              <access>read-write</access>
              <enumeratedValues>
                <enumeratedValue>
                  <name>0</name>
                  <description>Standard bus operation.</description>
                  <value>#0</value>
                </enumeratedValue>
                <enumeratedValue>
                  <name>1</name>
                  <description>Loss of arbitration.</description>
                  <value>#1</value>
                </enumeratedValue>
              </enumeratedValues>
            </field>
            <field>
              <name>BUSY</name>
              <description>Bus Busy</description>
              <bitOffset>5</bitOffset>
              <bitWidth>1</bitWidth>
              <access>read-only</access>
              <enumeratedValues>
                <enumeratedValue>
                  <name>0</name>
                  <description>Bus is idle</description>
                  <value>#0</value>
                </enumeratedValue>
                <enumeratedValue>
                  <name>1</name>
                  <description>Bus is busy</description>
                  <value>#1</value>
                </enumeratedValue>
              </enumeratedValues>
            </field>
            <field>
              <name>IAAS</name>
              <description>Addressed As A Slave</description>
              <bitOffset>6</bitOffset>
              <bitWidth>1</bitWidth>
              <access>read-write</access>
              <enumeratedValues>
                <enumeratedValue>
                  <name>0</name>
                  <description>Not addressed</description>
                  <value>#0</value>
                </enumeratedValue>
                <enumeratedValue>
                  <name>1</name>
                  <description>Addressed as a slave</description>
                  <value>#1</value>
                </enumeratedValue>
              </enumeratedValues>
            </field>
            <field>
              <name>TCF</name>
              <description>Transfer Complete Flag</description>
              <bitOffset>7</bitOffset>
              <bitWidth>1</bitWidth>
              <access>read-only</access>
              <enumeratedValues>
                <enumeratedValue>
                  <name>0</name>
                  <description>Transfer in progress</description>
                  <value>#0</value>
                </enumeratedValue>
                <enumeratedValue>
                  <name>1</name>
                  <description>Transfer complete</description>
                  <value>#1</value>
                </enumeratedValue>
              </enumeratedValues>
            </field>
          </fields>
        </register>
        <register>
          <name>D</name>
          <description>I2C Data I/O register</description>
          <addressOffset>0x4</addressOffset>
          <size>8</size>
          <access>read-write</access>
          <resetValue>0</resetValue>
          <resetMask>0xFF</resetMask>
          <fields>
            <field>
              <name>DATA</name>
              <description>Data</description>
              <bitOffset>0</bitOffset>
              <bitWidth>8</bitWidth>
              <access>read-write</access>
            </field>
          </fields>
        </register>
        <register>
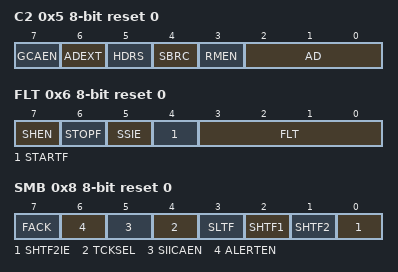
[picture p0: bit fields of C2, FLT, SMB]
          <name>C2</name>
          <description>I2C Control Register 2</description>
          <addressOffset>0x5</addressOffset>
          <size>8</size>
          <access>read-write</access>
          <resetValue>0</resetValue>
          <resetMask>0xFF</resetMask>
          <fields>
            <field>
              <name>AD</name>
              <description>Slave Address</description>
              <bitOffset>0</bitOffset>
              <bitWidth>3</bitWidth>
              <access>read-write</access>
            </field>
            <field>
              <name>RMEN</name>
              <description>Range Address Matching Enable</description>
              <bitOffset>3</bitOffset>
              <bitWidth>1</bitWidth>
              <access>read-write</access>
              <enumeratedValues>
                <enumeratedValue>
                  <name>0</name>
                  <description>Range mode disabled. No address match occurs for an address within the range of values of the A1 and RA registers.</description>
                  <value>#0</value>
                </enumeratedValue>
                <enumeratedValue>
                  <name>1</name>
                  <description>Range mode enabled. Address matching occurs when a slave receives an address within the range of values of the A1 and RA registers.</description>
                  <value>#1</value>
                </enumeratedValue>
              </enumeratedValues>
            </field>
            <field>
              <name>SBRC</name>
              <description>Slave Baud Rate Control</description>
              <bitOffset>4</bitOffset>
              <bitWidth>1</bitWidth>
              <access>read-write</access>
              <enumeratedValues>
                <enumeratedValue>
                  <name>0</name>
                  <description>The slave baud rate follows the master baud rate and clock stretching may occur</description>
                  <value>#0</value>
                </enumeratedValue>
                <enumeratedValue>
                  <name>1</name>
                  <description>Slave baud rate is independent of the master baud rate</description>
                  <value>#1</value>
                </enumeratedValue>
              </enumeratedValues>
            </field>
            <field>
              <name>HDRS</name>
              <description>High Drive Select</description>
              <bitOffset>5</bitOffset>
              <bitWidth>1</bitWidth>
              <access>read-write</access>
              <enumeratedValues>
                <enumeratedValue>
                  <name>0</name>
                  <description>Normal drive mode</description>
                  <value>#0</value>
                </enumeratedValue>
                <enumeratedValue>
                  <name>1</name>
                  <description>High drive mode</description>
                  <value>#1</value>
                </enumeratedValue>
              </enumeratedValues>
            </field>
            <field>
              <name>ADEXT</name>
              <description>Address Extension</description>
              <bitOffset>6</bitOffset>
              <bitWidth>1</bitWidth>
              <access>read-write</access>
              <enumeratedValues>
                <enumeratedValue>
                  <name>0</name>
                  <description>7-bit address scheme</description>
                  <value>#0</value>
                </enumeratedValue>
                <enumeratedValue>
                  <name>1</name>
                  <description>10-bit address scheme</description>
                  <value>#1</value>
                </enumeratedValue>
              </enumeratedValues>
            </field>
            <field>
              <name>GCAEN</name>
              <description>General Call Address Enable</description>
              <bitOffset>7</bitOffset>
              <bitWidth>1</bitWidth>
              <access>read-write</access>
              <enumeratedValues>
                <enumeratedValue>
                  <name>0</name>
                  <description>Disabled</description>
                  <value>#0</value>
                </enumeratedValue>
                <enumeratedValue>
                  <name>1</name>
                  <description>Enabled</description>
                  <value>#1</value>
                </enumeratedValue>
              </enumeratedValues>
            </field>
          </fields>
        </register>
        <register>
          <name>FLT</name>
          <description>I2C Programmable Input Glitch Filter register</description>
          <addressOffset>0x6</addressOffset>
          <size>8</size>
          <access>read-write</access>
          <resetValue>0</resetValue>
          <resetMask>0xFF</resetMask>
          <fields>
            <field>
              <name>FLT</name>
              <description>I2C Programmable Filter Factor</description>
              <bitOffset>0</bitOffset>
              <bitWidth>4</bitWidth>
              <access>read-write</access>
              <enumeratedValues>
                <enumeratedValue>
                  <name>0</name>
                  <description>No filter/bypass</description>
                  <value>#0000</value>
                </enumeratedValue>
              </enumeratedValues>
            </field>
            <field>
              <name>STARTF</name>
              <description>I2C Bus Start Detect Flag</description>
              <bitOffset>4</bitOffset>
              <bitWidth>1</bitWidth>
              <access>read-write</access>
              <enumeratedValues>
                <enumeratedValue>
                  <name>0</name>
                  <description>No start happens on I2C bus</description>
                  <value>#0</value>
                </enumeratedValue>
                <enumeratedValue>
                  <name>1</name>
                  <description>Start detected on I2C bus</description>
                  <value>#1</value>
                </enumeratedValue>
              </enumeratedValues>
            </field>
            <field>
              <name>SSIE</name>
              <description>I2C Bus Stop or Start Interrupt Enable</description>
              <bitOffset>5</bitOffset>
              <bitWidth>1</bitWidth>
              <access>read-write</access>
              <enumeratedValues>
                <enumeratedValue>
                  <name>0</name>
                  <description>Stop or start detection interrupt is disabled</description>
                  <value>#0</value>
                </enumeratedValue>
                <enumeratedValue>
                  <name>1</name>
                  <description>Stop or start detection interrupt is enabled</description>
                  <value>#1</value>
                </enumeratedValue>
              </enumeratedValues>
            </field>
            <field>
              <name>STOPF</name>
              <description>I2C Bus Stop Detect Flag</description>
              <bitOffset>6</bitOffset>
              <bitWidth>1</bitWidth>
              <access>read-write</access>
              <enumeratedValues>
                <enumeratedValue>
                  <name>0</name>
                  <description>No stop happens on I2C bus</description>
                  <value>#0</value>
                </enumeratedValue>
                <enumeratedValue>
                  <name>1</name>
                  <description>Stop detected on I2C bus</description>
                  <value>#1</value>
                </enumeratedValue>
              </enumeratedValues>
            </field>
            <field>
              <name>SHEN</name>
              <description>Stop Hold Enable</description>
              <bitOffset>7</bitOffset>
              <bitWidth>1</bitWidth>
              <access>read-write</access>
              <enumeratedValues>
                <enumeratedValue>
                  <name>0</name>
                  <description>Stop holdoff is disabled. The MCU&apos;s entry to stop mode is not gated.</description>
                  <value>#0</value>
                </enumeratedValue>
                <enumeratedValue>
                  <name>1</name>
                  <description>Stop holdoff is enabled.</description>
                  <value>#1</value>
                </enumeratedValue>
              </enumeratedValues>
            </field>
          </fields>
        </register>
        <register>
          <name>RA</name>
          <description>I2C Range Address register</description>
          <addressOffset>0x7</addressOffset>
          <size>8</size>
          <access>read-write</access>
          <resetValue>0</resetValue>
          <resetMask>0xFF</resetMask>
          <fields>
            <field>
              <name>RAD</name>
              <description>Range Slave Address</description>
              <bitOffset>1</bitOffset>
              <bitWidth>7</bitWidth>
              <access>read-write</access>
            </field>
          </fields>
        </register>
        <register>
          <name>SMB</name>
          <description>I2C SMBus Control and Status register</description>
          <addressOffset>0x8</addressOffset>
          <size>8</size>
          <access>read-write</access>
          <resetValue>0</resetValue>
          <resetMask>0xFF</resetMask>
          <fields>
            <field>
              <name>SHTF2IE</name>
              <description>SHTF2 Interrupt Enable</description>
              <bitOffset>0</bitOffset>
              <bitWidth>1</bitWidth>
              <access>read-write</access>
              <enumeratedValues>
                <enumeratedValue>
                  <name>0</name>
                  <description>SHTF2 interrupt is disabled</description>
                  <value>#0</value>
                </enumeratedValue>
                <enumeratedValue>
                  <name>1</name>
                  <description>SHTF2 interrupt is enabled</description>
                  <value>#1</value>
                </enumeratedValue>
              </enumeratedValues>
            </field>
            <field>
              <name>SHTF2</name>
              <description>SCL High Timeout Flag 2</description>
              <bitOffset>1</bitOffset>
              <bitWidth>1</bitWidth>
              <access>read-write</access>
              <enumeratedValues>
                <enumeratedValue>
                  <name>0</name>
                  <description>No SCL high and SDA low timeout occurs</description>
                  <value>#0</value>
                </enumeratedValue>
                <enumeratedValue>
                  <name>1</name>
                  <description>SCL high and SDA low timeout occurs</description>
                  <value>#1</value>
                </enumeratedValue>
              </enumeratedValues>
            </field>
            <field>
              <name>SHTF1</name>
              <description>SCL High Timeout Flag 1</description>
              <bitOffset>2</bitOffset>
              <bitWidth>1</bitWidth>
              <access>read-only</access>
              <enumeratedValues>
                <enumeratedValue>
                  <name>0</name>
                  <description>No SCL high and SDA high timeout occurs</description>
                  <value>#0</value>
                </enumeratedValue>
                <enumeratedValue>
                  <name>1</name>
                  <description>SCL high and SDA high timeout occurs</description>
                  <value>#1</value>
                </enumeratedValue>
              </enumeratedValues>
            </field>
            <field>
              <name>SLTF</name>
              <description>SCL Low Timeout Flag</description>
              <bitOffset>3</bitOffset>
              <bitWidth>1</bitWidth>
              <access>read-write</access>
              <enumeratedValues>
                <enumeratedValue>
                  <name>0</name>
                  <description>No low timeout occurs</description>
                  <value>#0</value>
                </enumeratedValue>
                <enumeratedValue>
                  <name>1</name>
                  <description>Low timeout occurs</description>
                  <value>#1</value>
                </enumeratedValue>
              </enumeratedValues>
            </field>
            <field>
              <name>TCKSEL</name>
              <description>Timeout Counter Clock Select</description>
              <bitOffset>4</bitOffset>
              <bitWidth>1</bitWidth>
              <access>read-write</access>
              <enumeratedValues>
                <enumeratedValue>
                  <name>0</name>
                  <description>Timeout counter counts at the frequency of the I2C module clock / 64</description>
                  <value>#0</value>
                </enumeratedValue>
                <enumeratedValue>
                  <name>1</name>
                  <description>Timeout counter counts at the frequency of the I2C module clock</description>
                  <value>#1</value>
                </enumeratedValue>
              </enumeratedValues>
            </field>
            <field>
              <name>SIICAEN</name>
              <description>Second I2C Address Enable</description>
              <bitOffset>5</bitOffset>
              <bitWidth>1</bitWidth>
              <access>read-write</access>
              <enumeratedValues>
                <enumeratedValue>
                  <name>0</name>
                  <description>I2C address register 2 matching is disabled</description>
                  <value>#0</value>
                </enumeratedValue>
                <enumeratedValue>
                  <name>1</name>
                  <description>I2C address register 2 matching is enabled</description>
                  <value>#1</value>
                </enumeratedValue>
              </enumeratedValues>
            </field>
            <field>
              <name>ALERTEN</name>
              <description>SMBus Alert Response Address Enable</description>
              <bitOffset>6</bitOffset>
              <bitWidth>1</bitWidth>
              <access>read-write</access>
              <enumeratedValues>
                <enumeratedValue>
                  <name>0</name>
                  <description>SMBus alert response address matching is disabled</description>
                  <value>#0</value>
                </enumeratedValue>
                <enumeratedValue>
                  <name>1</name>
                  <description>SMBus alert response address matching is enabled</description>
                  <value>#1</value>
                </enumeratedValue>
              </enumeratedValues>
            </field>
            <field>
              <name>FACK</name>
              <description>Fast NACK/ACK Enable</description>
              <bitOffset>7</bitOffset>
              <bitWidth>1</bitWidth>
              <access>read-write</access>
              <enumeratedValues>
                <enumeratedValue>
                  <name>0</name>
                  <description>An ACK or NACK is sent on the following receiving data byte</description>
                  <value>#0</value>
                </enumeratedValue>
                <enumeratedValue>
                  <name>1</name>
                  <description>Writing 0 to TXAK after receiving a data byte generates an ACK. Writing 1 to TXAK after receiving a data byte generates a NACK.</description>
                  <value>#1</value>
                </enumeratedValue>
              </enumeratedValues>
            </field>
          </fields>
        </register>
        <register>
          <name>A2</name>
          <description>I2C Address Register 2</description>
          <addressOffset>0x9</addressOffset>
          <size>8</size>
          <access>read-write</access>
          <resetValue>0xC2</resetValue>
          <resetMask>0xFF</resetMask>
          <fields>
            <field>
              <name>SAD</name>
              <description>SMBus Address</description>
              <bitOffset>1</bitOffset>
              <bitWidth>7</bitWidth>
              <access>read-write</access>
            </field>
          </fields>
        </register>
        <register>
          <name>SLTH</name>
          <description>I2C SCL Low Timeout Register High</description>
          <addressOffset>0xA</addressOffset>
          <size>8</size>
          <access>read-write</access>
          <resetValue>0</resetValue>
          <resetMask>0xFF</resetMask>
          <fields>
            <field>
              <name>SSLT</name>
              <description>Most significant byte of SCL low timeout value that determines the timeout period of SCL low.</description>
              <bitOffset>0</bitOffset>
              <bitWidth>8</bitWidth>
              <access>read-write</access>
            </field>
          </fields>
        </register>
        <register>
          <name>SLTL</name>
          <description>I2C SCL Low Timeout Register Low</description>
          <addressOffset>0xB</addressOffset>
          <size>8</size>
          <access>read-write</access>
          <resetValue>0</resetValue>
          <resetMask>0xFF</resetMask>
          <fields>
            <field>
              <name>SSLT</name>
              <description>Least significant byte of SCL low timeout value that determines the timeout period of SCL low.</description>
              <bitOffset>0</bitOffset>
              <bitWidth>8</bitWidth>
              <access>read-write</access>
            </field>
          </fields>
        </register>
      </registers>
    </peripheral>
    <peripheral>
      <name>I2C1</name>
      <description>Inter-Integrated Circuit</description>
      <groupName>I2C</groupName>
      <prependToName>I2C1_</prependToName>
      <baseAddress>0x40067000</baseAddress>
      <addressBlock>
        <offset>0</offset>
        <size>0xC</size>
        <usage>registers</usage>
      </addressBlock>
      <interrupt>
        <name>I2C1</name>
        <value>9</value>
      </interrupt>
      <registers>
        <register>
          <name>A1</name>
          <description>I2C Address Register 1</description>
          <addressOffset>0</addressOffset>
          <size>8</size>
          <access>read-write</access>
          <resetValue>0</resetValue>
          <resetMask>0xFF</resetMask>
          <fields>
            <field>
              <name>AD</name>
              <description>Address</description>
              <bitOffset>1</bitOffset>
              <bitWidth>7</bitWidth>
              <access>read-write</access>
            </field>
          </fields>
        </register>
        <register>
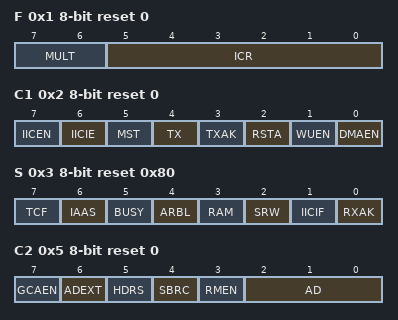
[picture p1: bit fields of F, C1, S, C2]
          <name>F</name>
          <description>I2C Frequency Divider register</description>
          <addressOffset>0x1</addressOffset>
          <size>8</size>
          <access>read-write</access>
          <resetValue>0</resetValue>
          <resetMask>0xFF</resetMask>
          <fields>
            <field>
              <name>ICR</name>
              <description>ClockRate</description>
              <bitOffset>0</bitOffset>
              <bitWidth>6</bitWidth>
              <access>read-write</access>
            </field>
            <field>
              <name>MULT</name>
              <description>Multiplier Factor</description>
              <bitOffset>6</bitOffset>
              <bitWidth>2</bitWidth>
              <access>read-write</access>
              <enumeratedValues>
                <enumeratedValue>
                  <name>00</name>
                  <description>mul = 1</description>
                  <value>#00</value>
                </enumeratedValue>
                <enumeratedValue>
                  <name>01</name>
                  <description>mul = 2</description>
                  <value>#01</value>
                </enumeratedValue>
                <enumeratedValue>
                  <name>10</name>
                  <description>mul = 4</description>
                  <value>#10</value>
                </enumeratedValue>
              </enumeratedValues>
            </field>
          </fields>
        </register>
        <register>
          <name>C1</name>
          <description>I2C Control Register 1</description>
          <addressOffset>0x2</addressOffset>
          <size>8</size>
          <access>read-write</access>
          <resetValue>0</resetValue>
          <resetMask>0xFF</resetMask>
          <fields>
            <field>
              <name>DMAEN</name>
              <description>DMA Enable</description>
              <bitOffset>0</bitOffset>
              <bitWidth>1</bitWidth>
              <access>read-write</access>
              <enumeratedValues>
                <enumeratedValue>
                  <name>0</name>
                  <description>All DMA signalling disabled.</description>
                  <value>#0</value>
                </enumeratedValue>
                <enumeratedValue>
                  <name>1</name>
                  <description>DMA transfer is enabled. While SMB[FACK] = 0, the following conditions trigger the DMA request: a data byte is received, and either address or data is transmitted. (ACK/NACK is automatic) the first byte received matches the A1 register or is a general call address. If any address matching occurs, S[IAAS] and S[TCF] are set. If the direction of transfer is known from master to slave, then it is not required to check S[SRW]. With this assumption, DMA can also be used in this case. In other cases, if the master reads data from the slave, then it is required to rewrite the C1 register operation. With this assumption, DMA cannot be used. When FACK = 1, an address or a data byte is transmitted.</description>
                  <value>#1</value>
                </enumeratedValue>
              </enumeratedValues>
            </field>
            <field>
              <name>WUEN</name>
              <description>Wakeup Enable</description>
              <bitOffset>1</bitOffset>
              <bitWidth>1</bitWidth>
              <access>read-write</access>
              <enumeratedValues>
                <enumeratedValue>
                  <name>0</name>
                  <description>Normal operation. No interrupt generated when address matching in low power mode.</description>
                  <value>#0</value>
                </enumeratedValue>
                <enumeratedValue>
                  <name>1</name>
                  <description>Enables the wakeup function in low power mode.</description>
                  <value>#1</value>
                </enumeratedValue>
              </enumeratedValues>
            </field>
            <field>
              <name>RSTA</name>
              <description>Repeat START</description>
              <bitOffset>2</bitOffset>
              <bitWidth>1</bitWidth>
              <access>write-only</access>
            </field>
            <field>
              <name>TXAK</name>
              <description>Transmit Acknowledge Enable</description>
              <bitOffset>3</bitOffset>
              <bitWidth>1</bitWidth>
              <access>read-write</access>
              <enumeratedValues>
                <enumeratedValue>
                  <name>0</name>
                  <description>An acknowledge signal is sent to the bus on the following receiving byte (if FACK is cleared) or the current receiving byte (if FACK is set).</description>
                  <value>#0</value>
                </enumeratedValue>
                <enumeratedValue>
                  <name>1</name>
                  <description>No acknowledge signal is sent to the bus on the following receiving data byte (if FACK is cleared) or the current receiving data byte (if FACK is set).</description>
                  <value>#1</value>
                </enumeratedValue>
              </enumeratedValues>
            </field>
            <field>
              <name>TX</name>
              <description>Transmit Mode Select</description>
              <bitOffset>4</bitOffset>
              <bitWidth>1</bitWidth>
              <access>read-write</access>
              <enumeratedValues>
                <enumeratedValue>
                  <name>0</name>
                  <description>Receive</description>
                  <value>#0</value>
                </enumeratedValue>
                <enumeratedValue>
                  <name>1</name>
                  <description>Transmit</description>
                  <value>#1</value>
                </enumeratedValue>
              </enumeratedValues>
            </field>
            <field>
              <name>MST</name>
              <description>Master Mode Select</description>
              <bitOffset>5</bitOffset>
              <bitWidth>1</bitWidth>
              <access>read-write</access>
              <enumeratedValues>
                <enumeratedValue>
                  <name>0</name>
                  <description>Slave mode</description>
                  <value>#0</value>
                </enumeratedValue>
                <enumeratedValue>
                  <name>1</name>
                  <description>Master mode</description>
                  <value>#1</value>
                </enumeratedValue>
              </enumeratedValues>
            </field>
            <field>
              <name>IICIE</name>
              <description>I2C Interrupt Enable</description>
              <bitOffset>6</bitOffset>
              <bitWidth>1</bitWidth>
              <access>read-write</access>
              <enumeratedValues>
                <enumeratedValue>
                  <name>0</name>
                  <description>Disabled</description>
                  <value>#0</value>
                </enumeratedValue>
                <enumeratedValue>
                  <name>1</name>
                  <description>Enabled</description>
                  <value>#1</value>
                </enumeratedValue>
              </enumeratedValues>
            </field>
            <field>
              <name>IICEN</name>
              <description>I2C Enable</description>
              <bitOffset>7</bitOffset>
              <bitWidth>1</bitWidth>
              <access>read-write</access>
              <enumeratedValues>
                <enumeratedValue>
                  <name>0</name>
                  <description>Disabled</description>
                  <value>#0</value>
                </enumeratedValue>
                <enumeratedValue>
                  <name>1</name>
                  <description>Enabled</description>
                  <value>#1</value>
                </enumeratedValue>
              </enumeratedValues>
            </field>
          </fields>
        </register>
        <register>
          <name>S</name>
          <description>I2C Status register</description>
          <addressOffset>0x3</addressOffset>
          <size>8</size>
          <access>read-write</access>
          <resetValue>0x80</resetValue>
          <resetMask>0xFF</resetMask>
          <fields>
            <field>
              <name>RXAK</name>
              <description>Receive Acknowledge</description>
              <bitOffset>0</bitOffset>
              <bitWidth>1</bitWidth>
              <access>read-only</access>
              <enumeratedValues>
                <enumeratedValue>
                  <name>0</name>
                  <description>Acknowledge signal was received after the completion of one byte of data transmission on the bus</description>
                  <value>#0</value>
                </enumeratedValue>
                <enumeratedValue>
                  <name>1</name>
                  <description>No acknowledge signal detected</description>
                  <value>#1</value>
                </enumeratedValue>
              </enumeratedValues>
            </field>
            <field>
              <name>IICIF</name>
              <description>Interrupt Flag</description>
              <bitOffset>1</bitOffset>
              <bitWidth>1</bitWidth>
              <access>read-write</access>
              <enumeratedValues>
                <enumeratedValue>
                  <name>0</name>
                  <description>No interrupt pending</description>
                  <value>#0</value>
                </enumeratedValue>
                <enumeratedValue>
                  <name>1</name>
                  <description>Interrupt pending</description>
                  <value>#1</value>
                </enumeratedValue>
              </enumeratedValues>
            </field>
            <field>
              <name>SRW</name>
              <description>Slave Read/Write</description>
              <bitOffset>2</bitOffset>
              <bitWidth>1</bitWidth>
              <access>read-only</access>
              <enumeratedValues>
                <enumeratedValue>
                  <name>0</name>
                  <description>Slave receive, master writing to slave</description>
                  <value>#0</value>
                </enumeratedValue>
                <enumeratedValue>
                  <name>1</name>
                  <description>Slave transmit, master reading from slave</description>
                  <value>#1</value>
                </enumeratedValue>
              </enumeratedValues>
            </field>
            <field>
              <name>RAM</name>
              <description>Range Address Match</description>
              <bitOffset>3</bitOffset>
              <bitWidth>1</bitWidth>
              <access>read-write</access>
              <enumeratedValues>
                <enumeratedValue>
                  <name>0</name>
                  <description>Not addressed</description>
                  <value>#0</value>
                </enumeratedValue>
                <enumeratedValue>
                  <name>1</name>
                  <description>Addressed as a slave</description>
                  <value>#1</value>
                </enumeratedValue>
              </enumeratedValues>
            </field>
            <field>
              <name>ARBL</name>
              <description>Arbitration Lost</description>
              <bitOffset>4</bitOffset>
              <bitWidth>1</bitWidth>
              <access>read-write</access>
              <enumeratedValues>
                <enumeratedValue>
                  <name>0</name>
                  <description>Standard bus operation.</description>
                  <value>#0</value>
                </enumeratedValue>
                <enumeratedValue>
                  <name>1</name>
                  <description>Loss of arbitration.</description>
                  <value>#1</value>
                </enumeratedValue>
              </enumeratedValues>
            </field>
            <field>
              <name>BUSY</name>
              <description>Bus Busy</description>
              <bitOffset>5</bitOffset>
              <bitWidth>1</bitWidth>
              <access>read-only</access>
              <enumeratedValues>
                <enumeratedValue>
                  <name>0</name>
                  <description>Bus is idle</description>
                  <value>#0</value>
                </enumeratedValue>
                <enumeratedValue>
                  <name>1</name>
                  <description>Bus is busy</description>
                  <value>#1</value>
                </enumeratedValue>
              </enumeratedValues>
            </field>
            <field>
              <name>IAAS</name>
              <description>Addressed As A Slave</description>
              <bitOffset>6</bitOffset>
              <bitWidth>1</bitWidth>
              <access>read-write</access>
              <enumeratedValues>
                <enumeratedValue>
                  <name>0</name>
                  <description>Not addressed</description>
                  <value>#0</value>
                </enumeratedValue>
                <enumeratedValue>
                  <name>1</name>
                  <description>Addressed as a slave</description>
                  <value>#1</value>
                </enumeratedValue>
              </enumeratedValues>
            </field>
            <field>
              <name>TCF</name>
              <description>Transfer Complete Flag</description>
              <bitOffset>7</bitOffset>
              <bitWidth>1</bitWidth>
              <access>read-only</access>
              <enumeratedValues>
                <enumeratedValue>
                  <name>0</name>
                  <description>Transfer in progress</description>
                  <value>#0</value>
                </enumeratedValue>
                <enumeratedValue>
                  <name>1</name>
                  <description>Transfer complete</description>
                  <value>#1</value>
                </enumeratedValue>
              </enumeratedValues>
            </field>
          </fields>
        </register>
        <register>
          <name>D</name>
          <description>I2C Data I/O register</description>
          <addressOffset>0x4</addressOffset>
          <size>8</size>
          <access>read-write</access>
          <resetValue>0</resetValue>
          <resetMask>0xFF</resetMask>
          <fields>
            <field>
              <name>DATA</name>
              <description>Data</description>
              <bitOffset>0</bitOffset>
              <bitWidth>8</bitWidth>
              <access>read-write</access>
            </field>
          </fields>
        </register>
        <register>
          <name>C2</name>
          <description>I2C Control Register 2</description>
          <addressOffset>0x5</addressOffset>
          <size>8</size>
          <access>read-write</access>
          <resetValue>0</resetValue>
          <resetMask>0xFF</resetMask>
          <fields>
            <field>
              <name>AD</name>
              <description>Slave Address</description>
              <bitOffset>0</bitOffset>
              <bitWidth>3</bitWidth>
              <access>read-write</access>
            </field>
            <field>
              <name>RMEN</name>
              <description>Range Address Matching Enable</description>
              <bitOffset>3</bitOffset>
              <bitWidth>1</bitWidth>
              <access>read-write</access>
              <enumeratedValues>
                <enumeratedValue>
                  <name>0</name>
                  <description>Range mode disabled. No address match occurs for an address within the range of values of the A1 and RA registers.</description>
                  <value>#0</value>
                </enumeratedValue>
                <enumeratedValue>
                  <name>1</name>
                  <description>Range mode enabled. Address matching occurs when a slave receives an address within the range of values of the A1 and RA registers.</description>
                  <value>#1</value>
                </enumeratedValue>
              </enumeratedValues>
            </field>
            <field>
              <name>SBRC</name>
              <description>Slave Baud Rate Control</description>
              <bitOffset>4</bitOffset>
              <bitWidth>1</bitWidth>
              <access>read-write</access>
              <enumeratedValues>
                <enumeratedValue>
                  <name>0</name>
                  <description>The slave baud rate follows the master baud rate and clock stretching may occur</description>
                  <value>#0</value>
                </enumeratedValue>
                <enumeratedValue>
                  <name>1</name>
                  <description>Slave baud rate is independent of the master baud rate</description>
                  <value>#1</value>
                </enumeratedValue>
              </enumeratedValues>
            </field>
            <field>
              <name>HDRS</name>
              <description>High Drive Select</description>
              <bitOffset>5</bitOffset>
              <bitWidth>1</bitWidth>
              <access>read-write</access>
              <enumeratedValues>
                <enumeratedValue>
                  <name>0</name>
                  <description>Normal drive mode</description>
                  <value>#0</value>
                </enumeratedValue>
                <enumeratedValue>
                  <name>1</name>
                  <description>High drive mode</description>
                  <value>#1</value>
                </enumeratedValue>
              </enumeratedValues>
            </field>
            <field>
              <name>ADEXT</name>
              <description>Address Extension</description>
              <bitOffset>6</bitOffset>
              <bitWidth>1</bitWidth>
              <access>read-write</access>
              <enumeratedValues>
                <enumeratedValue>
                  <name>0</name>
                  <description>7-bit address scheme</description>
                  <value>#0</value>
                </enumeratedValue>
                <enumeratedValue>
                  <name>1</name>
                  <description>10-bit address scheme</description>
                  <value>#1</value>
                </enumeratedValue>
              </enumeratedValues>
            </field>
            <field>
              <name>GCAEN</name>
              <description>General Call Address Enable</description>
              <bitOffset>7</bitOffset>
              <bitWidth>1</bitWidth>
              <access>read-write</access>
              <enumeratedValues>
                <enumeratedValue>
                  <name>0</name>
                  <description>Disabled</description>
                  <value>#0</value>
                </enumeratedValue>
                <enumeratedValue>
                  <name>1</name>
                  <description>Enabled</description>
                  <value>#1</value>
                </enumeratedValue>
              </enumeratedValues>
            </field>
          </fields>
        </register>
        <register>
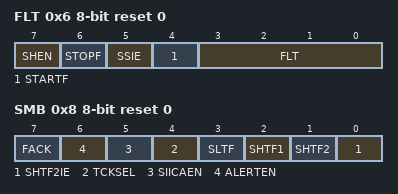
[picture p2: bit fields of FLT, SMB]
          <name>FLT</name>
          <description>I2C Programmable Input Glitch Filter register</description>
          <addressOffset>0x6</addressOffset>
          <size>8</size>
          <access>read-write</access>
          <resetValue>0</resetValue>
          <resetMask>0xFF</resetMask>
          <fields>
            <field>
              <name>FLT</name>
              <description>I2C Programmable Filter Factor</description>
              <bitOffset>0</bitOffset>
              <bitWidth>4</bitWidth>
              <access>read-write</access>
              <enumeratedValues>
                <enumeratedValue>
                  <name>0</name>
                  <description>No filter/bypass</description>
                  <value>#0000</value>
                </enumeratedValue>
              </enumeratedValues>
            </field>
            <field>
              <name>STARTF</name>
              <description>I2C Bus Start Detect Flag</description>
              <bitOffset>4</bitOffset>
              <bitWidth>1</bitWidth>
              <access>read-write</access>
              <enumeratedValues>
                <enumeratedValue>
                  <name>0</name>
                  <description>No start happens on I2C bus</description>
                  <value>#0</value>
                </enumeratedValue>
                <enumeratedValue>
                  <name>1</name>
                  <description>Start detected on I2C bus</description>
                  <value>#1</value>
                </enumeratedValue>
              </enumeratedValues>
            </field>
            <field>
              <name>SSIE</name>
              <description>I2C Bus Stop or Start Interrupt Enable</description>
              <bitOffset>5</bitOffset>
              <bitWidth>1</bitWidth>
              <access>read-write</access>
              <enumeratedValues>
                <enumeratedValue>
                  <name>0</name>
                  <description>Stop or start detection interrupt is disabled</description>
                  <value>#0</value>
                </enumeratedValue>
                <enumeratedValue>
                  <name>1</name>
                  <description>Stop or start detection interrupt is enabled</description>
                  <value>#1</value>
                </enumeratedValue>
              </enumeratedValues>
            </field>
            <field>
              <name>STOPF</name>
              <description>I2C Bus Stop Detect Flag</description>
              <bitOffset>6</bitOffset>
              <bitWidth>1</bitWidth>
              <access>read-write</access>
              <enumeratedValues>
                <enumeratedValue>
                  <name>0</name>
                  <description>No stop happens on I2C bus</description>
                  <value>#0</value>
                </enumeratedValue>
                <enumeratedValue>
                  <name>1</name>
                  <description>Stop detected on I2C bus</description>
                  <value>#1</value>
                </enumeratedValue>
              </enumeratedValues>
            </field>
            <field>
              <name>SHEN</name>
              <description>Stop Hold Enable</description>
              <bitOffset>7</bitOffset>
              <bitWidth>1</bitWidth>
              <access>read-write</access>
              <enumeratedValues>
                <enumeratedValue>
                  <name>0</name>
                  <description>Stop holdoff is disabled. The MCU&apos;s entry to stop mode is not gated.</description>
                  <value>#0</value>
                </enumeratedValue>
                <enumeratedValue>
                  <name>1</name>
                  <description>Stop holdoff is enabled.</description>
                  <value>#1</value>
                </enumeratedValue>
              </enumeratedValues>
            </field>
          </fields>
        </register>
        <register>
          <name>RA</name>
          <description>I2C Range Address register</description>
          <addressOffset>0x7</addressOffset>
          <size>8</size>
          <access>read-write</access>
          <resetValue>0</resetValue>
          <resetMask>0xFF</resetMask>
          <fields>
            <field>
              <name>RAD</name>
              <description>Range Slave Address</description>
              <bitOffset>1</bitOffset>
              <bitWidth>7</bitWidth>
              <access>read-write</access>
            </field>
          </fields>
        </register>
        <register>
          <name>SMB</name>
          <description>I2C SMBus Control and Status register</description>
          <addressOffset>0x8</addressOffset>
          <size>8</size>
          <access>read-write</access>
          <resetValue>0</resetValue>
          <resetMask>0xFF</resetMask>
          <fields>
            <field>
              <name>SHTF2IE</name>
              <description>SHTF2 Interrupt Enable</description>
              <bitOffset>0</bitOffset>
              <bitWidth>1</bitWidth>
              <access>read-write</access>
              <enumeratedValues>
                <enumeratedValue>
                  <name>0</name>
                  <description>SHTF2 interrupt is disabled</description>
                  <value>#0</value>
                </enumeratedValue>
                <enumeratedValue>
                  <name>1</name>
                  <description>SHTF2 interrupt is enabled</description>
                  <value>#1</value>
                </enumeratedValue>
              </enumeratedValues>
            </field>
            <field>
              <name>SHTF2</name>
              <description>SCL High Timeout Flag 2</description>
              <bitOffset>1</bitOffset>
              <bitWidth>1</bitWidth>
              <access>read-write</access>
              <enumeratedValues>
                <enumeratedValue>
                  <name>0</name>
                  <description>No SCL high and SDA low timeout occurs</description>
                  <value>#0</value>
                </enumeratedValue>
                <enumeratedValue>
                  <name>1</name>
                  <description>SCL high and SDA low timeout occurs</description>
                  <value>#1</value>
                </enumeratedValue>
              </enumeratedValues>
            </field>
            <field>
              <name>SHTF1</name>
              <description>SCL High Timeout Flag 1</description>
              <bitOffset>2</bitOffset>
              <bitWidth>1</bitWidth>
              <access>read-only</access>
              <enumeratedValues>
                <enumeratedValue>
                  <name>0</name>
                  <description>No SCL high and SDA high timeout occurs</description>
                  <value>#0</value>
                </enumeratedValue>
                <enumeratedValue>
                  <name>1</name>
                  <description>SCL high and SDA high timeout occurs</description>
                  <value>#1</value>
                </enumeratedValue>
              </enumeratedValues>
            </field>
            <field>
              <name>SLTF</name>
              <description>SCL Low Timeout Flag</description>
              <bitOffset>3</bitOffset>
              <bitWidth>1</bitWidth>
              <access>read-write</access>
              <enumeratedValues>
                <enumeratedValue>
                  <name>0</name>
                  <description>No low timeout occurs</description>
                  <value>#0</value>
                </enumeratedValue>
                <enumeratedValue>
                  <name>1</name>
                  <description>Low timeout occurs</description>
                  <value>#1</value>
                </enumeratedValue>
              </enumeratedValues>
            </field>
            <field>
              <name>TCKSEL</name>
              <description>Timeout Counter Clock Select</description>
              <bitOffset>4</bitOffset>
              <bitWidth>1</bitWidth>
              <access>read-write</access>
              <enumeratedValues>
                <enumeratedValue>
                  <name>0</name>
                  <description>Timeout counter counts at the frequency of the I2C module clock / 64</description>
                  <value>#0</value>
                </enumeratedValue>
                <enumeratedValue>
                  <name>1</name>
                  <description>Timeout counter counts at the frequency of the I2C module clock</description>
                  <value>#1</value>
                </enumeratedValue>
              </enumeratedValues>
            </field>
            <field>
              <name>SIICAEN</name>
              <description>Second I2C Address Enable</description>
              <bitOffset>5</bitOffset>
              <bitWidth>1</bitWidth>
              <access>read-write</access>
              <enumeratedValues>
                <enumeratedValue>
                  <name>0</name>
                  <description>I2C address register 2 matching is disabled</description>
                  <value>#0</value>
                </enumeratedValue>
                <enumeratedValue>
                  <name>1</name>
                  <description>I2C address register 2 matching is enabled</description>
                  <value>#1</value>
                </enumeratedValue>
              </enumeratedValues>
            </field>
            <field>
              <name>ALERTEN</name>
              <description>SMBus Alert Response Address Enable</description>
              <bitOffset>6</bitOffset>
              <bitWidth>1</bitWidth>
              <access>read-write</access>
              <enumeratedValues>
                <enumeratedValue>
                  <name>0</name>
                  <description>SMBus alert response address matching is disabled</description>
                  <value>#0</value>
                </enumeratedValue>
                <enumeratedValue>
                  <name>1</name>
                  <description>SMBus alert response address matching is enabled</description>
                  <value>#1</value>
                </enumeratedValue>
              </enumeratedValues>
            </field>
            <field>
              <name>FACK</name>
              <description>Fast NACK/ACK Enable</description>
              <bitOffset>7</bitOffset>
              <bitWidth>1</bitWidth>
              <access>read-write</access>
              <enumeratedValues>
                <enumeratedValue>
                  <name>0</name>
                  <description>An ACK or NACK is sent on the following receiving data byte</description>
                  <value>#0</value>
                </enumeratedValue>
                <enumeratedValue>
                  <name>1</name>
                  <description>Writing 0 to TXAK after receiving a data byte generates an ACK. Writing 1 to TXAK after receiving a data byte generates a NACK.</description>
                  <value>#1</value>
                </enumeratedValue>
              </enumeratedValues>
            </field>
          </fields>
        </register>
        <register>
          <name>A2</name>
          <description>I2C Address Register 2</description>
          <addressOffset>0x9</addressOffset>
          <size>8</size>
          <access>read-write</access>
          <resetValue>0xC2</resetValue>
          <resetMask>0xFF</resetMask>
          <fields>
            <field>
              <name>SAD</name>
              <description>SMBus Address</description>
              <bitOffset>1</bitOffset>
              <bitWidth>7</bitWidth>
              <access>read-write</access>
            </field>
          </fields>
        </register>
        <register>
          <name>SLTH</name>
          <description>I2C SCL Low Timeout Register High</description>
          <addressOffset>0xA</addressOffset>
          <size>8</size>
          <access>read-write</access>
          <resetValue>0</resetValue>
          <resetMask>0xFF</resetMask>
          <fields>
            <field>
              <name>SSLT</name>
              <description>Most significant byte of SCL low timeout value that determines the timeout period of SCL low.</description>
              <bitOffset>0</bitOffset>
              <bitWidth>8</bitWidth>
              <access>read-write</access>
            </field>
          </fields>
        </register>
        <register>
          <name>SLTL</name>
          <description>I2C SCL Low Timeout Register Low</description>
          <addressOffset>0xB</addressOffset>
          <size>8</size>
          <access>read-write</access>
          <resetValue>0</resetValue>
          <resetMask>0xFF</resetMask>
          <fields>
            <field>
              <name>SSLT</name>
              <description>Least significant byte of SCL low timeout value that determines the timeout period of SCL low.</description>
              <bitOffset>0</bitOffset>
              <bitWidth>8</bitWidth>
              <access>read-write</access>
            </field>
          </fields>
        </register>
      </registers>
    </peripheral>
    <peripheral>
      <name>UART0</name>
      <description>Universal Asynchronous Receiver/Transmitter</description>
      <prependToName>UART0_</prependToName>
      <baseAddress>0x4006A000</baseAddress>
      <addressBlock>
        <offset>0</offset>
        <size>0xC</size>
        <usage>registers</usage>
      </addressBlock>
      <interrupt>
        <name>UART0</name>
        <value>12</value>
      </interrupt>
      <registers>
        <register>
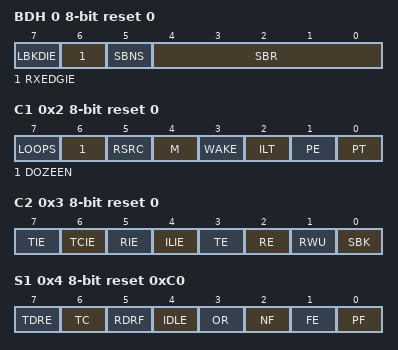
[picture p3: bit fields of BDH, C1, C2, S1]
          <name>BDH</name>
          <description>UART Baud Rate Register High</description>
          <addressOffset>0</addressOffset>
          <size>8</size>
          <access>read-write</access>
          <resetValue>0</resetValue>
          <resetMask>0xFF</resetMask>
          <fields>
            <field>
              <name>SBR</name>
              <description>Baud Rate Modulo Divisor.</description>
              <bitOffset>0</bitOffset>
              <bitWidth>5</bitWidth>
              <access>read-write</access>
            </field>
            <field>
              <name>SBNS</name>
              <description>Stop Bit Number Select</description>
              <bitOffset>5</bitOffset>
              <bitWidth>1</bitWidth>
              <access>read-write</access>
              <enumeratedValues>
                <enumeratedValue>
                  <name>0</name>
                  <description>One stop bit.</description>
                  <value>#0</value>
                </enumeratedValue>
                <enumeratedValue>
                  <name>1</name>
                  <description>Two stop bit.</description>
                  <value>#1</value>
                </enumeratedValue>
              </enumeratedValues>
            </field>
            <field>
              <name>RXEDGIE</name>
              <description>RX Input Active Edge Interrupt Enable (for RXEDGIF)</description>
              <bitOffset>6</bitOffset>
              <bitWidth>1</bitWidth>
              <access>read-write</access>
              <enumeratedValues>
                <enumeratedValue>
                  <name>0</name>
                  <description>Hardware interrupts from UART_S2[RXEDGIF] disabled (use polling).</description>
                  <value>#0</value>
                </enumeratedValue>
                <enumeratedValue>
                  <name>1</name>
                  <description>Hardware interrupt requested when UART_S2[RXEDGIF] flag is 1.</description>
                  <value>#1</value>
                </enumeratedValue>
              </enumeratedValues>
            </field>
            <field>
              <name>LBKDIE</name>
              <description>LIN Break Detect Interrupt Enable (for LBKDIF)</description>
              <bitOffset>7</bitOffset>
              <bitWidth>1</bitWidth>
              <access>read-write</access>
              <enumeratedValues>
                <enumeratedValue>
                  <name>0</name>
                  <description>Hardware interrupts from UART_S2[LBKDIF] disabled (use polling).</description>
                  <value>#0</value>
                </enumeratedValue>
                <enumeratedValue>
                  <name>1</name>
                  <description>Hardware interrupt requested when UART_S2[LBKDIF] flag is 1.</description>
                  <value>#1</value>
                </enumeratedValue>
              </enumeratedValues>
            </field>
          </fields>
        </register>
        <register>
          <name>BDL</name>
          <description>UART Baud Rate Register Low</description>
          <addressOffset>0x1</addressOffset>
          <size>8</size>
          <access>read-write</access>
          <resetValue>0x4</resetValue>
          <resetMask>0xFF</resetMask>
          <fields>
            <field>
              <name>SBR</name>
              <description>Baud Rate Modulo Divisor</description>
              <bitOffset>0</bitOffset>
              <bitWidth>8</bitWidth>
              <access>read-write</access>
            </field>
          </fields>
        </register>
        <register>
          <name>C1</name>
          <description>UART Control Register 1</description>
          <addressOffset>0x2</addressOffset>
          <size>8</size>
          <access>read-write</access>
          <resetValue>0</resetValue>
          <resetMask>0xFF</resetMask>
          <fields>
            <field>
              <name>PT</name>
              <description>Parity Type</description>
              <bitOffset>0</bitOffset>
              <bitWidth>1</bitWidth>
              <access>read-write</access>
              <enumeratedValues>
                <enumeratedValue>
                  <name>0</name>
                  <description>Even parity.</description>
                  <value>#0</value>
                </enumeratedValue>
                <enumeratedValue>
                  <name>1</name>
                  <description>Odd parity.</description>
                  <value>#1</value>
                </enumeratedValue>
              </enumeratedValues>
            </field>
            <field>
              <name>PE</name>
              <description>Parity Enable</description>
              <bitOffset>1</bitOffset>
              <bitWidth>1</bitWidth>
              <access>read-write</access>
              <enumeratedValues>
                <enumeratedValue>
                  <name>0</name>
                  <description>No hardware parity generation or checking.</description>
                  <value>#0</value>
                </enumeratedValue>
                <enumeratedValue>
                  <name>1</name>
                  <description>Parity enabled.</description>
                  <value>#1</value>
                </enumeratedValue>
              </enumeratedValues>
            </field>
            <field>
              <name>ILT</name>
              <description>Idle Line Type Select</description>
              <bitOffset>2</bitOffset>
              <bitWidth>1</bitWidth>
              <access>read-write</access>
              <enumeratedValues>
                <enumeratedValue>
                  <name>0</name>
                  <description>Idle character bit count starts after start bit.</description>
                  <value>#0</value>
                </enumeratedValue>
                <enumeratedValue>
                  <name>1</name>
                  <description>Idle character bit count starts after stop bit.</description>
                  <value>#1</value>
                </enumeratedValue>
              </enumeratedValues>
            </field>
            <field>
              <name>WAKE</name>
              <description>Receiver Wakeup Method Select</description>
              <bitOffset>3</bitOffset>
              <bitWidth>1</bitWidth>
              <access>read-write</access>
              <enumeratedValues>
                <enumeratedValue>
                  <name>0</name>
                  <description>Idle-line wakeup.</description>
                  <value>#0</value>
                </enumeratedValue>
                <enumeratedValue>
                  <name>1</name>
                  <description>Address-mark wakeup.</description>
                  <value>#1</value>
                </enumeratedValue>
              </enumeratedValues>
            </field>
            <field>
              <name>M</name>
              <description>9-Bit or 8-Bit Mode Select</description>
              <bitOffset>4</bitOffset>
              <bitWidth>1</bitWidth>
              <access>read-write</access>
              <enumeratedValues>
                <enumeratedValue>
                  <name>0</name>
                  <description>Receiver and transmitter use 8-bit data characters.</description>
                  <value>#0</value>
                </enumeratedValue>
                <enumeratedValue>
                  <name>1</name>
                  <description>Receiver and transmitter use 9-bit data characters.</description>
                  <value>#1</value>
                </enumeratedValue>
              </enumeratedValues>
            </field>
            <field>
              <name>RSRC</name>
              <description>Receiver Source Select</description>
              <bitOffset>5</bitOffset>
              <bitWidth>1</bitWidth>
              <access>read-write</access>
              <enumeratedValues>
                <enumeratedValue>
                  <name>0</name>
                  <description>Provided LOOPS is set, RSRC is cleared, selects internal loop back mode and the UART does not use the UART_RX pins.</description>
                  <value>#0</value>
                </enumeratedValue>
                <enumeratedValue>
                  <name>1</name>
                  <description>Single-wire UART mode where the UART_TX pin is connected to the transmitter output and receiver input.</description>
                  <value>#1</value>
                </enumeratedValue>
              </enumeratedValues>
            </field>
            <field>
              <name>DOZEEN</name>
              <description>Doze Enable</description>
              <bitOffset>6</bitOffset>
              <bitWidth>1</bitWidth>
              <access>read-write</access>
              <enumeratedValues>
                <enumeratedValue>
                  <name>0</name>
                  <description>UART is enabled in Wait mode.</description>
                  <value>#0</value>
                </enumeratedValue>
                <enumeratedValue>
                  <name>1</name>
                  <description>UART is disabled in Wait mode.</description>
                  <value>#1</value>
                </enumeratedValue>
              </enumeratedValues>
            </field>
            <field>
              <name>LOOPS</name>
              <description>Loop Mode Select</description>
              <bitOffset>7</bitOffset>
              <bitWidth>1</bitWidth>
              <access>read-write</access>
              <enumeratedValues>
                <enumeratedValue>
                  <name>0</name>
                  <description>Normal operation - UART_RX and UART_TX use separate pins.</description>
                  <value>#0</value>
                </enumeratedValue>
                <enumeratedValue>
                  <name>1</name>
                  <description>Loop mode or single-wire mode where transmitter outputs are internally connected to receiver input. (See RSRC bit.) UART_RX pin is not used by UART.</description>
                  <value>#1</value>
                </enumeratedValue>
              </enumeratedValues>
            </field>
          </fields>
        </register>
        <register>
          <name>C2</name>
          <description>UART Control Register 2</description>
          <addressOffset>0x3</addressOffset>
          <size>8</size>
          <access>read-write</access>
          <resetValue>0</resetValue>
          <resetMask>0xFF</resetMask>
          <fields>
            <field>
              <name>SBK</name>
              <description>Send Break</description>
              <bitOffset>0</bitOffset>
              <bitWidth>1</bitWidth>
              <access>read-write</access>
              <enumeratedValues>
                <enumeratedValue>
                  <name>0</name>
                  <description>Normal transmitter operation.</description>
                  <value>#0</value>
                </enumeratedValue>
                <enumeratedValue>
                  <name>1</name>
                  <description>Queue break character(s) to be sent.</description>
                  <value>#1</value>
                </enumeratedValue>
              </enumeratedValues>
            </field>
            <field>
              <name>RWU</name>
              <description>Receiver Wakeup Control</description>
              <bitOffset>1</bitOffset>
              <bitWidth>1</bitWidth>
              <access>read-write</access>
              <enumeratedValues>
                <enumeratedValue>
                  <name>0</name>
                  <description>Normal UART receiver operation.</description>
                  <value>#0</value>
                </enumeratedValue>
                <enumeratedValue>
                  <name>1</name>
                  <description>UART receiver in standby waiting for wakeup condition.</description>
                  <value>#1</value>
                </enumeratedValue>
              </enumeratedValues>
            </field>
            <field>
              <name>RE</name>
              <description>Receiver Enable</description>
              <bitOffset>2</bitOffset>
              <bitWidth>1</bitWidth>
              <access>read-write</access>
              <enumeratedValues>
                <enumeratedValue>
                  <name>0</name>
                  <description>Receiver disabled.</description>
                  <value>#0</value>
                </enumeratedValue>
                <enumeratedValue>
                  <name>1</name>
                  <description>Receiver enabled.</description>
                  <value>#1</value>
                </enumeratedValue>
              </enumeratedValues>
            </field>
            <field>
              <name>TE</name>
              <description>Transmitter Enable</description>
              <bitOffset>3</bitOffset>
              <bitWidth>1</bitWidth>
              <access>read-write</access>
              <enumeratedValues>
                <enumeratedValue>
                  <name>0</name>
                  <description>Transmitter disabled.</description>
                  <value>#0</value>
                </enumeratedValue>
                <enumeratedValue>
                  <name>1</name>
                  <description>Transmitter enabled.</description>
                  <value>#1</value>
                </enumeratedValue>
              </enumeratedValues>
            </field>
            <field>
              <name>ILIE</name>
              <description>Idle Line Interrupt Enable for IDLE</description>
              <bitOffset>4</bitOffset>
              <bitWidth>1</bitWidth>
              <access>read-write</access>
              <enumeratedValues>
                <enumeratedValue>
                  <name>0</name>
                  <description>Hardware interrupts from IDLE disabled; use polling.</description>
                  <value>#0</value>
                </enumeratedValue>
                <enumeratedValue>
                  <name>1</name>
                  <description>Hardware interrupt requested when IDLE flag is 1.</description>
                  <value>#1</value>
                </enumeratedValue>
              </enumeratedValues>
            </field>
            <field>
              <name>RIE</name>
              <description>Receiver Interrupt Enable for RDRF</description>
              <bitOffset>5</bitOffset>
              <bitWidth>1</bitWidth>
              <access>read-write</access>
              <enumeratedValues>
                <enumeratedValue>
                  <name>0</name>
                  <description>Hardware interrupts from RDRF disabled; use polling.</description>
                  <value>#0</value>
                </enumeratedValue>
                <enumeratedValue>
                  <name>1</name>
                  <description>Hardware interrupt requested when RDRF flag is 1.</description>
                  <value>#1</value>
                </enumeratedValue>
              </enumeratedValues>
            </field>
            <field>
              <name>TCIE</name>
              <description>Transmission Complete Interrupt Enable for TC</description>
              <bitOffset>6</bitOffset>
              <bitWidth>1</bitWidth>
              <access>read-write</access>
              <enumeratedValues>
                <enumeratedValue>
                  <name>0</name>
                  <description>Hardware interrupts from TC disabled; use polling.</description>
                  <value>#0</value>
                </enumeratedValue>
                <enumeratedValue>
                  <name>1</name>
                  <description>Hardware interrupt requested when TC flag is 1.</description>
                  <value>#1</value>
                </enumeratedValue>
              </enumeratedValues>
            </field>
            <field>
              <name>TIE</name>
              <description>Transmit Interrupt Enable for TDRE</description>
              <bitOffset>7</bitOffset>
              <bitWidth>1</bitWidth>
              <access>read-write</access>
              <enumeratedValues>
                <enumeratedValue>
                  <name>0</name>
                  <description>Hardware interrupts from TDRE disabled; use polling.</description>
                  <value>#0</value>
                </enumeratedValue>
                <enumeratedValue>
                  <name>1</name>
                  <description>Hardware interrupt requested when TDRE flag is 1.</description>
                  <value>#1</value>
                </enumeratedValue>
              </enumeratedValues>
            </field>
          </fields>
        </register>
        <register>
          <name>S1</name>
          <description>UART Status Register 1</description>
          <addressOffset>0x4</addressOffset>
          <size>8</size>
          <access>read-write</access>
          <resetValue>0xC0</resetValue>
          <resetMask>0xFF</resetMask>
          <fields>
            <field>
              <name>PF</name>
              <description>Parity Error Flag</description>
              <bitOffset>0</bitOffset>
              <bitWidth>1</bitWidth>
              <access>read-write</access>
              <enumeratedValues>
                <enumeratedValue>
                  <name>0</name>
                  <description>No parity error.</description>
                  <value>#0</value>
                </enumeratedValue>
                <enumeratedValue>
                  <name>1</name>
                  <description>Parity error.</description>
                  <value>#1</value>
                </enumeratedValue>
              </enumeratedValues>
            </field>
            <field>
              <name>FE</name>
              <description>Framing Error Flag</description>
              <bitOffset>1</bitOffset>
              <bitWidth>1</bitWidth>
              <access>read-write</access>
              <enumeratedValues>
                <enumeratedValue>
                  <name>0</name>
                  <description>No framing error detected. This does not guarantee the framing is correct.</description>
                  <value>#0</value>
                </enumeratedValue>
                <enumeratedValue>
                  <name>1</name>
                  <description>Framing error.</description>
                  <value>#1</value>
                </enumeratedValue>
              </enumeratedValues>
            </field>
            <field>
              <name>NF</name>
              <description>Noise Flag</description>
              <bitOffset>2</bitOffset>
              <bitWidth>1</bitWidth>
              <access>read-write</access>
              <enumeratedValues>
                <enumeratedValue>
                  <name>0</name>
                  <description>No noise detected.</description>
                  <value>#0</value>
                </enumeratedValue>
                <enumeratedValue>
                  <name>1</name>
                  <description>Noise detected in the received character in UART_D.</description>
                  <value>#1</value>
                </enumeratedValue>
              </enumeratedValues>
            </field>
            <field>
              <name>OR</name>
              <description>Receiver Overrun Flag</description>
              <bitOffset>3</bitOffset>
              <bitWidth>1</bitWidth>
              <access>read-write</access>
              <enumeratedValues>
                <enumeratedValue>
                  <name>0</name>
                  <description>No overrun.</description>
                  <value>#0</value>
                </enumeratedValue>
                <enumeratedValue>
                  <name>1</name>
                  <description>Receive overrun (new UART data lost).</description>
                  <value>#1</value>
                </enumeratedValue>
              </enumeratedValues>
            </field>
            <field>
              <name>IDLE</name>
              <description>Idle Line Flag</description>
              <bitOffset>4</bitOffset>
              <bitWidth>1</bitWidth>
              <access>read-write</access>
              <enumeratedValues>
                <enumeratedValue>
                  <name>0</name>
                  <description>No idle line detected.</description>
                  <value>#0</value>
                </enumeratedValue>
                <enumeratedValue>
                  <name>1</name>
                  <description>Idle line was detected.</description>
                  <value>#1</value>
                </enumeratedValue>
              </enumeratedValues>
            </field>
            <field>
              <name>RDRF</name>
              <description>Receive Data Register Full Flag</description>
              <bitOffset>5</bitOffset>
              <bitWidth>1</bitWidth>
              <access>read-only</access>
              <enumeratedValues>
                <enumeratedValue>
                  <name>0</name>
                  <description>Receive data buffer empty.</description>
                  <value>#0</value>
                </enumeratedValue>
                <enumeratedValue>
                  <name>1</name>
                  <description>Receive data buffer full.</description>
                  <value>#1</value>
                </enumeratedValue>
              </enumeratedValues>
            </field>
            <field>
              <name>TC</name>
              <description>Transmission Complete Flag</description>
              <bitOffset>6</bitOffset>
              <bitWidth>1</bitWidth>
              <access>read-only</access>
              <enumeratedValues>
                <enumeratedValue>
                  <name>0</name>
                  <description>Transmitter active (sending data, a preamble, or a break).</description>
                  <value>#0</value>
                </enumeratedValue>
                <enumeratedValue>
                  <name>1</name>
                  <description>Transmitter idle (transmission activity complete).</description>
                  <value>#1</value>
                </enumeratedValue>
              </enumeratedValues>
            </field>
            <field>
              <name>TDRE</name>
              <description>Transmit Data Register Empty Flag</description>
              <bitOffset>7</bitOffset>
              <bitWidth>1</bitWidth>
              <access>read-only</access>
              <enumeratedValues>
                <enumeratedValue>
                  <name>0</name>
                  <description>Transmit data buffer full.</description>
                  <value>#0</value>
                </enumeratedValue>
                <enumeratedValue>
                  <name>1</name>
                  <description>Transmit data buffer empty.</description>
                  <value>#1</value>
                </enumeratedValue>
              </enumeratedValues>
            </field>
          </fields>
        </register>
        <register>
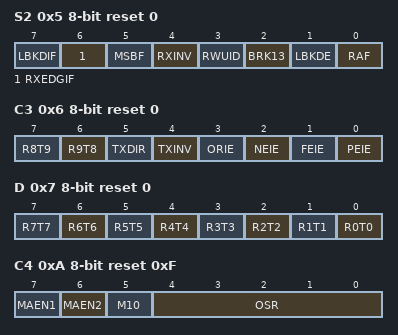
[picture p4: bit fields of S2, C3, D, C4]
          <name>S2</name>
          <description>UART Status Register 2</description>
          <addressOffset>0x5</addressOffset>
          <size>8</size>
          <access>read-write</access>
          <resetValue>0</resetValue>
          <resetMask>0xFF</resetMask>
          <fields>
            <field>
              <name>RAF</name>
              <description>Receiver Active Flag</description>
              <bitOffset>0</bitOffset>
              <bitWidth>1</bitWidth>
              <access>read-only</access>
              <enumeratedValues>
                <enumeratedValue>
                  <name>0</name>
                  <description>UART receiver idle waiting for a start bit.</description>
                  <value>#0</value>
                </enumeratedValue>
                <enumeratedValue>
                  <name>1</name>
                  <description>UART receiver active ( UART_RXD input not idle).</description>
                  <value>#1</value>
                </enumeratedValue>
              </enumeratedValues>
            </field>
            <field>
              <name>LBKDE</name>
              <description>LIN Break Detection Enable</description>
              <bitOffset>1</bitOffset>
              <bitWidth>1</bitWidth>
              <access>read-write</access>
              <enumeratedValues>
                <enumeratedValue>
                  <name>0</name>
                  <description>Break character is detected at length 10 bit times (if M = 0, SBNS = 0) or 11 (if M = 1, SBNS = 0 or M = 0, SBNS = 1) or 12 (if M = 1, SBNS = 1 or M10 = 1, SNBS = 0) or 13 (if M10 = 1, SNBS = 1).</description>
                  <value>#0</value>
                </enumeratedValue>
                <enumeratedValue>
                  <name>1</name>
                  <description>Break character is detected at length of 11 bit times (if M = 0, SBNS = 0) or 12 (if M = 1, SBNS = 0 or M = 0, SBNS = 1) or 14 (if M = 1, SBNS = 1 or M10 = 1, SNBS = 0) or 15 (if M10 = 1, SNBS = 1).</description>
                  <value>#1</value>
                </enumeratedValue>
              </enumeratedValues>
            </field>
            <field>
              <name>BRK13</name>
              <description>Break Character Generation Length</description>
              <bitOffset>2</bitOffset>
              <bitWidth>1</bitWidth>
              <access>read-write</access>
              <enumeratedValues>
                <enumeratedValue>
                  <name>0</name>
                  <description>Break character is transmitted with length of 10 bit times (if M = 0, SBNS = 0) or 11 (if M = 1, SBNS = 0 or M = 0, SBNS = 1) or 12 (if M = 1, SBNS = 1 or M10 = 1, SNBS = 0) or 13 (if M10 = 1, SNBS = 1).</description>
                  <value>#0</value>
                </enumeratedValue>
                <enumeratedValue>
                  <name>1</name>
                  <description>Break character is transmitted with length of 13 bit times (if M = 0, SBNS = 0) or 14 (if M = 1, SBNS = 0 or M = 0, SBNS = 1) or 15 (if M = 1, SBNS = 1 or M10 = 1, SNBS = 0) or 16 (if M10 = 1, SNBS = 1).</description>
                  <value>#1</value>
                </enumeratedValue>
              </enumeratedValues>
            </field>
            <field>
              <name>RWUID</name>
              <description>Receive Wake Up Idle Detect</description>
              <bitOffset>3</bitOffset>
              <bitWidth>1</bitWidth>
              <access>read-write</access>
              <enumeratedValues>
                <enumeratedValue>
                  <name>0</name>
                  <description>During receive standby state (RWU = 1), the IDLE bit does not get set upon detection of an idle character.</description>
                  <value>#0</value>
                </enumeratedValue>
                <enumeratedValue>
                  <name>1</name>
                  <description>During receive standby state (RWU = 1), the IDLE bit gets set upon detection of an idle character.</description>
                  <value>#1</value>
                </enumeratedValue>
              </enumeratedValues>
            </field>
            <field>
              <name>RXINV</name>
              <description>Receive Data Inversion</description>
              <bitOffset>4</bitOffset>
              <bitWidth>1</bitWidth>
              <access>read-write</access>
              <enumeratedValues>
                <enumeratedValue>
                  <name>0</name>
                  <description>Receive data not inverted.</description>
                  <value>#0</value>
                </enumeratedValue>
                <enumeratedValue>
                  <name>1</name>
                  <description>Receive data inverted.</description>
                  <value>#1</value>
                </enumeratedValue>
              </enumeratedValues>
            </field>
            <field>
              <name>MSBF</name>
              <description>MSB First</description>
              <bitOffset>5</bitOffset>
              <bitWidth>1</bitWidth>
              <access>read-write</access>
              <enumeratedValues>
                <enumeratedValue>
                  <name>0</name>
                  <description>LSB (bit0) is the first bit that is transmitted following the start bit. Further, the first bit received after the start bit is identified as bit0.</description>
                  <value>#0</value>
                </enumeratedValue>
                <enumeratedValue>
                  <name>1</name>
                  <description>MSB (bit9, bit8, bit7 or bit6) is the first bit that is transmitted following the start bit depending on the setting of C1[M], C1[PE] and C4[M10]. Further, the first bit received after the start bit is identified as bit9, bit8, bit7 or bit6 depending on the setting of C1[M] and C1[PE].</description>
                  <value>#1</value>
                </enumeratedValue>
              </enumeratedValues>
            </field>
            <field>
              <name>RXEDGIF</name>
              <description>UART_RX Pin Active Edge Interrupt Flag</description>
              <bitOffset>6</bitOffset>
              <bitWidth>1</bitWidth>
              <access>read-write</access>
              <enumeratedValues>
                <enumeratedValue>
                  <name>0</name>
                  <description>No active edge on the receive pin has occurred.</description>
                  <value>#0</value>
                </enumeratedValue>
                <enumeratedValue>
                  <name>1</name>
                  <description>An active edge on the receive pin has occurred.</description>
                  <value>#1</value>
                </enumeratedValue>
              </enumeratedValues>
            </field>
            <field>
              <name>LBKDIF</name>
              <description>LIN Break Detect Interrupt Flag</description>
              <bitOffset>7</bitOffset>
              <bitWidth>1</bitWidth>
              <access>read-write</access>
              <enumeratedValues>
                <enumeratedValue>
                  <name>0</name>
                  <description>No LIN break character has been detected.</description>
                  <value>#0</value>
                </enumeratedValue>
                <enumeratedValue>
                  <name>1</name>
                  <description>LIN break character has been detected.</description>
                  <value>#1</value>
                </enumeratedValue>
              </enumeratedValues>
            </field>
          </fields>
        </register>
        <register>
          <name>C3</name>
          <description>UART Control Register 3</description>
          <addressOffset>0x6</addressOffset>
          <size>8</size>
          <access>read-write</access>
          <resetValue>0</resetValue>
          <resetMask>0xFF</resetMask>
          <fields>
            <field>
              <name>PEIE</name>
              <description>Parity Error Interrupt Enable</description>
              <bitOffset>0</bitOffset>
              <bitWidth>1</bitWidth>
              <access>read-write</access>
              <enumeratedValues>
                <enumeratedValue>
                  <name>0</name>
                  <description>PF interrupts disabled; use polling).</description>
                  <value>#0</value>
                </enumeratedValue>
                <enumeratedValue>
                  <name>1</name>
                  <description>Hardware interrupt requested when PF is set.</description>
                  <value>#1</value>
                </enumeratedValue>
              </enumeratedValues>
            </field>
            <field>
              <name>FEIE</name>
              <description>Framing Error Interrupt Enable</description>
              <bitOffset>1</bitOffset>
              <bitWidth>1</bitWidth>
              <access>read-write</access>
              <enumeratedValues>
                <enumeratedValue>
                  <name>0</name>
                  <description>FE interrupts disabled; use polling.</description>
                  <value>#0</value>
                </enumeratedValue>
                <enumeratedValue>
                  <name>1</name>
                  <description>Hardware interrupt requested when FE is set.</description>
                  <value>#1</value>
                </enumeratedValue>
              </enumeratedValues>
            </field>
            <field>
              <name>NEIE</name>
              <description>Noise Error Interrupt Enable</description>
              <bitOffset>2</bitOffset>
              <bitWidth>1</bitWidth>
              <access>read-write</access>
              <enumeratedValues>
                <enumeratedValue>
                  <name>0</name>
                  <description>NF interrupts disabled; use polling.</description>
                  <value>#0</value>
                </enumeratedValue>
                <enumeratedValue>
                  <name>1</name>
                  <description>Hardware interrupt requested when NF is set.</description>
                  <value>#1</value>
                </enumeratedValue>
              </enumeratedValues>
            </field>
            <field>
              <name>ORIE</name>
              <description>Overrun Interrupt Enable</description>
              <bitOffset>3</bitOffset>
              <bitWidth>1</bitWidth>
              <access>read-write</access>
              <enumeratedValues>
                <enumeratedValue>
                  <name>0</name>
                  <description>OR interrupts disabled; use polling.</description>
                  <value>#0</value>
                </enumeratedValue>
                <enumeratedValue>
                  <name>1</name>
                  <description>Hardware interrupt requested when OR is set.</description>
                  <value>#1</value>
                </enumeratedValue>
              </enumeratedValues>
            </field>
            <field>
              <name>TXINV</name>
              <description>Transmit Data Inversion</description>
              <bitOffset>4</bitOffset>
              <bitWidth>1</bitWidth>
              <access>read-write</access>
              <enumeratedValues>
                <enumeratedValue>
                  <name>0</name>
                  <description>Transmit data not inverted.</description>
                  <value>#0</value>
                </enumeratedValue>
                <enumeratedValue>
                  <name>1</name>
                  <description>Transmit data inverted.</description>
                  <value>#1</value>
                </enumeratedValue>
              </enumeratedValues>
            </field>
            <field>
              <name>TXDIR</name>
              <description>UART_TX Pin Direction in Single-Wire Mode</description>
              <bitOffset>5</bitOffset>
              <bitWidth>1</bitWidth>
              <access>read-write</access>
              <enumeratedValues>
                <enumeratedValue>
                  <name>0</name>
                  <description>UART_TXD pin is an input in single-wire mode.</description>
                  <value>#0</value>
                </enumeratedValue>
                <enumeratedValue>
                  <name>1</name>
                  <description>UART_TXD pin is an output in single-wire mode.</description>
                  <value>#1</value>
                </enumeratedValue>
              </enumeratedValues>
            </field>
            <field>
              <name>R9T8</name>
              <description>Receive Bit 9 / Transmit Bit 8</description>
              <bitOffset>6</bitOffset>
              <bitWidth>1</bitWidth>
              <access>read-write</access>
            </field>
            <field>
              <name>R8T9</name>
              <description>Receive Bit 8 / Transmit Bit 9</description>
              <bitOffset>7</bitOffset>
              <bitWidth>1</bitWidth>
              <access>read-write</access>
            </field>
          </fields>
        </register>
        <register>
          <name>D</name>
          <description>UART Data Register</description>
          <addressOffset>0x7</addressOffset>
          <size>8</size>
          <access>read-write</access>
          <resetValue>0</resetValue>
          <resetMask>0xFF</resetMask>
          <fields>
            <field>
              <name>R0T0</name>
              <description>Read receive data buffer 0 or write transmit data buffer 0.</description>
              <bitOffset>0</bitOffset>
              <bitWidth>1</bitWidth>
              <access>read-write</access>
            </field>
            <field>
              <name>R1T1</name>
              <description>Read receive data buffer 1 or write transmit data buffer 1.</description>
              <bitOffset>1</bitOffset>
              <bitWidth>1</bitWidth>
              <access>read-write</access>
            </field>
            <field>
              <name>R2T2</name>
              <description>Read receive data buffer 2 or write transmit data buffer 2.</description>
              <bitOffset>2</bitOffset>
              <bitWidth>1</bitWidth>
              <access>read-write</access>
            </field>
            <field>
              <name>R3T3</name>
              <description>Read receive data buffer 3 or write transmit data buffer 3.</description>
              <bitOffset>3</bitOffset>
              <bitWidth>1</bitWidth>
              <access>read-write</access>
            </field>
            <field>
              <name>R4T4</name>
              <description>Read receive data buffer 4 or write transmit data buffer 4.</description>
              <bitOffset>4</bitOffset>
              <bitWidth>1</bitWidth>
              <access>read-write</access>
            </field>
            <field>
              <name>R5T5</name>
              <description>Read receive data buffer 5 or write transmit data buffer 5.</description>
              <bitOffset>5</bitOffset>
              <bitWidth>1</bitWidth>
              <access>read-write</access>
            </field>
            <field>
              <name>R6T6</name>
              <description>Read receive data buffer 6 or write transmit data buffer 6.</description>
              <bitOffset>6</bitOffset>
              <bitWidth>1</bitWidth>
              <access>read-write</access>
            </field>
            <field>
              <name>R7T7</name>
              <description>Read receive data buffer 7 or write transmit data buffer 7.</description>
              <bitOffset>7</bitOffset>
              <bitWidth>1</bitWidth>
              <access>read-write</access>
            </field>
          </fields>
        </register>
        <register>
          <name>MA1</name>
          <description>UART Match Address Registers 1</description>
          <addressOffset>0x8</addressOffset>
          <size>8</size>
          <access>read-write</access>
          <resetValue>0</resetValue>
          <resetMask>0xFF</resetMask>
          <fields>
            <field>
              <name>MA</name>
              <description>Match Address</description>
              <bitOffset>0</bitOffset>
              <bitWidth>8</bitWidth>
              <access>read-write</access>
            </field>
          </fields>
        </register>
        <register>
          <name>MA2</name>
          <description>UART Match Address Registers 2</description>
          <addressOffset>0x9</addressOffset>
          <size>8</size>
          <access>read-write</access>
          <resetValue>0</resetValue>
          <resetMask>0xFF</resetMask>
          <fields>
            <field>
              <name>MA</name>
              <description>Match Address</description>
              <bitOffset>0</bitOffset>
              <bitWidth>8</bitWidth>
              <access>read-write</access>
            </field>
          </fields>
        </register>
        <register>
          <name>C4</name>
          <description>UART Control Register 4</description>
          <addressOffset>0xA</addressOffset>
          <size>8</size>
          <access>read-write</access>
          <resetValue>0xF</resetValue>
          <resetMask>0xFF</resetMask>
          <fields>
            <field>
              <name>OSR</name>
              <description>Over Sampling Ratio</description>
              <bitOffset>0</bitOffset>
              <bitWidth>5</bitWidth>
              <access>read-write</access>
            </field>
            <field>
              <name>M10</name>
              <description>10-bit Mode select</description>
              <bitOffset>5</bitOffset>
              <bitWidth>1</bitWidth>
              <access>read-write</access>
              <enumeratedValues>
                <enumeratedValue>
                  <name>0</name>
                  <description>Receiver and transmitter use 8-bit or 9-bit data characters.</description>
                  <value>#0</value>
                </enumeratedValue>
                <enumeratedValue>
                  <name>1</name>
                  <description>Receiver and transmitter use 10-bit data characters.</description>
                  <value>#1</value>
                </enumeratedValue>
              </enumeratedValues>
            </field>
            <field>
              <name>MAEN2</name>
              <description>Match Address Mode Enable 2</description>
              <bitOffset>6</bitOffset>
              <bitWidth>1</bitWidth>
              <access>read-write</access>
              <enumeratedValues>
                <enumeratedValue>
                  <name>0</name>
                  <description>All data received is transferred to the data buffer if MAEN1 is cleared.</description>
                  <value>#0</value>
                </enumeratedValue>
                <enumeratedValue>
                  <name>1</name>
                  <description>All data received with the most significant bit cleared, is discarded. All data received with the most significant bit set, is compared with contents of MA2 register. If no match occurs, the data is discarded. If match occurs, data is transferred to the data buffer.</description>
                  <value>#1</value>
                </enumeratedValue>
              </enumeratedValues>
            </field>
            <field>
              <name>MAEN1</name>
              <description>Match Address Mode Enable 1</description>
              <bitOffset>7</bitOffset>
              <bitWidth>1</bitWidth>
              <access>read-write</access>
              <enumeratedValues>
                <enumeratedValue>
                  <name>0</name>
                  <description>All data received is transferred to the data buffer if MAEN2 is cleared.</description>
                  <value>#0</value>
                </enumeratedValue>
                <enumeratedValue>
                  <name>1</name>
                  <description>All data received with the most significant bit cleared, is discarded. All data received with the most significant bit set, is compared with contents of MA1 register. If no match occurs, the data is discarded. If match occurs, data is transferred to the data buffer.</description>
                  <value>#1</value>
                </enumeratedValue>
              </enumeratedValues>
            </field>
          </fields>
        </register>
        <register>
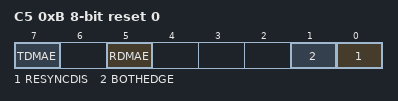
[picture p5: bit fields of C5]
          <name>C5</name>
          <description>UART Control Register 5</description>
          <addressOffset>0xB</addressOffset>
          <size>8</size>
          <access>read-write</access>
          <resetValue>0</resetValue>
          <resetMask>0xFF</resetMask>
          <fields>
            <field>
              <name>RESYNCDIS</name>
              <description>Resynchronization Disable</description>
              <bitOffset>0</bitOffset>
              <bitWidth>1</bitWidth>
              <access>read-write</access>
              <enumeratedValues>
                <enumeratedValue>
                  <name>0</name>
                  <description>Resynchronization during received data word is supported</description>
                  <value>#0</value>
                </enumeratedValue>
                <enumeratedValue>
                  <name>1</name>
                  <description>Resynchronization during received data word is disabled</description>
                  <value>#1</value>
                </enumeratedValue>
              </enumeratedValues>
            </field>
            <field>
              <name>BOTHEDGE</name>
              <description>Both Edge Sampling</description>
              <bitOffset>1</bitOffset>
              <bitWidth>1</bitWidth>
              <access>read-write</access>
              <enumeratedValues>
                <enumeratedValue>
                  <name>0</name>
                  <description>Receiver samples input data using the rising edge of the baud rate clock.</description>
                  <value>#0</value>
                </enumeratedValue>
                <enumeratedValue>
                  <name>1</name>
                  <description>Receiver samples input data using the rising and falling edge of the baud rate clock.</description>
                  <value>#1</value>
                </enumeratedValue>
              </enumeratedValues>
            </field>
            <field>
              <name>RDMAE</name>
              <description>Receiver Full DMA Enable</description>
              <bitOffset>5</bitOffset>
              <bitWidth>1</bitWidth>
              <access>read-write</access>
              <enumeratedValues>
                <enumeratedValue>
                  <name>0</name>
                  <description>DMA request disabled.</description>
                  <value>#0</value>
                </enumeratedValue>
                <enumeratedValue>
                  <name>1</name>
                  <description>DMA request enabled.</description>
                  <value>#1</value>
                </enumeratedValue>
              </enumeratedValues>
            </field>
            <field>
              <name>TDMAE</name>
              <description>Transmitter DMA Enable</description>
              <bitOffset>7</bitOffset>
              <bitWidth>1</bitWidth>
              <access>read-write</access>
              <enumeratedValues>
                <enumeratedValue>
                  <name>0</name>
                  <description>DMA request disabled.</description>
                  <value>#0</value>
                </enumeratedValue>
                <enumeratedValue>
                  <name>1</name>
                  <description>DMA request enabled.</description>
                  <value>#1</value>
                </enumeratedValue>
              </enumeratedValues>
            </field>
          </fields>
        </register>
      </registers>
    </peripheral>
    <peripheral>
      <name>UART1</name>
      <description>Universal Asynchronous Receiver/Transmitter (UART)</description>
      <groupName>UART</groupName>
      <prependToName>UART1_</prependToName>
      <baseAddress>0x4006B000</baseAddress>
      <addressBlock>
        <offset>0</offset>
        <size>0x9</size>
        <usage>registers</usage>
      </addressBlock>
      <interrupt>
        <name>UART1</name>
        <value>13</value>
      </interrupt>
      <registers>
        <register>
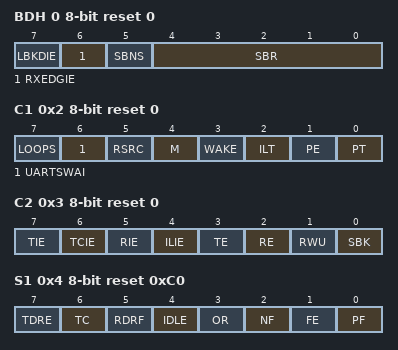
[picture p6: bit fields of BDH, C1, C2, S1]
          <name>BDH</name>
          <description>UART Baud Rate Register: High</description>
          <addressOffset>0</addressOffset>
          <size>8</size>
          <access>read-write</access>
          <resetValue>0</resetValue>
          <resetMask>0xFF</resetMask>
          <fields>
            <field>
              <name>SBR</name>
              <description>Baud Rate Modulo Divisor.</description>
              <bitOffset>0</bitOffset>
              <bitWidth>5</bitWidth>
              <access>read-write</access>
            </field>
            <field>
              <name>SBNS</name>
              <description>Stop Bit Number Select</description>
              <bitOffset>5</bitOffset>
              <bitWidth>1</bitWidth>
              <access>read-write</access>
              <enumeratedValues>
                <enumeratedValue>
                  <name>0</name>
                  <description>One stop bit.</description>
                  <value>#0</value>
                </enumeratedValue>
                <enumeratedValue>
                  <name>1</name>
                  <description>Two stop bit.</description>
                  <value>#1</value>
                </enumeratedValue>
              </enumeratedValues>
            </field>
            <field>
              <name>RXEDGIE</name>
              <description>RxD Input Active Edge Interrupt Enable (for RXEDGIF)</description>
              <bitOffset>6</bitOffset>
              <bitWidth>1</bitWidth>
              <access>read-write</access>
              <enumeratedValues>
                <enumeratedValue>
                  <name>0</name>
                  <description>Hardware interrupts from UART_S2[RXEDGIF] disabled (use polling).</description>
                  <value>#0</value>
                </enumeratedValue>
                <enumeratedValue>
                  <name>1</name>
                  <description>Hardware interrupt requested when UART_S2[RXEDGIF] flag is 1.</description>
                  <value>#1</value>
                </enumeratedValue>
              </enumeratedValues>
            </field>
            <field>
              <name>LBKDIE</name>
              <description>LIN Break Detect Interrupt Enable (for LBKDIF)</description>
              <bitOffset>7</bitOffset>
              <bitWidth>1</bitWidth>
              <access>read-write</access>
              <enumeratedValues>
                <enumeratedValue>
                  <name>0</name>
                  <description>Hardware interrupts from UART_S2[LBKDIF] disabled (use polling).</description>
                  <value>#0</value>
                </enumeratedValue>
                <enumeratedValue>
                  <name>1</name>
                  <description>Hardware interrupt requested when UART_S2[LBKDIF] flag is 1.</description>
                  <value>#1</value>
                </enumeratedValue>
              </enumeratedValues>
            </field>
          </fields>
        </register>
        <register>
          <name>BDL</name>
          <description>UART Baud Rate Register: Low</description>
          <addressOffset>0x1</addressOffset>
          <size>8</size>
          <access>read-write</access>
          <resetValue>0x4</resetValue>
          <resetMask>0xFF</resetMask>
          <fields>
            <field>
              <name>SBR</name>
              <description>Baud Rate Modulo Divisor</description>
              <bitOffset>0</bitOffset>
              <bitWidth>8</bitWidth>
              <access>read-write</access>
            </field>
          </fields>
        </register>
        <register>
          <name>C1</name>
          <description>UART Control Register 1</description>
          <addressOffset>0x2</addressOffset>
          <size>8</size>
          <access>read-write</access>
          <resetValue>0</resetValue>
          <resetMask>0xFF</resetMask>
          <fields>
            <field>
              <name>PT</name>
              <description>Parity Type</description>
              <bitOffset>0</bitOffset>
              <bitWidth>1</bitWidth>
              <access>read-write</access>
              <enumeratedValues>
                <enumeratedValue>
                  <name>0</name>
                  <description>Even parity.</description>
                  <value>#0</value>
                </enumeratedValue>
                <enumeratedValue>
                  <name>1</name>
                  <description>Odd parity.</description>
                  <value>#1</value>
                </enumeratedValue>
              </enumeratedValues>
            </field>
            <field>
              <name>PE</name>
              <description>Parity Enable</description>
              <bitOffset>1</bitOffset>
              <bitWidth>1</bitWidth>
              <access>read-write</access>
              <enumeratedValues>
                <enumeratedValue>
                  <name>0</name>
                  <description>No hardware parity generation or checking.</description>
                  <value>#0</value>
                </enumeratedValue>
                <enumeratedValue>
                  <name>1</name>
                  <description>Parity enabled.</description>
                  <value>#1</value>
                </enumeratedValue>
              </enumeratedValues>
            </field>
            <field>
              <name>ILT</name>
              <description>Idle Line Type Select</description>
              <bitOffset>2</bitOffset>
              <bitWidth>1</bitWidth>
              <access>read-write</access>
              <enumeratedValues>
                <enumeratedValue>
                  <name>0</name>
                  <description>Idle character bit count starts after start bit.</description>
                  <value>#0</value>
                </enumeratedValue>
                <enumeratedValue>
                  <name>1</name>
                  <description>Idle character bit count starts after stop bit.</description>
                  <value>#1</value>
                </enumeratedValue>
              </enumeratedValues>
            </field>
            <field>
              <name>WAKE</name>
              <description>Receiver Wakeup Method Select</description>
              <bitOffset>3</bitOffset>
              <bitWidth>1</bitWidth>
              <access>read-write</access>
              <enumeratedValues>
                <enumeratedValue>
                  <name>0</name>
                  <description>Idle-line wake-up.</description>
                  <value>#0</value>
                </enumeratedValue>
                <enumeratedValue>
                  <name>1</name>
                  <description>Address-mark wake-up.</description>
                  <value>#1</value>
                </enumeratedValue>
              </enumeratedValues>
            </field>
            <field>
              <name>M</name>
              <description>9-Bit or 8-Bit Mode Select</description>
              <bitOffset>4</bitOffset>
              <bitWidth>1</bitWidth>
              <access>read-write</access>
              <enumeratedValues>
                <enumeratedValue>
                  <name>0</name>
                  <description>Normal - start + 8 data bits (lsb first) + stop.</description>
                  <value>#0</value>
                </enumeratedValue>
                <enumeratedValue>
                  <name>1</name>
                  <description>Receiver and transmitter use 9-bit data characters start + 8 data bits (lsb first) + 9th data bit + stop.</description>
                  <value>#1</value>
                </enumeratedValue>
              </enumeratedValues>
            </field>
            <field>
              <name>RSRC</name>
              <description>Receiver Source Select</description>
              <bitOffset>5</bitOffset>
              <bitWidth>1</bitWidth>
              <access>read-write</access>
              <enumeratedValues>
                <enumeratedValue>
                  <name>0</name>
                  <description>Provided LOOPS is set, RSRC is cleared, selects internal loop back mode and the UART does not use the RxD pins.</description>
                  <value>#0</value>
                </enumeratedValue>
                <enumeratedValue>
                  <name>1</name>
                  <description>Single-wire UART mode where the TxD pin is connected to the transmitter output and receiver input.</description>
                  <value>#1</value>
                </enumeratedValue>
              </enumeratedValues>
            </field>
            <field>
              <name>UARTSWAI</name>
              <description>UART Stops in Wait Mode</description>
              <bitOffset>6</bitOffset>
              <bitWidth>1</bitWidth>
              <access>read-write</access>
              <enumeratedValues>
                <enumeratedValue>
                  <name>0</name>
                  <description>UART clocks continue to run in Wait mode so the UART can be the source of an interrupt that wakes up the CPU.</description>
                  <value>#0</value>
                </enumeratedValue>
                <enumeratedValue>
                  <name>1</name>
                  <description>UART clocks freeze while CPU is in Wait mode.</description>
                  <value>#1</value>
                </enumeratedValue>
              </enumeratedValues>
            </field>
            <field>
              <name>LOOPS</name>
              <description>Loop Mode Select</description>
              <bitOffset>7</bitOffset>
              <bitWidth>1</bitWidth>
              <access>read-write</access>
              <enumeratedValues>
                <enumeratedValue>
                  <name>0</name>
                  <description>Normal operation - RxD and TxD use separate pins.</description>
                  <value>#0</value>
                </enumeratedValue>
                <enumeratedValue>
                  <name>1</name>
                  <description>Loop mode or single-wire mode where transmitter outputs are internally connected to receiver input. (See RSRC bit.) RxD pin is not used by UART.</description>
                  <value>#1</value>
                </enumeratedValue>
              </enumeratedValues>
            </field>
          </fields>
        </register>
        <register>
          <name>C2</name>
          <description>UART Control Register 2</description>
          <addressOffset>0x3</addressOffset>
          <size>8</size>
          <access>read-write</access>
          <resetValue>0</resetValue>
          <resetMask>0xFF</resetMask>
          <fields>
            <field>
              <name>SBK</name>
              <description>Send Break</description>
              <bitOffset>0</bitOffset>
              <bitWidth>1</bitWidth>
              <access>read-write</access>
              <enumeratedValues>
                <enumeratedValue>
                  <name>0</name>
                  <description>Normal transmitter operation.</description>
                  <value>#0</value>
                </enumeratedValue>
                <enumeratedValue>
                  <name>1</name>
                  <description>Queue break character(s) to be sent.</description>
                  <value>#1</value>
                </enumeratedValue>
              </enumeratedValues>
            </field>
            <field>
              <name>RWU</name>
              <description>Receiver Wakeup Control</description>
              <bitOffset>1</bitOffset>
              <bitWidth>1</bitWidth>
              <access>read-write</access>
              <enumeratedValues>
                <enumeratedValue>
                  <name>0</name>
                  <description>Normal UART receiver operation.</description>
                  <value>#0</value>
                </enumeratedValue>
                <enumeratedValue>
                  <name>1</name>
                  <description>UART receiver in standby waiting for wake-up condition.</description>
                  <value>#1</value>
                </enumeratedValue>
              </enumeratedValues>
            </field>
            <field>
              <name>RE</name>
              <description>Receiver Enable</description>
              <bitOffset>2</bitOffset>
              <bitWidth>1</bitWidth>
              <access>read-write</access>
              <enumeratedValues>
                <enumeratedValue>
                  <name>0</name>
                  <description>Receiver off.</description>
                  <value>#0</value>
                </enumeratedValue>
                <enumeratedValue>
                  <name>1</name>
                  <description>Receiver on.</description>
                  <value>#1</value>
                </enumeratedValue>
              </enumeratedValues>
            </field>
            <field>
              <name>TE</name>
              <description>Transmitter Enable</description>
              <bitOffset>3</bitOffset>
              <bitWidth>1</bitWidth>
              <access>read-write</access>
              <enumeratedValues>
                <enumeratedValue>
                  <name>0</name>
                  <description>Transmitter off.</description>
                  <value>#0</value>
                </enumeratedValue>
                <enumeratedValue>
                  <name>1</name>
                  <description>Transmitter on.</description>
                  <value>#1</value>
                </enumeratedValue>
              </enumeratedValues>
            </field>
            <field>
              <name>ILIE</name>
              <description>Idle Line Interrupt Enable for IDLE</description>
              <bitOffset>4</bitOffset>
              <bitWidth>1</bitWidth>
              <access>read-write</access>
              <enumeratedValues>
                <enumeratedValue>
                  <name>0</name>
                  <description>Hardware interrupts from S1[IDLE] disabled; use polling.</description>
                  <value>#0</value>
                </enumeratedValue>
                <enumeratedValue>
                  <name>1</name>
                  <description>Hardware interrupt requested when S1[IDLE] flag is 1.</description>
                  <value>#1</value>
                </enumeratedValue>
              </enumeratedValues>
            </field>
            <field>
              <name>RIE</name>
              <description>Receiver Interrupt Enable for RDRF</description>
              <bitOffset>5</bitOffset>
              <bitWidth>1</bitWidth>
              <access>read-write</access>
              <enumeratedValues>
                <enumeratedValue>
                  <name>0</name>
                  <description>Hardware interrupts from S1[RDRF] disabled; use polling.</description>
                  <value>#0</value>
                </enumeratedValue>
                <enumeratedValue>
                  <name>1</name>
                  <description>Hardware interrupt requested when S1[RDRF] flag is 1.</description>
                  <value>#1</value>
                </enumeratedValue>
              </enumeratedValues>
            </field>
            <field>
              <name>TCIE</name>
              <description>Transmission Complete Interrupt Enable for TC</description>
              <bitOffset>6</bitOffset>
              <bitWidth>1</bitWidth>
              <access>read-write</access>
              <enumeratedValues>
                <enumeratedValue>
                  <name>0</name>
                  <description>Hardware interrupts from TC disabled; use polling.</description>
                  <value>#0</value>
                </enumeratedValue>
                <enumeratedValue>
                  <name>1</name>
                  <description>Hardware interrupt requested when TC flag is 1.</description>
                  <value>#1</value>
                </enumeratedValue>
              </enumeratedValues>
            </field>
            <field>
              <name>TIE</name>
              <description>Transmit Interrupt Enable for TDRE</description>
              <bitOffset>7</bitOffset>
              <bitWidth>1</bitWidth>
              <access>read-write</access>
              <enumeratedValues>
                <enumeratedValue>
                  <name>0</name>
                  <description>Hardware interrupts from TDRE disabled; use polling.</description>
                  <value>#0</value>
                </enumeratedValue>
                <enumeratedValue>
                  <name>1</name>
                  <description>Hardware interrupt requested when TDRE flag is 1.</description>
                  <value>#1</value>
                </enumeratedValue>
              </enumeratedValues>
            </field>
          </fields>
        </register>
        <register>
          <name>S1</name>
          <description>UART Status Register 1</description>
          <addressOffset>0x4</addressOffset>
          <size>8</size>
          <access>read-only</access>
          <resetValue>0xC0</resetValue>
          <resetMask>0xFF</resetMask>
          <fields>
            <field>
              <name>PF</name>
              <description>Parity Error Flag</description>
              <bitOffset>0</bitOffset>
              <bitWidth>1</bitWidth>
              <access>read-only</access>
              <enumeratedValues>
                <enumeratedValue>
                  <name>0</name>
                  <description>No parity error.</description>
                  <value>#0</value>
                </enumeratedValue>
                <enumeratedValue>
                  <name>1</name>
                  <description>Parity error.</description>
                  <value>#1</value>
                </enumeratedValue>
              </enumeratedValues>
            </field>
            <field>
              <name>FE</name>
              <description>Framing Error Flag</description>
              <bitOffset>1</bitOffset>
              <bitWidth>1</bitWidth>
              <access>read-only</access>
              <enumeratedValues>
                <enumeratedValue>
                  <name>0</name>
                  <description>No framing error detected. This does not guarantee the framing is correct.</description>
                  <value>#0</value>
                </enumeratedValue>
                <enumeratedValue>
                  <name>1</name>
                  <description>Framing error.</description>
                  <value>#1</value>
                </enumeratedValue>
              </enumeratedValues>
            </field>
            <field>
              <name>NF</name>
              <description>Noise Flag</description>
              <bitOffset>2</bitOffset>
              <bitWidth>1</bitWidth>
              <access>read-only</access>
              <enumeratedValues>
                <enumeratedValue>
                  <name>0</name>
                  <description>No noise detected.</description>
                  <value>#0</value>
                </enumeratedValue>
                <enumeratedValue>
                  <name>1</name>
                  <description>Noise detected in the received character in UART_D.</description>
                  <value>#1</value>
                </enumeratedValue>
              </enumeratedValues>
            </field>
            <field>
              <name>OR</name>
              <description>Receiver Overrun Flag</description>
              <bitOffset>3</bitOffset>
              <bitWidth>1</bitWidth>
              <access>read-only</access>
              <enumeratedValues>
                <enumeratedValue>
                  <name>0</name>
                  <description>No overrun.</description>
                  <value>#0</value>
                </enumeratedValue>
                <enumeratedValue>
                  <name>1</name>
                  <description>Receive overrun (new UART data lost).</description>
                  <value>#1</value>
                </enumeratedValue>
              </enumeratedValues>
            </field>
            <field>
              <name>IDLE</name>
              <description>Idle Line Flag</description>
              <bitOffset>4</bitOffset>
              <bitWidth>1</bitWidth>
              <access>read-only</access>
              <enumeratedValues>
                <enumeratedValue>
                  <name>0</name>
                  <description>No idle line detected.</description>
                  <value>#0</value>
                </enumeratedValue>
                <enumeratedValue>
                  <name>1</name>
                  <description>Idle line was detected.</description>
                  <value>#1</value>
                </enumeratedValue>
              </enumeratedValues>
            </field>
            <field>
              <name>RDRF</name>
              <description>Receive Data Register Full Flag</description>
              <bitOffset>5</bitOffset>
              <bitWidth>1</bitWidth>
              <access>read-only</access>
              <enumeratedValues>
                <enumeratedValue>
                  <name>0</name>
                  <description>Receive data register empty.</description>
                  <value>#0</value>
                </enumeratedValue>
                <enumeratedValue>
                  <name>1</name>
                  <description>Receive data register full.</description>
                  <value>#1</value>
                </enumeratedValue>
              </enumeratedValues>
            </field>
            <field>
              <name>TC</name>
              <description>Transmission Complete Flag</description>
              <bitOffset>6</bitOffset>
              <bitWidth>1</bitWidth>
              <access>read-only</access>
              <enumeratedValues>
                <enumeratedValue>
                  <name>0</name>
                  <description>Transmitter active (sending data, a preamble, or a break).</description>
                  <value>#0</value>
                </enumeratedValue>
                <enumeratedValue>
                  <name>1</name>
                  <description>Transmitter idle (transmission activity complete).</description>
                  <value>#1</value>
                </enumeratedValue>
              </enumeratedValues>
            </field>
            <field>
              <name>TDRE</name>
              <description>Transmit Data Register Empty Flag</description>
              <bitOffset>7</bitOffset>
              <bitWidth>1</bitWidth>
              <access>read-only</access>
              <enumeratedValues>
                <enumeratedValue>
                  <name>0</name>
                  <description>Transmit data register (buffer) full.</description>
                  <value>#0</value>
                </enumeratedValue>
                <enumeratedValue>
                  <name>1</name>
                  <description>Transmit data register (buffer) empty.</description>
                  <value>#1</value>
                </enumeratedValue>
              </enumeratedValues>
            </field>
          </fields>
        </register>
        <register>
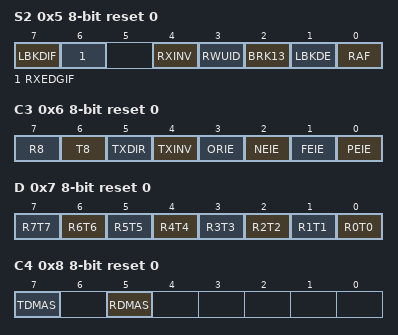
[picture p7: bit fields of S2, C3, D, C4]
          <name>S2</name>
          <description>UART Status Register 2</description>
          <addressOffset>0x5</addressOffset>
          <size>8</size>
          <access>read-write</access>
          <resetValue>0</resetValue>
          <resetMask>0xFF</resetMask>
          <fields>
            <field>
              <name>RAF</name>
              <description>Receiver Active Flag</description>
              <bitOffset>0</bitOffset>
              <bitWidth>1</bitWidth>
              <access>read-only</access>
              <enumeratedValues>
                <enumeratedValue>
                  <name>0</name>
                  <description>UART receiver idle waiting for a start bit.</description>
                  <value>#0</value>
                </enumeratedValue>
                <enumeratedValue>
                  <name>1</name>
                  <description>UART receiver active (RxD input not idle).</description>
                  <value>#1</value>
                </enumeratedValue>
              </enumeratedValues>
            </field>
            <field>
              <name>LBKDE</name>
              <description>LIN Break Detection Enable</description>
              <bitOffset>1</bitOffset>
              <bitWidth>1</bitWidth>
              <access>read-write</access>
              <enumeratedValues>
                <enumeratedValue>
                  <name>0</name>
                  <description>Break detection is disabled.</description>
                  <value>#0</value>
                </enumeratedValue>
                <enumeratedValue>
                  <name>1</name>
                  <description>Break detection is enabled (Break character is detected at length 11 bit times (if C1[M] = 0, BDH[SBNS] = 0) or 12 (if C1[M] = 1, BDH[SBNS] = 0 or C1[M] = 0, BDH[SBNS] = 1) or 13 (if C1[M] = 1, BDH[SBNS] = 1)).</description>
                  <value>#1</value>
                </enumeratedValue>
              </enumeratedValues>
            </field>
            <field>
              <name>BRK13</name>
              <description>Break Character Generation Length</description>
              <bitOffset>2</bitOffset>
              <bitWidth>1</bitWidth>
              <access>read-write</access>
              <enumeratedValues>
                <enumeratedValue>
                  <name>0</name>
                  <description>Break character is transmitted with length of 10 bit times (if M = 0, SBNS = 0) or 11 (if M = 1, SBNS = 0 or M = 0, SBNS = 1) or 12 (if M = 1, SBNS = 1).</description>
                  <value>#0</value>
                </enumeratedValue>
                <enumeratedValue>
                  <name>1</name>
                  <description>Break character is transmitted with length of 13 bit times (if M = 0, SBNS = 0) or 14 (if M = 1, SBNS = 0 or M = 0, SBNS = 1) or 15 (if M = 1, SBNS = 1).</description>
                  <value>#1</value>
                </enumeratedValue>
              </enumeratedValues>
            </field>
            <field>
              <name>RWUID</name>
              <description>Receive Wake Up Idle Detect</description>
              <bitOffset>3</bitOffset>
              <bitWidth>1</bitWidth>
              <access>read-write</access>
              <enumeratedValues>
                <enumeratedValue>
                  <name>0</name>
                  <description>During receive standby state (RWU = 1), S1[IDLE] does not get set upon detection of an idle character.</description>
                  <value>#0</value>
                </enumeratedValue>
                <enumeratedValue>
                  <name>1</name>
                  <description>During receive standby state (RWU = 1), S1[IDLE] gets set upon detection of an idle character.</description>
                  <value>#1</value>
                </enumeratedValue>
              </enumeratedValues>
            </field>
            <field>
              <name>RXINV</name>
              <description>Receive Data Inversion</description>
              <bitOffset>4</bitOffset>
              <bitWidth>1</bitWidth>
              <access>read-write</access>
              <enumeratedValues>
                <enumeratedValue>
                  <name>0</name>
                  <description>Receive data not inverted.</description>
                  <value>#0</value>
                </enumeratedValue>
                <enumeratedValue>
                  <name>1</name>
                  <description>Receive data inverted.</description>
                  <value>#1</value>
                </enumeratedValue>
              </enumeratedValues>
            </field>
            <field>
              <name>RXEDGIF</name>
              <description>RxD Pin Active Edge Interrupt Flag</description>
              <bitOffset>6</bitOffset>
              <bitWidth>1</bitWidth>
              <access>read-write</access>
              <enumeratedValues>
                <enumeratedValue>
                  <name>0</name>
                  <description>No active edge on the receive pin has occurred.</description>
                  <value>#0</value>
                </enumeratedValue>
                <enumeratedValue>
                  <name>1</name>
                  <description>An active edge on the receive pin has occurred.</description>
                  <value>#1</value>
                </enumeratedValue>
              </enumeratedValues>
            </field>
            <field>
              <name>LBKDIF</name>
              <description>LIN Break Detect Interrupt Flag</description>
              <bitOffset>7</bitOffset>
              <bitWidth>1</bitWidth>
              <access>read-write</access>
              <enumeratedValues>
                <enumeratedValue>
                  <name>0</name>
                  <description>No LIN break character has been detected.</description>
                  <value>#0</value>
                </enumeratedValue>
                <enumeratedValue>
                  <name>1</name>
                  <description>LIN break character has been detected.</description>
                  <value>#1</value>
                </enumeratedValue>
              </enumeratedValues>
            </field>
          </fields>
        </register>
        <register>
          <name>C3</name>
          <description>UART Control Register 3</description>
          <addressOffset>0x6</addressOffset>
          <size>8</size>
          <access>read-write</access>
          <resetValue>0</resetValue>
          <resetMask>0xFF</resetMask>
          <fields>
            <field>
              <name>PEIE</name>
              <description>Parity Error Interrupt Enable</description>
              <bitOffset>0</bitOffset>
              <bitWidth>1</bitWidth>
              <access>read-write</access>
              <enumeratedValues>
                <enumeratedValue>
                  <name>0</name>
                  <description>PF interrupts disabled; use polling).</description>
                  <value>#0</value>
                </enumeratedValue>
                <enumeratedValue>
                  <name>1</name>
                  <description>Hardware interrupt requested when PF is set.</description>
                  <value>#1</value>
                </enumeratedValue>
              </enumeratedValues>
            </field>
            <field>
              <name>FEIE</name>
              <description>Framing Error Interrupt Enable</description>
              <bitOffset>1</bitOffset>
              <bitWidth>1</bitWidth>
              <access>read-write</access>
              <enumeratedValues>
                <enumeratedValue>
                  <name>0</name>
                  <description>FE interrupts disabled; use polling).</description>
                  <value>#0</value>
                </enumeratedValue>
                <enumeratedValue>
                  <name>1</name>
                  <description>Hardware interrupt requested when FE is set.</description>
                  <value>#1</value>
                </enumeratedValue>
              </enumeratedValues>
            </field>
            <field>
              <name>NEIE</name>
              <description>Noise Error Interrupt Enable</description>
              <bitOffset>2</bitOffset>
              <bitWidth>1</bitWidth>
              <access>read-write</access>
              <enumeratedValues>
                <enumeratedValue>
                  <name>0</name>
                  <description>NF interrupts disabled; use polling).</description>
                  <value>#0</value>
                </enumeratedValue>
                <enumeratedValue>
                  <name>1</name>
                  <description>Hardware interrupt requested when NF is set.</description>
                  <value>#1</value>
                </enumeratedValue>
              </enumeratedValues>
            </field>
            <field>
              <name>ORIE</name>
              <description>Overrun Interrupt Enable</description>
              <bitOffset>3</bitOffset>
              <bitWidth>1</bitWidth>
              <access>read-write</access>
              <enumeratedValues>
                <enumeratedValue>
                  <name>0</name>
                  <description>OR interrupts disabled; use polling.</description>
                  <value>#0</value>
                </enumeratedValue>
                <enumeratedValue>
                  <name>1</name>
                  <description>Hardware interrupt requested when OR is set.</description>
                  <value>#1</value>
                </enumeratedValue>
              </enumeratedValues>
            </field>
            <field>
              <name>TXINV</name>
              <description>Transmit Data Inversion</description>
              <bitOffset>4</bitOffset>
              <bitWidth>1</bitWidth>
              <access>read-write</access>
              <enumeratedValues>
                <enumeratedValue>
                  <name>0</name>
                  <description>Transmit data not inverted.</description>
                  <value>#0</value>
                </enumeratedValue>
                <enumeratedValue>
                  <name>1</name>
                  <description>Transmit data inverted.</description>
                  <value>#1</value>
                </enumeratedValue>
              </enumeratedValues>
            </field>
            <field>
              <name>TXDIR</name>
              <description>TxD Pin Direction in Single-Wire Mode</description>
              <bitOffset>5</bitOffset>
              <bitWidth>1</bitWidth>
              <access>read-write</access>
              <enumeratedValues>
                <enumeratedValue>
                  <name>0</name>
                  <description>TxD pin is an input in single-wire mode.</description>
                  <value>#0</value>
                </enumeratedValue>
                <enumeratedValue>
                  <name>1</name>
                  <description>TxD pin is an output in single-wire mode.</description>
                  <value>#1</value>
                </enumeratedValue>
              </enumeratedValues>
            </field>
            <field>
              <name>T8</name>
              <description>Ninth Data Bit for Transmitter</description>
              <bitOffset>6</bitOffset>
              <bitWidth>1</bitWidth>
              <access>read-write</access>
            </field>
            <field>
              <name>R8</name>
              <description>Ninth Data Bit for Receiver</description>
              <bitOffset>7</bitOffset>
              <bitWidth>1</bitWidth>
              <access>read-only</access>
            </field>
          </fields>
        </register>
        <register>
          <name>D</name>
          <description>UART Data Register</description>
          <addressOffset>0x7</addressOffset>
          <size>8</size>
          <access>read-write</access>
          <resetValue>0</resetValue>
          <resetMask>0xFF</resetMask>
          <fields>
            <field>
              <name>R0T0</name>
              <description>Read receive data buffer 0 or write transmit data buffer 0.</description>
              <bitOffset>0</bitOffset>
              <bitWidth>1</bitWidth>
              <access>read-write</access>
            </field>
            <field>
              <name>R1T1</name>
              <description>Read receive data buffer 1 or write transmit data buffer 1.</description>
              <bitOffset>1</bitOffset>
              <bitWidth>1</bitWidth>
              <access>read-write</access>
            </field>
            <field>
              <name>R2T2</name>
              <description>Read receive data buffer 2 or write transmit data buffer 2.</description>
              <bitOffset>2</bitOffset>
              <bitWidth>1</bitWidth>
              <access>read-write</access>
            </field>
            <field>
              <name>R3T3</name>
              <description>Read receive data buffer 3 or write transmit data buffer 3.</description>
              <bitOffset>3</bitOffset>
              <bitWidth>1</bitWidth>
              <access>read-write</access>
            </field>
            <field>
              <name>R4T4</name>
              <description>Read receive data buffer 4 or write transmit data buffer 4.</description>
              <bitOffset>4</bitOffset>
              <bitWidth>1</bitWidth>
              <access>read-write</access>
            </field>
            <field>
              <name>R5T5</name>
              <description>Read receive data buffer 5 or write transmit data buffer 5.</description>
              <bitOffset>5</bitOffset>
              <bitWidth>1</bitWidth>
              <access>read-write</access>
            </field>
            <field>
              <name>R6T6</name>
              <description>Read receive data buffer 6 or write transmit data buffer 6.</description>
              <bitOffset>6</bitOffset>
              <bitWidth>1</bitWidth>
              <access>read-write</access>
            </field>
            <field>
              <name>R7T7</name>
              <description>Read receive data buffer 7 or write transmit data buffer 7.</description>
              <bitOffset>7</bitOffset>
              <bitWidth>1</bitWidth>
              <access>read-write</access>
            </field>
          </fields>
        </register>
        <register>
          <name>C4</name>
          <description>UART Control Register 4</description>
          <addressOffset>0x8</addressOffset>
          <size>8</size>
          <access>read-write</access>
          <resetValue>0</resetValue>
          <resetMask>0xFF</resetMask>
          <fields>
            <field>
              <name>RDMAS</name>
              <description>Receiver Full DMA Select</description>
              <bitOffset>5</bitOffset>
              <bitWidth>1</bitWidth>
              <access>read-write</access>
              <enumeratedValues>
                <enumeratedValue>
                  <name>0</name>
                  <description>If RIE is set and the RDRF flag is set, the RDRF interrupt request signal is asserted to request interrupt service.</description>
                  <value>#0</value>
                </enumeratedValue>
                <enumeratedValue>
                  <name>1</name>
                  <description>If RIE is set and the RDRF flag is set, the RDRF DMA request signal is asserted to request a DMA transfer.</description>
                  <value>#1</value>
                </enumeratedValue>
              </enumeratedValues>
            </field>
            <field>
              <name>TDMAS</name>
              <description>Transmitter DMA Select</description>
              <bitOffset>7</bitOffset>
              <bitWidth>1</bitWidth>
              <access>read-write</access>
              <enumeratedValues>
                <enumeratedValue>
                  <name>0</name>
                  <description>If TIE is set and the TDRE flag is set, the TDRE interrupt request signal is asserted to request interrupt service.</description>
                  <value>#0</value>
                </enumeratedValue>
                <enumeratedValue>
                  <name>1</name>
                  <description>If TIE is set and the TDRE flag is set, the TDRE DMA request signal is asserted to request a DMA transfer.</description>
                  <value>#1</value>
                </enumeratedValue>
              </enumeratedValues>
            </field>
          </fields>
        </register>
      </registers>
    </peripheral>
    <peripheral>
      <name>UART2</name>
      <description>Universal Asynchronous Receiver/Transmitter (UART)</description>
      <groupName>UART</groupName>
      <prependToName>UART2_</prependToName>
      <baseAddress>0x4006C000</baseAddress>
      <addressBlock>
        <offset>0</offset>
        <size>0x9</size>
        <usage>registers</usage>
      </addressBlock>
      <interrupt>
        <name>UART2</name>
        <value>14</value>
      </interrupt>
      <registers>
        <register>
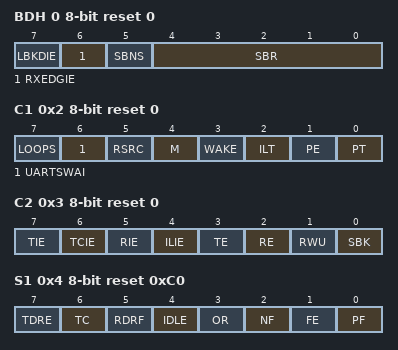
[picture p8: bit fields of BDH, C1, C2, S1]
          <name>BDH</name>
          <description>UART Baud Rate Register: High</description>
          <addressOffset>0</addressOffset>
          <size>8</size>
          <access>read-write</access>
          <resetValue>0</resetValue>
          <resetMask>0xFF</resetMask>
          <fields>
            <field>
              <name>SBR</name>
              <description>Baud Rate Modulo Divisor.</description>
              <bitOffset>0</bitOffset>
              <bitWidth>5</bitWidth>
              <access>read-write</access>
            </field>
            <field>
              <name>SBNS</name>
              <description>Stop Bit Number Select</description>
              <bitOffset>5</bitOffset>
              <bitWidth>1</bitWidth>
              <access>read-write</access>
              <enumeratedValues>
                <enumeratedValue>
                  <name>0</name>
                  <description>One stop bit.</description>
                  <value>#0</value>
                </enumeratedValue>
                <enumeratedValue>
                  <name>1</name>
                  <description>Two stop bit.</description>
                  <value>#1</value>
                </enumeratedValue>
              </enumeratedValues>
            </field>
            <field>
              <name>RXEDGIE</name>
              <description>RxD Input Active Edge Interrupt Enable (for RXEDGIF)</description>
              <bitOffset>6</bitOffset>
              <bitWidth>1</bitWidth>
              <access>read-write</access>
              <enumeratedValues>
                <enumeratedValue>
                  <name>0</name>
                  <description>Hardware interrupts from UART_S2[RXEDGIF] disabled (use polling).</description>
                  <value>#0</value>
                </enumeratedValue>
                <enumeratedValue>
                  <name>1</name>
                  <description>Hardware interrupt requested when UART_S2[RXEDGIF] flag is 1.</description>
                  <value>#1</value>
                </enumeratedValue>
              </enumeratedValues>
            </field>
            <field>
              <name>LBKDIE</name>
              <description>LIN Break Detect Interrupt Enable (for LBKDIF)</description>
              <bitOffset>7</bitOffset>
              <bitWidth>1</bitWidth>
              <access>read-write</access>
              <enumeratedValues>
                <enumeratedValue>
                  <name>0</name>
                  <description>Hardware interrupts from UART_S2[LBKDIF] disabled (use polling).</description>
                  <value>#0</value>
                </enumeratedValue>
                <enumeratedValue>
                  <name>1</name>
                  <description>Hardware interrupt requested when UART_S2[LBKDIF] flag is 1.</description>
                  <value>#1</value>
                </enumeratedValue>
              </enumeratedValues>
            </field>
          </fields>
        </register>
        <register>
          <name>BDL</name>
          <description>UART Baud Rate Register: Low</description>
          <addressOffset>0x1</addressOffset>
          <size>8</size>
          <access>read-write</access>
          <resetValue>0x4</resetValue>
          <resetMask>0xFF</resetMask>
          <fields>
            <field>
              <name>SBR</name>
              <description>Baud Rate Modulo Divisor</description>
              <bitOffset>0</bitOffset>
              <bitWidth>8</bitWidth>
              <access>read-write</access>
            </field>
          </fields>
        </register>
        <register>
          <name>C1</name>
          <description>UART Control Register 1</description>
          <addressOffset>0x2</addressOffset>
          <size>8</size>
          <access>read-write</access>
          <resetValue>0</resetValue>
          <resetMask>0xFF</resetMask>
          <fields>
            <field>
              <name>PT</name>
              <description>Parity Type</description>
              <bitOffset>0</bitOffset>
              <bitWidth>1</bitWidth>
              <access>read-write</access>
              <enumeratedValues>
                <enumeratedValue>
                  <name>0</name>
                  <description>Even parity.</description>
                  <value>#0</value>
                </enumeratedValue>
                <enumeratedValue>
                  <name>1</name>
                  <description>Odd parity.</description>
                  <value>#1</value>
                </enumeratedValue>
              </enumeratedValues>
            </field>
            <field>
              <name>PE</name>
              <description>Parity Enable</description>
              <bitOffset>1</bitOffset>
              <bitWidth>1</bitWidth>
              <access>read-write</access>
              <enumeratedValues>
                <enumeratedValue>
                  <name>0</name>
                  <description>No hardware parity generation or checking.</description>
                  <value>#0</value>
                </enumeratedValue>
                <enumeratedValue>
                  <name>1</name>
                  <description>Parity enabled.</description>
                  <value>#1</value>
                </enumeratedValue>
              </enumeratedValues>
            </field>
            <field>
              <name>ILT</name>
              <description>Idle Line Type Select</description>
              <bitOffset>2</bitOffset>
              <bitWidth>1</bitWidth>
              <access>read-write</access>
              <enumeratedValues>
                <enumeratedValue>
                  <name>0</name>
                  <description>Idle character bit count starts after start bit.</description>
                  <value>#0</value>
                </enumeratedValue>
                <enumeratedValue>
                  <name>1</name>
                  <description>Idle character bit count starts after stop bit.</description>
                  <value>#1</value>
                </enumeratedValue>
              </enumeratedValues>
            </field>
            <field>
              <name>WAKE</name>
              <description>Receiver Wakeup Method Select</description>
              <bitOffset>3</bitOffset>
              <bitWidth>1</bitWidth>
              <access>read-write</access>
              <enumeratedValues>
                <enumeratedValue>
                  <name>0</name>
                  <description>Idle-line wake-up.</description>
                  <value>#0</value>
                </enumeratedValue>
                <enumeratedValue>
                  <name>1</name>
                  <description>Address-mark wake-up.</description>
                  <value>#1</value>
                </enumeratedValue>
              </enumeratedValues>
            </field>
            <field>
              <name>M</name>
              <description>9-Bit or 8-Bit Mode Select</description>
              <bitOffset>4</bitOffset>
              <bitWidth>1</bitWidth>
              <access>read-write</access>
              <enumeratedValues>
                <enumeratedValue>
                  <name>0</name>
                  <description>Normal - start + 8 data bits (lsb first) + stop.</description>
                  <value>#0</value>
                </enumeratedValue>
                <enumeratedValue>
                  <name>1</name>
                  <description>Receiver and transmitter use 9-bit data characters start + 8 data bits (lsb first) + 9th data bit + stop.</description>
                  <value>#1</value>
                </enumeratedValue>
              </enumeratedValues>
            </field>
            <field>
              <name>RSRC</name>
              <description>Receiver Source Select</description>
              <bitOffset>5</bitOffset>
              <bitWidth>1</bitWidth>
              <access>read-write</access>
              <enumeratedValues>
                <enumeratedValue>
                  <name>0</name>
                  <description>Provided LOOPS is set, RSRC is cleared, selects internal loop back mode and the UART does not use the RxD pins.</description>
                  <value>#0</value>
                </enumeratedValue>
                <enumeratedValue>
                  <name>1</name>
                  <description>Single-wire UART mode where the TxD pin is connected to the transmitter output and receiver input.</description>
                  <value>#1</value>
                </enumeratedValue>
              </enumeratedValues>
            </field>
            <field>
              <name>UARTSWAI</name>
              <description>UART Stops in Wait Mode</description>
              <bitOffset>6</bitOffset>
              <bitWidth>1</bitWidth>
              <access>read-write</access>
              <enumeratedValues>
                <enumeratedValue>
                  <name>0</name>
                  <description>UART clocks continue to run in Wait mode so the UART can be the source of an interrupt that wakes up the CPU.</description>
                  <value>#0</value>
                </enumeratedValue>
                <enumeratedValue>
                  <name>1</name>
                  <description>UART clocks freeze while CPU is in Wait mode.</description>
                  <value>#1</value>
                </enumeratedValue>
              </enumeratedValues>
            </field>
            <field>
              <name>LOOPS</name>
              <description>Loop Mode Select</description>
              <bitOffset>7</bitOffset>
              <bitWidth>1</bitWidth>
              <access>read-write</access>
              <enumeratedValues>
                <enumeratedValue>
                  <name>0</name>
                  <description>Normal operation - RxD and TxD use separate pins.</description>
                  <value>#0</value>
                </enumeratedValue>
                <enumeratedValue>
                  <name>1</name>
                  <description>Loop mode or single-wire mode where transmitter outputs are internally connected to receiver input. (See RSRC bit.) RxD pin is not used by UART.</description>
                  <value>#1</value>
                </enumeratedValue>
              </enumeratedValues>
            </field>
          </fields>
        </register>
        <register>
          <name>C2</name>
          <description>UART Control Register 2</description>
          <addressOffset>0x3</addressOffset>
          <size>8</size>
          <access>read-write</access>
          <resetValue>0</resetValue>
          <resetMask>0xFF</resetMask>
          <fields>
            <field>
              <name>SBK</name>
              <description>Send Break</description>
              <bitOffset>0</bitOffset>
              <bitWidth>1</bitWidth>
              <access>read-write</access>
              <enumeratedValues>
                <enumeratedValue>
                  <name>0</name>
                  <description>Normal transmitter operation.</description>
                  <value>#0</value>
                </enumeratedValue>
                <enumeratedValue>
                  <name>1</name>
                  <description>Queue break character(s) to be sent.</description>
                  <value>#1</value>
                </enumeratedValue>
              </enumeratedValues>
            </field>
            <field>
              <name>RWU</name>
              <description>Receiver Wakeup Control</description>
              <bitOffset>1</bitOffset>
              <bitWidth>1</bitWidth>
              <access>read-write</access>
              <enumeratedValues>
                <enumeratedValue>
                  <name>0</name>
                  <description>Normal UART receiver operation.</description>
                  <value>#0</value>
                </enumeratedValue>
                <enumeratedValue>
                  <name>1</name>
                  <description>UART receiver in standby waiting for wake-up condition.</description>
                  <value>#1</value>
                </enumeratedValue>
              </enumeratedValues>
            </field>
            <field>
              <name>RE</name>
              <description>Receiver Enable</description>
              <bitOffset>2</bitOffset>
              <bitWidth>1</bitWidth>
              <access>read-write</access>
              <enumeratedValues>
                <enumeratedValue>
                  <name>0</name>
                  <description>Receiver off.</description>
                  <value>#0</value>
                </enumeratedValue>
                <enumeratedValue>
                  <name>1</name>
                  <description>Receiver on.</description>
                  <value>#1</value>
                </enumeratedValue>
              </enumeratedValues>
            </field>
            <field>
              <name>TE</name>
              <description>Transmitter Enable</description>
              <bitOffset>3</bitOffset>
              <bitWidth>1</bitWidth>
              <access>read-write</access>
              <enumeratedValues>
                <enumeratedValue>
                  <name>0</name>
                  <description>Transmitter off.</description>
                  <value>#0</value>
                </enumeratedValue>
                <enumeratedValue>
                  <name>1</name>
                  <description>Transmitter on.</description>
                  <value>#1</value>
                </enumeratedValue>
              </enumeratedValues>
            </field>
            <field>
              <name>ILIE</name>
              <description>Idle Line Interrupt Enable for IDLE</description>
              <bitOffset>4</bitOffset>
              <bitWidth>1</bitWidth>
              <access>read-write</access>
              <enumeratedValues>
                <enumeratedValue>
                  <name>0</name>
                  <description>Hardware interrupts from S1[IDLE] disabled; use polling.</description>
                  <value>#0</value>
                </enumeratedValue>
                <enumeratedValue>
                  <name>1</name>
                  <description>Hardware interrupt requested when S1[IDLE] flag is 1.</description>
                  <value>#1</value>
                </enumeratedValue>
              </enumeratedValues>
            </field>
            <field>
              <name>RIE</name>
              <description>Receiver Interrupt Enable for RDRF</description>
              <bitOffset>5</bitOffset>
              <bitWidth>1</bitWidth>
              <access>read-write</access>
              <enumeratedValues>
                <enumeratedValue>
                  <name>0</name>
                  <description>Hardware interrupts from S1[RDRF] disabled; use polling.</description>
                  <value>#0</value>
                </enumeratedValue>
                <enumeratedValue>
                  <name>1</name>
                  <description>Hardware interrupt requested when S1[RDRF] flag is 1.</description>
                  <value>#1</value>
                </enumeratedValue>
              </enumeratedValues>
            </field>
            <field>
              <name>TCIE</name>
              <description>Transmission Complete Interrupt Enable for TC</description>
              <bitOffset>6</bitOffset>
              <bitWidth>1</bitWidth>
              <access>read-write</access>
              <enumeratedValues>
                <enumeratedValue>
                  <name>0</name>
                  <description>Hardware interrupts from TC disabled; use polling.</description>
                  <value>#0</value>
                </enumeratedValue>
                <enumeratedValue>
                  <name>1</name>
                  <description>Hardware interrupt requested when TC flag is 1.</description>
                  <value>#1</value>
                </enumeratedValue>
              </enumeratedValues>
            </field>
            <field>
              <name>TIE</name>
              <description>Transmit Interrupt Enable for TDRE</description>
              <bitOffset>7</bitOffset>
              <bitWidth>1</bitWidth>
              <access>read-write</access>
              <enumeratedValues>
                <enumeratedValue>
                  <name>0</name>
                  <description>Hardware interrupts from TDRE disabled; use polling.</description>
                  <value>#0</value>
                </enumeratedValue>
                <enumeratedValue>
                  <name>1</name>
                  <description>Hardware interrupt requested when TDRE flag is 1.</description>
                  <value>#1</value>
                </enumeratedValue>
              </enumeratedValues>
            </field>
          </fields>
        </register>
        <register>
          <name>S1</name>
          <description>UART Status Register 1</description>
          <addressOffset>0x4</addressOffset>
          <size>8</size>
          <access>read-only</access>
          <resetValue>0xC0</resetValue>
          <resetMask>0xFF</resetMask>
          <fields>
            <field>
              <name>PF</name>
              <description>Parity Error Flag</description>
              <bitOffset>0</bitOffset>
              <bitWidth>1</bitWidth>
              <access>read-only</access>
              <enumeratedValues>
                <enumeratedValue>
                  <name>0</name>
                  <description>No parity error.</description>
                  <value>#0</value>
                </enumeratedValue>
                <enumeratedValue>
                  <name>1</name>
                  <description>Parity error.</description>
                  <value>#1</value>
                </enumeratedValue>
              </enumeratedValues>
            </field>
            <field>
              <name>FE</name>
              <description>Framing Error Flag</description>
              <bitOffset>1</bitOffset>
              <bitWidth>1</bitWidth>
              <access>read-only</access>
              <enumeratedValues>
                <enumeratedValue>
                  <name>0</name>
                  <description>No framing error detected. This does not guarantee the framing is correct.</description>
                  <value>#0</value>
                </enumeratedValue>
                <enumeratedValue>
                  <name>1</name>
                  <description>Framing error.</description>
                  <value>#1</value>
                </enumeratedValue>
              </enumeratedValues>
            </field>
            <field>
              <name>NF</name>
              <description>Noise Flag</description>
              <bitOffset>2</bitOffset>
              <bitWidth>1</bitWidth>
              <access>read-only</access>
              <enumeratedValues>
                <enumeratedValue>
                  <name>0</name>
                  <description>No noise detected.</description>
                  <value>#0</value>
                </enumeratedValue>
                <enumeratedValue>
                  <name>1</name>
                  <description>Noise detected in the received character in UART_D.</description>
                  <value>#1</value>
                </enumeratedValue>
              </enumeratedValues>
            </field>
            <field>
              <name>OR</name>
              <description>Receiver Overrun Flag</description>
              <bitOffset>3</bitOffset>
              <bitWidth>1</bitWidth>
              <access>read-only</access>
              <enumeratedValues>
                <enumeratedValue>
                  <name>0</name>
                  <description>No overrun.</description>
                  <value>#0</value>
                </enumeratedValue>
                <enumeratedValue>
                  <name>1</name>
                  <description>Receive overrun (new UART data lost).</description>
                  <value>#1</value>
                </enumeratedValue>
              </enumeratedValues>
            </field>
            <field>
              <name>IDLE</name>
              <description>Idle Line Flag</description>
              <bitOffset>4</bitOffset>
              <bitWidth>1</bitWidth>
              <access>read-only</access>
              <enumeratedValues>
                <enumeratedValue>
                  <name>0</name>
                  <description>No idle line detected.</description>
                  <value>#0</value>
                </enumeratedValue>
                <enumeratedValue>
                  <name>1</name>
                  <description>Idle line was detected.</description>
                  <value>#1</value>
                </enumeratedValue>
              </enumeratedValues>
            </field>
            <field>
              <name>RDRF</name>
              <description>Receive Data Register Full Flag</description>
              <bitOffset>5</bitOffset>
              <bitWidth>1</bitWidth>
              <access>read-only</access>
              <enumeratedValues>
                <enumeratedValue>
                  <name>0</name>
                  <description>Receive data register empty.</description>
                  <value>#0</value>
                </enumeratedValue>
                <enumeratedValue>
                  <name>1</name>
                  <description>Receive data register full.</description>
                  <value>#1</value>
                </enumeratedValue>
              </enumeratedValues>
            </field>
            <field>
              <name>TC</name>
              <description>Transmission Complete Flag</description>
              <bitOffset>6</bitOffset>
              <bitWidth>1</bitWidth>
              <access>read-only</access>
              <enumeratedValues>
                <enumeratedValue>
                  <name>0</name>
                  <description>Transmitter active (sending data, a preamble, or a break).</description>
                  <value>#0</value>
                </enumeratedValue>
                <enumeratedValue>
                  <name>1</name>
                  <description>Transmitter idle (transmission activity complete).</description>
                  <value>#1</value>
                </enumeratedValue>
              </enumeratedValues>
            </field>
            <field>
              <name>TDRE</name>
              <description>Transmit Data Register Empty Flag</description>
              <bitOffset>7</bitOffset>
              <bitWidth>1</bitWidth>
              <access>read-only</access>
              <enumeratedValues>
                <enumeratedValue>
                  <name>0</name>
                  <description>Transmit data register (buffer) full.</description>
                  <value>#0</value>
                </enumeratedValue>
                <enumeratedValue>
                  <name>1</name>
                  <description>Transmit data register (buffer) empty.</description>
                  <value>#1</value>
                </enumeratedValue>
              </enumeratedValues>
            </field>
          </fields>
        </register>
        <register>
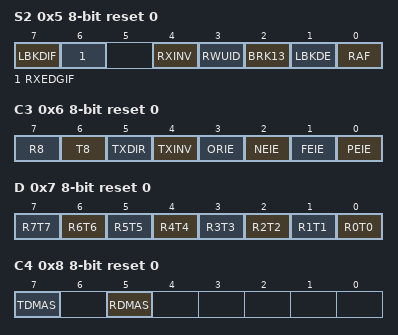
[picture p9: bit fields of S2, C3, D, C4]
          <name>S2</name>
          <description>UART Status Register 2</description>
          <addressOffset>0x5</addressOffset>
          <size>8</size>
          <access>read-write</access>
          <resetValue>0</resetValue>
          <resetMask>0xFF</resetMask>
          <fields>
            <field>
              <name>RAF</name>
              <description>Receiver Active Flag</description>
              <bitOffset>0</bitOffset>
              <bitWidth>1</bitWidth>
              <access>read-only</access>
              <enumeratedValues>
                <enumeratedValue>
                  <name>0</name>
                  <description>UART receiver idle waiting for a start bit.</description>
                  <value>#0</value>
                </enumeratedValue>
                <enumeratedValue>
                  <name>1</name>
                  <description>UART receiver active (RxD input not idle).</description>
                  <value>#1</value>
                </enumeratedValue>
              </enumeratedValues>
            </field>
            <field>
              <name>LBKDE</name>
              <description>LIN Break Detection Enable</description>
              <bitOffset>1</bitOffset>
              <bitWidth>1</bitWidth>
              <access>read-write</access>
              <enumeratedValues>
                <enumeratedValue>
                  <name>0</name>
                  <description>Break detection is disabled.</description>
                  <value>#0</value>
                </enumeratedValue>
                <enumeratedValue>
                  <name>1</name>
                  <description>Break detection is enabled (Break character is detected at length 11 bit times (if C1[M] = 0, BDH[SBNS] = 0) or 12 (if C1[M] = 1, BDH[SBNS] = 0 or C1[M] = 0, BDH[SBNS] = 1) or 13 (if C1[M] = 1, BDH[SBNS] = 1)).</description>
                  <value>#1</value>
                </enumeratedValue>
              </enumeratedValues>
            </field>
            <field>
              <name>BRK13</name>
              <description>Break Character Generation Length</description>
              <bitOffset>2</bitOffset>
              <bitWidth>1</bitWidth>
              <access>read-write</access>
              <enumeratedValues>
                <enumeratedValue>
                  <name>0</name>
                  <description>Break character is transmitted with length of 10 bit times (if M = 0, SBNS = 0) or 11 (if M = 1, SBNS = 0 or M = 0, SBNS = 1) or 12 (if M = 1, SBNS = 1).</description>
                  <value>#0</value>
                </enumeratedValue>
                <enumeratedValue>
                  <name>1</name>
                  <description>Break character is transmitted with length of 13 bit times (if M = 0, SBNS = 0) or 14 (if M = 1, SBNS = 0 or M = 0, SBNS = 1) or 15 (if M = 1, SBNS = 1).</description>
                  <value>#1</value>
                </enumeratedValue>
              </enumeratedValues>
            </field>
            <field>
              <name>RWUID</name>
              <description>Receive Wake Up Idle Detect</description>
              <bitOffset>3</bitOffset>
              <bitWidth>1</bitWidth>
              <access>read-write</access>
              <enumeratedValues>
                <enumeratedValue>
                  <name>0</name>
                  <description>During receive standby state (RWU = 1), S1[IDLE] does not get set upon detection of an idle character.</description>
                  <value>#0</value>
                </enumeratedValue>
                <enumeratedValue>
                  <name>1</name>
                  <description>During receive standby state (RWU = 1), S1[IDLE] gets set upon detection of an idle character.</description>
                  <value>#1</value>
                </enumeratedValue>
              </enumeratedValues>
            </field>
            <field>
              <name>RXINV</name>
              <description>Receive Data Inversion</description>
              <bitOffset>4</bitOffset>
              <bitWidth>1</bitWidth>
              <access>read-write</access>
              <enumeratedValues>
                <enumeratedValue>
                  <name>0</name>
                  <description>Receive data not inverted.</description>
                  <value>#0</value>
                </enumeratedValue>
                <enumeratedValue>
                  <name>1</name>
                  <description>Receive data inverted.</description>
                  <value>#1</value>
                </enumeratedValue>
              </enumeratedValues>
            </field>
            <field>
              <name>RXEDGIF</name>
              <description>RxD Pin Active Edge Interrupt Flag</description>
              <bitOffset>6</bitOffset>
              <bitWidth>1</bitWidth>
              <access>read-write</access>
              <enumeratedValues>
                <enumeratedValue>
                  <name>0</name>
                  <description>No active edge on the receive pin has occurred.</description>
                  <value>#0</value>
                </enumeratedValue>
                <enumeratedValue>
                  <name>1</name>
                  <description>An active edge on the receive pin has occurred.</description>
                  <value>#1</value>
                </enumeratedValue>
              </enumeratedValues>
            </field>
            <field>
              <name>LBKDIF</name>
              <description>LIN Break Detect Interrupt Flag</description>
              <bitOffset>7</bitOffset>
              <bitWidth>1</bitWidth>
              <access>read-write</access>
              <enumeratedValues>
                <enumeratedValue>
                  <name>0</name>
                  <description>No LIN break character has been detected.</description>
                  <value>#0</value>
                </enumeratedValue>
                <enumeratedValue>
                  <name>1</name>
                  <description>LIN break character has been detected.</description>
                  <value>#1</value>
                </enumeratedValue>
              </enumeratedValues>
            </field>
          </fields>
        </register>
        <register>
          <name>C3</name>
          <description>UART Control Register 3</description>
          <addressOffset>0x6</addressOffset>
          <size>8</size>
          <access>read-write</access>
          <resetValue>0</resetValue>
          <resetMask>0xFF</resetMask>
          <fields>
            <field>
              <name>PEIE</name>
              <description>Parity Error Interrupt Enable</description>
              <bitOffset>0</bitOffset>
              <bitWidth>1</bitWidth>
              <access>read-write</access>
              <enumeratedValues>
                <enumeratedValue>
                  <name>0</name>
                  <description>PF interrupts disabled; use polling).</description>
                  <value>#0</value>
                </enumeratedValue>
                <enumeratedValue>
                  <name>1</name>
                  <description>Hardware interrupt requested when PF is set.</description>
                  <value>#1</value>
                </enumeratedValue>
              </enumeratedValues>
            </field>
            <field>
              <name>FEIE</name>
              <description>Framing Error Interrupt Enable</description>
              <bitOffset>1</bitOffset>
              <bitWidth>1</bitWidth>
              <access>read-write</access>
              <enumeratedValues>
                <enumeratedValue>
                  <name>0</name>
                  <description>FE interrupts disabled; use polling).</description>
                  <value>#0</value>
                </enumeratedValue>
                <enumeratedValue>
                  <name>1</name>
                  <description>Hardware interrupt requested when FE is set.</description>
                  <value>#1</value>
                </enumeratedValue>
              </enumeratedValues>
            </field>
            <field>
              <name>NEIE</name>
              <description>Noise Error Interrupt Enable</description>
              <bitOffset>2</bitOffset>
              <bitWidth>1</bitWidth>
              <access>read-write</access>
              <enumeratedValues>
                <enumeratedValue>
                  <name>0</name>
                  <description>NF interrupts disabled; use polling).</description>
                  <value>#0</value>
                </enumeratedValue>
                <enumeratedValue>
                  <name>1</name>
                  <description>Hardware interrupt requested when NF is set.</description>
                  <value>#1</value>
                </enumeratedValue>
              </enumeratedValues>
            </field>
            <field>
              <name>ORIE</name>
              <description>Overrun Interrupt Enable</description>
              <bitOffset>3</bitOffset>
              <bitWidth>1</bitWidth>
              <access>read-write</access>
              <enumeratedValues>
                <enumeratedValue>
                  <name>0</name>
                  <description>OR interrupts disabled; use polling.</description>
                  <value>#0</value>
                </enumeratedValue>
                <enumeratedValue>
                  <name>1</name>
                  <description>Hardware interrupt requested when OR is set.</description>
                  <value>#1</value>
                </enumeratedValue>
              </enumeratedValues>
            </field>
            <field>
              <name>TXINV</name>
              <description>Transmit Data Inversion</description>
              <bitOffset>4</bitOffset>
              <bitWidth>1</bitWidth>
              <access>read-write</access>
              <enumeratedValues>
                <enumeratedValue>
                  <name>0</name>
                  <description>Transmit data not inverted.</description>
                  <value>#0</value>
                </enumeratedValue>
                <enumeratedValue>
                  <name>1</name>
                  <description>Transmit data inverted.</description>
                  <value>#1</value>
                </enumeratedValue>
              </enumeratedValues>
            </field>
            <field>
              <name>TXDIR</name>
              <description>TxD Pin Direction in Single-Wire Mode</description>
              <bitOffset>5</bitOffset>
              <bitWidth>1</bitWidth>
              <access>read-write</access>
              <enumeratedValues>
                <enumeratedValue>
                  <name>0</name>
                  <description>TxD pin is an input in single-wire mode.</description>
                  <value>#0</value>
                </enumeratedValue>
                <enumeratedValue>
                  <name>1</name>
                  <description>TxD pin is an output in single-wire mode.</description>
                  <value>#1</value>
                </enumeratedValue>
              </enumeratedValues>
            </field>
            <field>
              <name>T8</name>
              <description>Ninth Data Bit for Transmitter</description>
              <bitOffset>6</bitOffset>
              <bitWidth>1</bitWidth>
              <access>read-write</access>
            </field>
            <field>
              <name>R8</name>
              <description>Ninth Data Bit for Receiver</description>
              <bitOffset>7</bitOffset>
              <bitWidth>1</bitWidth>
              <access>read-only</access>
            </field>
          </fields>
        </register>
        <register>
          <name>D</name>
          <description>UART Data Register</description>
          <addressOffset>0x7</addressOffset>
          <size>8</size>
          <access>read-write</access>
          <resetValue>0</resetValue>
          <resetMask>0xFF</resetMask>
          <fields>
            <field>
              <name>R0T0</name>
              <description>Read receive data buffer 0 or write transmit data buffer 0.</description>
              <bitOffset>0</bitOffset>
              <bitWidth>1</bitWidth>
              <access>read-write</access>
            </field>
            <field>
              <name>R1T1</name>
              <description>Read receive data buffer 1 or write transmit data buffer 1.</description>
              <bitOffset>1</bitOffset>
              <bitWidth>1</bitWidth>
              <access>read-write</access>
            </field>
            <field>
              <name>R2T2</name>
              <description>Read receive data buffer 2 or write transmit data buffer 2.</description>
              <bitOffset>2</bitOffset>
              <bitWidth>1</bitWidth>
              <access>read-write</access>
            </field>
            <field>
              <name>R3T3</name>
              <description>Read receive data buffer 3 or write transmit data buffer 3.</description>
              <bitOffset>3</bitOffset>
              <bitWidth>1</bitWidth>
              <access>read-write</access>
            </field>
            <field>
              <name>R4T4</name>
              <description>Read receive data buffer 4 or write transmit data buffer 4.</description>
              <bitOffset>4</bitOffset>
              <bitWidth>1</bitWidth>
              <access>read-write</access>
            </field>
            <field>
              <name>R5T5</name>
              <description>Read receive data buffer 5 or write transmit data buffer 5.</description>
              <bitOffset>5</bitOffset>
              <bitWidth>1</bitWidth>
              <access>read-write</access>
            </field>
            <field>
              <name>R6T6</name>
              <description>Read receive data buffer 6 or write transmit data buffer 6.</description>
              <bitOffset>6</bitOffset>
              <bitWidth>1</bitWidth>
              <access>read-write</access>
            </field>
            <field>
              <name>R7T7</name>
              <description>Read receive data buffer 7 or write transmit data buffer 7.</description>
              <bitOffset>7</bitOffset>
              <bitWidth>1</bitWidth>
              <access>read-write</access>
            </field>
          </fields>
        </register>
        <register>
          <name>C4</name>
          <description>UART Control Register 4</description>
          <addressOffset>0x8</addressOffset>
          <size>8</size>
          <access>read-write</access>
          <resetValue>0</resetValue>
          <resetMask>0xFF</resetMask>
          <fields>
            <field>
              <name>RDMAS</name>
              <description>Receiver Full DMA Select</description>
              <bitOffset>5</bitOffset>
              <bitWidth>1</bitWidth>
              <access>read-write</access>
              <enumeratedValues>
                <enumeratedValue>
                  <name>0</name>
                  <description>If RIE is set and the RDRF flag is set, the RDRF interrupt request signal is asserted to request interrupt service.</description>
                  <value>#0</value>
                </enumeratedValue>
                <enumeratedValue>
                  <name>1</name>
                  <description>If RIE is set and the RDRF flag is set, the RDRF DMA request signal is asserted to request a DMA transfer.</description>
                  <value>#1</value>
                </enumeratedValue>
              </enumeratedValues>
            </field>
            <field>
              <name>TDMAS</name>
              <description>Transmitter DMA Select</description>
              <bitOffset>7</bitOffset>
              <bitWidth>1</bitWidth>
              <access>read-write</access>
              <enumeratedValues>
                <enumeratedValue>
                  <name>0</name>
                  <description>If TIE is set and the TDRE flag is set, the TDRE interrupt request signal is asserted to request interrupt service.</description>
                  <value>#0</value>
                </enumeratedValue>
                <enumeratedValue>
                  <name>1</name>
                  <description>If TIE is set and the TDRE flag is set, the TDRE DMA request signal is asserted to request a DMA transfer.</description>
                  <value>#1</value>
                </enumeratedValue>
              </enumeratedValues>
            </field>
          </fields>
        </register>
      </registers>
    </peripheral>
    <peripheral>
      <name>CMP0</name>
      <description>High-Speed Comparator (CMP), Voltage Reference (VREF) Digital-to-Analog Converter (DAC), and Analog Mux (ANMUX)</description>
      <prependToName>CMP0_</prependToName>
      <baseAddress>0x40073000</baseAddress>
      <addressBlock>
        <offset>0</offset>
        <size>0x6</size>
        <usage>registers</usage>
      </addressBlock>
      <interrupt>
        <name>CMP0</name>
        <value>16</value>
      </interrupt>
      <registers>
        <register>
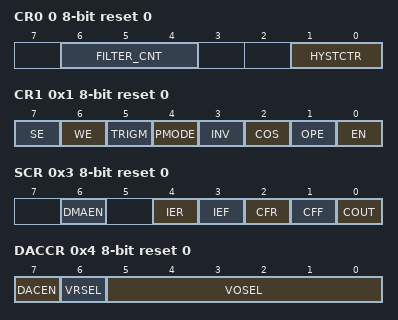
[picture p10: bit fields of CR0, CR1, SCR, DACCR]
          <name>CR0</name>
          <description>CMP Control Register 0</description>
          <addressOffset>0</addressOffset>
          <size>8</size>
          <access>read-write</access>
          <resetValue>0</resetValue>
          <resetMask>0xFF</resetMask>
          <fields>
            <field>
              <name>HYSTCTR</name>
              <description>Comparator hard block hysteresis control</description>
              <bitOffset>0</bitOffset>
              <bitWidth>2</bitWidth>
              <access>read-write</access>
              <enumeratedValues>
                <enumeratedValue>
                  <name>00</name>
                  <description>Level 0</description>
                  <value>#00</value>
                </enumeratedValue>
                <enumeratedValue>
                  <name>01</name>
                  <description>Level 1</description>
                  <value>#01</value>
                </enumeratedValue>
                <enumeratedValue>
                  <name>10</name>
                  <description>Level 2</description>
                  <value>#10</value>
                </enumeratedValue>
                <enumeratedValue>
                  <name>11</name>
                  <description>Level 3</description>
                  <value>#11</value>
                </enumeratedValue>
              </enumeratedValues>
            </field>
            <field>
              <name>FILTER_CNT</name>
              <description>Filter Sample Count</description>
              <bitOffset>4</bitOffset>
              <bitWidth>3</bitWidth>
              <access>read-write</access>
              <enumeratedValues>
                <enumeratedValue>
                  <name>000</name>
                  <description>Filter is disabled. If SE = 1, then COUT is a logic 0. This is not a legal state, and is not recommended. If SE = 0, COUT = COUTA.</description>
                  <value>#000</value>
                </enumeratedValue>
                <enumeratedValue>
                  <name>001</name>
                  <description>One sample must agree. The comparator output is simply sampled.</description>
                  <value>#001</value>
                </enumeratedValue>
                <enumeratedValue>
                  <name>010</name>
                  <description>2 consecutive samples must agree.</description>
                  <value>#010</value>
                </enumeratedValue>
                <enumeratedValue>
                  <name>011</name>
                  <description>3 consecutive samples must agree.</description>
                  <value>#011</value>
                </enumeratedValue>
                <enumeratedValue>
                  <name>100</name>
                  <description>4 consecutive samples must agree.</description>
                  <value>#100</value>
                </enumeratedValue>
                <enumeratedValue>
                  <name>101</name>
                  <description>5 consecutive samples must agree.</description>
                  <value>#101</value>
                </enumeratedValue>
                <enumeratedValue>
                  <name>110</name>
                  <description>6 consecutive samples must agree.</description>
                  <value>#110</value>
                </enumeratedValue>
                <enumeratedValue>
                  <name>111</name>
                  <description>7 consecutive samples must agree.</description>
                  <value>#111</value>
                </enumeratedValue>
              </enumeratedValues>
            </field>
          </fields>
        </register>
        <register>
          <name>CR1</name>
          <description>CMP Control Register 1</description>
          <addressOffset>0x1</addressOffset>
          <size>8</size>
          <access>read-write</access>
          <resetValue>0</resetValue>
          <resetMask>0xFF</resetMask>
          <fields>
            <field>
              <name>EN</name>
              <description>Comparator Module Enable</description>
              <bitOffset>0</bitOffset>
              <bitWidth>1</bitWidth>
              <access>read-write</access>
              <enumeratedValues>
                <enumeratedValue>
                  <name>0</name>
                  <description>Analog Comparator is disabled.</description>
                  <value>#0</value>
                </enumeratedValue>
                <enumeratedValue>
                  <name>1</name>
                  <description>Analog Comparator is enabled.</description>
                  <value>#1</value>
                </enumeratedValue>
              </enumeratedValues>
            </field>
            <field>
              <name>OPE</name>
              <description>Comparator Output Pin Enable</description>
              <bitOffset>1</bitOffset>
              <bitWidth>1</bitWidth>
              <access>read-write</access>
              <enumeratedValues>
                <enumeratedValue>
                  <name>0</name>
                  <description>CMPO is not available on the associated CMPO output pin. If the comparator does not own the pin, this field has no effect.</description>
                  <value>#0</value>
                </enumeratedValue>
                <enumeratedValue>
                  <name>1</name>
                  <description>CMPO is available on the associated CMPO output pin. The comparator output (CMPO) is driven out on the associated CMPO output pin if the comparator owns the pin. If the comparator does not own the field, this bit has no effect.</description>
                  <value>#1</value>
                </enumeratedValue>
              </enumeratedValues>
            </field>
            <field>
              <name>COS</name>
              <description>Comparator Output Select</description>
              <bitOffset>2</bitOffset>
              <bitWidth>1</bitWidth>
              <access>read-write</access>
              <enumeratedValues>
                <enumeratedValue>
                  <name>0</name>
                  <description>Set the filtered comparator output (CMPO) to equal COUT.</description>
                  <value>#0</value>
                </enumeratedValue>
                <enumeratedValue>
                  <name>1</name>
                  <description>Set the unfiltered comparator output (CMPO) to equal COUTA.</description>
                  <value>#1</value>
                </enumeratedValue>
              </enumeratedValues>
            </field>
            <field>
              <name>INV</name>
              <description>Comparator INVERT</description>
              <bitOffset>3</bitOffset>
              <bitWidth>1</bitWidth>
              <access>read-write</access>
              <enumeratedValues>
                <enumeratedValue>
                  <name>0</name>
                  <description>Does not invert the comparator output.</description>
                  <value>#0</value>
                </enumeratedValue>
                <enumeratedValue>
                  <name>1</name>
                  <description>Inverts the comparator output.</description>
                  <value>#1</value>
                </enumeratedValue>
              </enumeratedValues>
            </field>
            <field>
              <name>PMODE</name>
              <description>Power Mode Select</description>
              <bitOffset>4</bitOffset>
              <bitWidth>1</bitWidth>
              <access>read-write</access>
              <enumeratedValues>
                <enumeratedValue>
                  <name>0</name>
                  <description>Low-Speed (LS) Comparison mode selected. In this mode, CMP has slower output propagation delay and lower current consumption.</description>
                  <value>#0</value>
                </enumeratedValue>
                <enumeratedValue>
                  <name>1</name>
                  <description>High-Speed (HS) Comparison mode selected. In this mode, CMP has faster output propagation delay and higher current consumption.</description>
                  <value>#1</value>
                </enumeratedValue>
              </enumeratedValues>
            </field>
            <field>
              <name>TRIGM</name>
              <description>Trigger Mode Enable</description>
              <bitOffset>5</bitOffset>
              <bitWidth>1</bitWidth>
              <access>read-write</access>
              <enumeratedValues>
                <enumeratedValue>
                  <name>0</name>
                  <description>Trigger mode is disabled.</description>
                  <value>#0</value>
                </enumeratedValue>
                <enumeratedValue>
                  <name>1</name>
                  <description>Trigger mode is enabled.</description>
                  <value>#1</value>
                </enumeratedValue>
              </enumeratedValues>
            </field>
            <field>
              <name>WE</name>
              <description>Windowing Enable</description>
              <bitOffset>6</bitOffset>
              <bitWidth>1</bitWidth>
              <access>read-write</access>
              <enumeratedValues>
                <enumeratedValue>
                  <name>0</name>
                  <description>Windowing mode is not selected.</description>
                  <value>#0</value>
                </enumeratedValue>
                <enumeratedValue>
                  <name>1</name>
                  <description>Windowing mode is selected.</description>
                  <value>#1</value>
                </enumeratedValue>
              </enumeratedValues>
            </field>
            <field>
              <name>SE</name>
              <description>Sample Enable</description>
              <bitOffset>7</bitOffset>
              <bitWidth>1</bitWidth>
              <access>read-write</access>
              <enumeratedValues>
                <enumeratedValue>
                  <name>0</name>
                  <description>Sampling mode is not selected.</description>
                  <value>#0</value>
                </enumeratedValue>
                <enumeratedValue>
                  <name>1</name>
                  <description>Sampling mode is selected.</description>
                  <value>#1</value>
                </enumeratedValue>
              </enumeratedValues>
            </field>
          </fields>
        </register>
        <register>
          <name>FPR</name>
          <description>CMP Filter Period Register</description>
          <addressOffset>0x2</addressOffset>
          <size>8</size>
          <access>read-write</access>
          <resetValue>0</resetValue>
          <resetMask>0xFF</resetMask>
          <fields>
            <field>
              <name>FILT_PER</name>
              <description>Filter Sample Period</description>
              <bitOffset>0</bitOffset>
              <bitWidth>8</bitWidth>
              <access>read-write</access>
            </field>
          </fields>
        </register>
        <register>
          <name>SCR</name>
          <description>CMP Status and Control Register</description>
          <addressOffset>0x3</addressOffset>
          <size>8</size>
          <access>read-write</access>
          <resetValue>0</resetValue>
          <resetMask>0xFF</resetMask>
          <fields>
            <field>
              <name>COUT</name>
              <description>Analog Comparator Output</description>
              <bitOffset>0</bitOffset>
              <bitWidth>1</bitWidth>
              <access>read-only</access>
            </field>
            <field>
              <name>CFF</name>
              <description>Analog Comparator Flag Falling</description>
              <bitOffset>1</bitOffset>
              <bitWidth>1</bitWidth>
              <access>read-write</access>
              <enumeratedValues>
                <enumeratedValue>
                  <name>0</name>
                  <description>Falling-edge on COUT has not been detected.</description>
                  <value>#0</value>
                </enumeratedValue>
                <enumeratedValue>
                  <name>1</name>
                  <description>Falling-edge on COUT has occurred.</description>
                  <value>#1</value>
                </enumeratedValue>
              </enumeratedValues>
            </field>
            <field>
              <name>CFR</name>
              <description>Analog Comparator Flag Rising</description>
              <bitOffset>2</bitOffset>
              <bitWidth>1</bitWidth>
              <access>read-write</access>
              <enumeratedValues>
                <enumeratedValue>
                  <name>0</name>
                  <description>Rising-edge on COUT has not been detected.</description>
                  <value>#0</value>
                </enumeratedValue>
                <enumeratedValue>
                  <name>1</name>
                  <description>Rising-edge on COUT has occurred.</description>
                  <value>#1</value>
                </enumeratedValue>
              </enumeratedValues>
            </field>
            <field>
              <name>IEF</name>
              <description>Comparator Interrupt Enable Falling</description>
              <bitOffset>3</bitOffset>
              <bitWidth>1</bitWidth>
              <access>read-write</access>
              <enumeratedValues>
                <enumeratedValue>
                  <name>0</name>
                  <description>Interrupt is disabled.</description>
                  <value>#0</value>
                </enumeratedValue>
                <enumeratedValue>
                  <name>1</name>
                  <description>Interrupt is enabled.</description>
                  <value>#1</value>
                </enumeratedValue>
              </enumeratedValues>
            </field>
            <field>
              <name>IER</name>
              <description>Comparator Interrupt Enable Rising</description>
              <bitOffset>4</bitOffset>
              <bitWidth>1</bitWidth>
              <access>read-write</access>
              <enumeratedValues>
                <enumeratedValue>
                  <name>0</name>
                  <description>Interrupt is disabled.</description>
                  <value>#0</value>
                </enumeratedValue>
                <enumeratedValue>
                  <name>1</name>
                  <description>Interrupt is enabled.</description>
                  <value>#1</value>
                </enumeratedValue>
              </enumeratedValues>
            </field>
            <field>
              <name>DMAEN</name>
              <description>DMA Enable Control</description>
              <bitOffset>6</bitOffset>
              <bitWidth>1</bitWidth>
              <access>read-write</access>
              <enumeratedValues>
                <enumeratedValue>
                  <name>0</name>
                  <description>DMA is disabled.</description>
                  <value>#0</value>
                </enumeratedValue>
                <enumeratedValue>
                  <name>1</name>
                  <description>DMA is enabled.</description>
                  <value>#1</value>
                </enumeratedValue>
              </enumeratedValues>
            </field>
          </fields>
        </register>
        <register>
          <name>DACCR</name>
          <description>DAC Control Register</description>
          <addressOffset>0x4</addressOffset>
          <size>8</size>
          <access>read-write</access>
          <resetValue>0</resetValue>
          <resetMask>0xFF</resetMask>
          <fields>
            <field>
              <name>VOSEL</name>
              <description>DAC Output Voltage Select</description>
              <bitOffset>0</bitOffset>
              <bitWidth>6</bitWidth>
              <access>read-write</access>
            </field>
            <field>
              <name>VRSEL</name>
              <description>Supply Voltage Reference Source Select</description>
              <bitOffset>6</bitOffset>
              <bitWidth>1</bitWidth>
              <access>read-write</access>
              <enumeratedValues>
                <enumeratedValue>
                  <name>0</name>
                  <description>V is selected as resistor ladder network supply reference V. in1 in</description>
                  <value>#0</value>
                </enumeratedValue>
                <enumeratedValue>
                  <name>1</name>
                  <description>V is selected as resistor ladder network supply reference V. in2 in</description>
                  <value>#1</value>
                </enumeratedValue>
              </enumeratedValues>
            </field>
            <field>
              <name>DACEN</name>
              <description>DAC Enable</description>
              <bitOffset>7</bitOffset>
              <bitWidth>1</bitWidth>
              <access>read-write</access>
              <enumeratedValues>
                <enumeratedValue>
                  <name>0</name>
                  <description>DAC is disabled.</description>
                  <value>#0</value>
                </enumeratedValue>
                <enumeratedValue>
                  <name>1</name>
                  <description>DAC is enabled.</description>
                  <value>#1</value>
                </enumeratedValue>
              </enumeratedValues>
            </field>
          </fields>
        </register>
        <register>
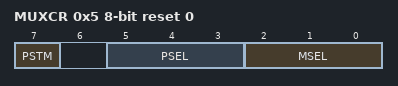
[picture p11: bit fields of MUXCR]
          <name>MUXCR</name>
          <description>MUX Control Register</description>
          <addressOffset>0x5</addressOffset>
          <size>8</size>
          <access>read-write</access>
          <resetValue>0</resetValue>
          <resetMask>0xFF</resetMask>
          <fields>
            <field>
              <name>MSEL</name>
              <description>Minus Input Mux Control</description>
              <bitOffset>0</bitOffset>
              <bitWidth>3</bitWidth>
              <access>read-write</access>
              <enumeratedValues>
                <enumeratedValue>
                  <name>000</name>
                  <description>IN0</description>
                  <value>#000</value>
                </enumeratedValue>
                <enumeratedValue>
                  <name>001</name>
                  <description>IN1</description>
                  <value>#001</value>
                </enumeratedValue>
                <enumeratedValue>
                  <name>010</name>
                  <description>IN2</description>
                  <value>#010</value>
                </enumeratedValue>
                <enumeratedValue>
                  <name>011</name>
                  <description>IN3</description>
                  <value>#011</value>
                </enumeratedValue>
                <enumeratedValue>
                  <name>100</name>
                  <description>IN4</description>
                  <value>#100</value>
                </enumeratedValue>
                <enumeratedValue>
                  <name>101</name>
                  <description>IN5</description>
                  <value>#101</value>
                </enumeratedValue>
                <enumeratedValue>
                  <name>110</name>
                  <description>IN6</description>
                  <value>#110</value>
                </enumeratedValue>
                <enumeratedValue>
                  <name>111</name>
                  <description>IN7</description>
                  <value>#111</value>
                </enumeratedValue>
              </enumeratedValues>
            </field>
            <field>
              <name>PSEL</name>
              <description>Plus Input Mux Control</description>
              <bitOffset>3</bitOffset>
              <bitWidth>3</bitWidth>
              <access>read-write</access>
              <enumeratedValues>
                <enumeratedValue>
                  <name>000</name>
                  <description>IN0</description>
                  <value>#000</value>
                </enumeratedValue>
                <enumeratedValue>
                  <name>001</name>
                  <description>IN1</description>
                  <value>#001</value>
                </enumeratedValue>
                <enumeratedValue>
                  <name>010</name>
                  <description>IN2</description>
                  <value>#010</value>
                </enumeratedValue>
                <enumeratedValue>
                  <name>011</name>
                  <description>IN3</description>
                  <value>#011</value>
                </enumeratedValue>
                <enumeratedValue>
                  <name>100</name>
                  <description>IN4</description>
                  <value>#100</value>
                </enumeratedValue>
                <enumeratedValue>
                  <name>101</name>
                  <description>IN5</description>
                  <value>#101</value>
                </enumeratedValue>
                <enumeratedValue>
                  <name>110</name>
                  <description>IN6</description>
                  <value>#110</value>
                </enumeratedValue>
                <enumeratedValue>
                  <name>111</name>
                  <description>IN7</description>
                  <value>#111</value>
                </enumeratedValue>
              </enumeratedValues>
            </field>
            <field>
              <name>PSTM</name>
              <description>Pass Through Mode Enable</description>
              <bitOffset>7</bitOffset>
              <bitWidth>1</bitWidth>
              <access>read-write</access>
              <enumeratedValues>
                <enumeratedValue>
                  <name>0</name>
                  <description>Pass Through Mode is disabled.</description>
                  <value>#0</value>
                </enumeratedValue>
                <enumeratedValue>
                  <name>1</name>
                  <description>Pass Through Mode is enabled.</description>
                  <value>#1</value>
                </enumeratedValue>
              </enumeratedValues>
            </field>
          </fields>
        </register>
      </registers>
    </peripheral>
    <peripheral>
      <name>SPI0</name>
      <description>Serial Peripheral Interface</description>
      <groupName>SPI</groupName>
      <prependToName>SPI0_</prependToName>
      <baseAddress>0x40076000</baseAddress>
      <addressBlock>
        <offset>0</offset>
        <size>0x8</size>
        <usage>registers</usage>
      </addressBlock>
      <interrupt>
        <name>SPI0</name>
        <value>10</value>
      </interrupt>
      <registers>
        <register>
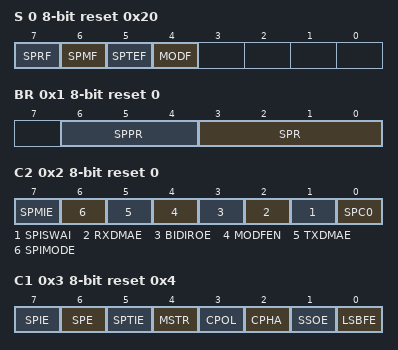
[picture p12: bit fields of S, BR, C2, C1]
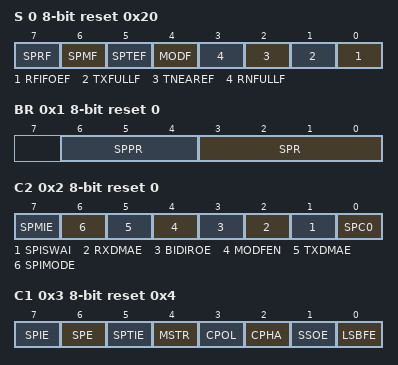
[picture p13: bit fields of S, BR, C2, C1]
          <name>S</name>
          <description>SPI Status Register</description>
          <addressOffset>0</addressOffset>
          <size>8</size>
          <access>read-write</access>
          <resetValue>0x20</resetValue>
          <resetMask>0xFF</resetMask>
          <fields>
            <field>
              <name>MODF</name>
              <description>Master Mode Fault Flag</description>
              <bitOffset>4</bitOffset>
              <bitWidth>1</bitWidth>
              <access>read-only</access>
              <enumeratedValues>
                <enumeratedValue>
                  <name>0</name>
                  <description>No mode fault error</description>
                  <value>#0</value>
                </enumeratedValue>
                <enumeratedValue>
                  <name>1</name>
                  <description>Mode fault error detected</description>
                  <value>#1</value>
                </enumeratedValue>
              </enumeratedValues>
            </field>
            <field>
              <name>SPTEF</name>
              <description>SPI Transmit Buffer Empty Flag (when FIFO is not supported or not enabled) or SPI transmit FIFO empty flag (when FIFO is supported and enabled)</description>
              <bitOffset>5</bitOffset>
              <bitWidth>1</bitWidth>
              <access>read-only</access>
              <enumeratedValues>
                <enumeratedValue>
                  <name>0</name>
                  <description>SPI transmit buffer not empty (when FIFOMODE is not present or is 0) or SPI FIFO not empty (when FIFOMODE is 1)</description>
                  <value>#0</value>
                </enumeratedValue>
                <enumeratedValue>
                  <name>1</name>
                  <description>SPI transmit buffer empty (when FIFOMODE is not present or is 0) or SPI FIFO empty (when FIFOMODE is 1)</description>
                  <value>#1</value>
                </enumeratedValue>
              </enumeratedValues>
            </field>
            <field>
              <name>SPMF</name>
              <description>SPI Match Flag</description>
              <bitOffset>6</bitOffset>
              <bitWidth>1</bitWidth>
              <access>read-write</access>
              <enumeratedValues>
                <enumeratedValue>
                  <name>0</name>
                  <description>Value in the receive data buffer does not match the value in the MH:ML registers</description>
                  <value>#0</value>
                </enumeratedValue>
                <enumeratedValue>
                  <name>1</name>
                  <description>Value in the receive data buffer matches the value in the MH:ML registers</description>
                  <value>#1</value>
                </enumeratedValue>
              </enumeratedValues>
            </field>
            <field>
              <name>SPRF</name>
              <description>SPI Read Buffer Full Flag (when FIFO is not supported or not enabled) or SPI read FIFO FULL flag (when FIFO is supported and enabled)</description>
              <bitOffset>7</bitOffset>
              <bitWidth>1</bitWidth>
              <access>read-only</access>
              <enumeratedValues>
                <enumeratedValue>
                  <name>0</name>
                  <description>No data available in the receive data buffer (when FIFOMODE is not present or is 0) or Read FIFO is not full (when FIFOMODE is 1)</description>
                  <value>#0</value>
                </enumeratedValue>
                <enumeratedValue>
                  <name>1</name>
                  <description>Data available in the receive data buffer (when FIFOMODE is not present or is 0) or Read FIFO is full (when FIFOMODE is 1)</description>
                  <value>#1</value>
                </enumeratedValue>
              </enumeratedValues>
            </field>
          </fields>
        </register>
        <register>
          <name>BR</name>
          <description>SPI Baud Rate Register</description>
          <addressOffset>0x1</addressOffset>
          <size>8</size>
          <access>read-write</access>
          <resetValue>0</resetValue>
          <resetMask>0xFF</resetMask>
          <fields>
            <field>
              <name>SPR</name>
              <description>SPI Baud Rate Divisor</description>
              <bitOffset>0</bitOffset>
              <bitWidth>4</bitWidth>
              <access>read-write</access>
              <enumeratedValues>
                <enumeratedValue>
                  <name>0000</name>
                  <description>Baud rate divisor is 2.</description>
                  <value>#0000</value>
                </enumeratedValue>
                <enumeratedValue>
                  <name>0001</name>
                  <description>Baud rate divisor is 4.</description>
                  <value>#0001</value>
                </enumeratedValue>
                <enumeratedValue>
                  <name>0010</name>
                  <description>Baud rate divisor is 8.</description>
                  <value>#0010</value>
                </enumeratedValue>
                <enumeratedValue>
                  <name>0011</name>
                  <description>Baud rate divisor is 16.</description>
                  <value>#0011</value>
                </enumeratedValue>
                <enumeratedValue>
                  <name>0100</name>
                  <description>Baud rate divisor is 32.</description>
                  <value>#0100</value>
                </enumeratedValue>
                <enumeratedValue>
                  <name>0101</name>
                  <description>Baud rate divisor is 64.</description>
                  <value>#0101</value>
                </enumeratedValue>
                <enumeratedValue>
                  <name>0110</name>
                  <description>Baud rate divisor is 128.</description>
                  <value>#0110</value>
                </enumeratedValue>
                <enumeratedValue>
                  <name>0111</name>
                  <description>Baud rate divisor is 256.</description>
                  <value>#0111</value>
                </enumeratedValue>
                <enumeratedValue>
                  <name>1000</name>
                  <description>Baud rate divisor is 512.</description>
                  <value>#1000</value>
                </enumeratedValue>
              </enumeratedValues>
            </field>
            <field>
              <name>SPPR</name>
              <description>SPI Baud Rate Prescale Divisor</description>
              <bitOffset>4</bitOffset>
              <bitWidth>3</bitWidth>
              <access>read-write</access>
              <enumeratedValues>
                <enumeratedValue>
                  <name>000</name>
                  <description>Baud rate prescaler divisor is 1.</description>
                  <value>#000</value>
                </enumeratedValue>
                <enumeratedValue>
                  <name>001</name>
                  <description>Baud rate prescaler divisor is 2.</description>
                  <value>#001</value>
                </enumeratedValue>
                <enumeratedValue>
                  <name>010</name>
                  <description>Baud rate prescaler divisor is 3.</description>
                  <value>#010</value>
                </enumeratedValue>
                <enumeratedValue>
                  <name>011</name>
                  <description>Baud rate prescaler divisor is 4.</description>
                  <value>#011</value>
                </enumeratedValue>
                <enumeratedValue>
                  <name>100</name>
                  <description>Baud rate prescaler divisor is 5.</description>
                  <value>#100</value>
                </enumeratedValue>
                <enumeratedValue>
                  <name>101</name>
                  <description>Baud rate prescaler divisor is 6.</description>
                  <value>#101</value>
                </enumeratedValue>
                <enumeratedValue>
                  <name>110</name>
                  <description>Baud rate prescaler divisor is 7.</description>
                  <value>#110</value>
                </enumeratedValue>
                <enumeratedValue>
                  <name>111</name>
                  <description>Baud rate prescaler divisor is 8.</description>
                  <value>#111</value>
                </enumeratedValue>
              </enumeratedValues>
            </field>
          </fields>
        </register>
        <register>
          <name>C2</name>
          <description>SPI Control Register 2</description>
          <addressOffset>0x2</addressOffset>
          <size>8</size>
          <access>read-write</access>
          <resetValue>0</resetValue>
          <resetMask>0xFF</resetMask>
          <fields>
            <field>
              <name>SPC0</name>
              <description>SPI Pin Control 0</description>
              <bitOffset>0</bitOffset>
              <bitWidth>1</bitWidth>
              <access>read-write</access>
              <enumeratedValues>
                <enumeratedValue>
                  <name>0</name>
                  <description>SPI uses separate pins for data input and data output (pin mode is normal). In master mode of operation: MISO is master in and MOSI is master out. In slave mode of operation: MISO is slave out and MOSI is slave in.</description>
                  <value>#0</value>
                </enumeratedValue>
                <enumeratedValue>
                  <name>1</name>
                  <description>SPI configured for single-wire bidirectional operation (pin mode is bidirectional). In master mode of operation: MISO is not used by SPI; MOSI is master in when BIDIROE is 0 or master I/O when BIDIROE is 1. In slave mode of operation: MISO is slave in when BIDIROE is 0 or slave I/O when BIDIROE is 1; MOSI is not used by SPI.</description>
                  <value>#1</value>
                </enumeratedValue>
              </enumeratedValues>
            </field>
            <field>
              <name>SPISWAI</name>
              <description>SPI Stop in Wait Mode</description>
              <bitOffset>1</bitOffset>
              <bitWidth>1</bitWidth>
              <access>read-write</access>
              <enumeratedValues>
                <enumeratedValue>
                  <name>0</name>
                  <description>SPI clocks continue to operate in Wait mode.</description>
                  <value>#0</value>
                </enumeratedValue>
                <enumeratedValue>
                  <name>1</name>
                  <description>SPI clocks stop when the MCU enters Wait mode.</description>
                  <value>#1</value>
                </enumeratedValue>
              </enumeratedValues>
            </field>
            <field>
              <name>RXDMAE</name>
              <description>Receive DMA enable</description>
              <bitOffset>2</bitOffset>
              <bitWidth>1</bitWidth>
              <access>read-write</access>
              <enumeratedValues>
                <enumeratedValue>
                  <name>0</name>
                  <description>DMA request for receive is disabled and interrupt from SPRF is allowed</description>
                  <value>#0</value>
                </enumeratedValue>
                <enumeratedValue>
                  <name>1</name>
                  <description>DMA request for receive is enabled and interrupt from SPRF is disabled</description>
                  <value>#1</value>
                </enumeratedValue>
              </enumeratedValues>
            </field>
            <field>
              <name>BIDIROE</name>
              <description>Bidirectional Mode Output Enable</description>
              <bitOffset>3</bitOffset>
              <bitWidth>1</bitWidth>
              <access>read-write</access>
              <enumeratedValues>
                <enumeratedValue>
                  <name>0</name>
                  <description>Output driver disabled so SPI data I/O pin acts as an input</description>
                  <value>#0</value>
                </enumeratedValue>
                <enumeratedValue>
                  <name>1</name>
                  <description>SPI I/O pin enabled as an output</description>
                  <value>#1</value>
                </enumeratedValue>
              </enumeratedValues>
            </field>
            <field>
              <name>MODFEN</name>
              <description>Master Mode-Fault Function Enable</description>
              <bitOffset>4</bitOffset>
              <bitWidth>1</bitWidth>
              <access>read-write</access>
              <enumeratedValues>
                <enumeratedValue>
                  <name>0</name>
                  <description>Mode fault function disabled, master SS pin reverts to general-purpose I/O not controlled by SPI</description>
                  <value>#0</value>
                </enumeratedValue>
                <enumeratedValue>
                  <name>1</name>
                  <description>Mode fault function enabled, master SS pin acts as the mode fault input or the slave select output</description>
                  <value>#1</value>
                </enumeratedValue>
              </enumeratedValues>
            </field>
            <field>
              <name>TXDMAE</name>
              <description>Transmit DMA enable</description>
              <bitOffset>5</bitOffset>
              <bitWidth>1</bitWidth>
              <access>read-write</access>
              <enumeratedValues>
                <enumeratedValue>
                  <name>0</name>
                  <description>DMA request for transmit is disabled and interrupt from SPTEF is allowed</description>
                  <value>#0</value>
                </enumeratedValue>
                <enumeratedValue>
                  <name>1</name>
                  <description>DMA request for transmit is enabled and interrupt from SPTEF is disabled</description>
                  <value>#1</value>
                </enumeratedValue>
              </enumeratedValues>
            </field>
            <field>
              <name>SPIMODE</name>
              <description>SPI 8-bit or 16-bit mode</description>
              <bitOffset>6</bitOffset>
              <bitWidth>1</bitWidth>
              <access>read-write</access>
              <enumeratedValues>
                <enumeratedValue>
                  <name>0</name>
                  <description>8-bit SPI shift register, match register, and buffers</description>
                  <value>#0</value>
                </enumeratedValue>
                <enumeratedValue>
                  <name>1</name>
                  <description>16-bit SPI shift register, match register, and buffers</description>
                  <value>#1</value>
                </enumeratedValue>
              </enumeratedValues>
            </field>
            <field>
              <name>SPMIE</name>
              <description>SPI Match Interrupt Enable</description>
              <bitOffset>7</bitOffset>
              <bitWidth>1</bitWidth>
              <access>read-write</access>
              <enumeratedValues>
                <enumeratedValue>
                  <name>0</name>
                  <description>Interrupts from SPMF inhibited (use polling)</description>
                  <value>#0</value>
                </enumeratedValue>
                <enumeratedValue>
                  <name>1</name>
                  <description>When SPMF is 1, requests a hardware interrupt</description>
                  <value>#1</value>
                </enumeratedValue>
              </enumeratedValues>
            </field>
          </fields>
        </register>
        <register>
          <name>C1</name>
          <description>SPI Control Register 1</description>
          <addressOffset>0x3</addressOffset>
          <size>8</size>
          <access>read-write</access>
          <resetValue>0x4</resetValue>
          <resetMask>0xFF</resetMask>
          <fields>
            <field>
              <name>LSBFE</name>
              <description>LSB First (shifter direction)</description>
              <bitOffset>0</bitOffset>
              <bitWidth>1</bitWidth>
              <access>read-write</access>
              <enumeratedValues>
                <enumeratedValue>
                  <name>0</name>
                  <description>SPI serial data transfers start with the most significant bit.</description>
                  <value>#0</value>
                </enumeratedValue>
                <enumeratedValue>
                  <name>1</name>
                  <description>SPI serial data transfers start with the least significant bit.</description>
                  <value>#1</value>
                </enumeratedValue>
              </enumeratedValues>
            </field>
            <field>
              <name>SSOE</name>
              <description>Slave Select Output Enable</description>
              <bitOffset>1</bitOffset>
              <bitWidth>1</bitWidth>
              <access>read-write</access>
              <enumeratedValues>
                <enumeratedValue>
                  <name>0</name>
                  <description>When C2[MODFEN] is 0: In master mode, SS pin function is general-purpose I/O (not SPI). In slave mode, SS pin function is slave select input. When C2[MODFEN] is 1: In master mode, SS pin function is SS input for mode fault. In slave mode, SS pin function is slave select input.</description>
                  <value>#0</value>
                </enumeratedValue>
                <enumeratedValue>
                  <name>1</name>
                  <description>When C2[MODFEN] is 0: In master mode, SS pin function is general-purpose I/O (not SPI). In slave mode, SS pin function is slave select input. When C2[MODFEN] is 1: In master mode, SS pin function is automatic SS output. In slave mode: SS pin function is slave select input.</description>
                  <value>#1</value>
                </enumeratedValue>
              </enumeratedValues>
            </field>
            <field>
              <name>CPHA</name>
              <description>Clock Phase</description>
              <bitOffset>2</bitOffset>
              <bitWidth>1</bitWidth>
              <access>read-write</access>
              <enumeratedValues>
                <enumeratedValue>
                  <name>0</name>
                  <description>First edge on SPSCK occurs at the middle of the first cycle of a data transfer.</description>
                  <value>#0</value>
                </enumeratedValue>
                <enumeratedValue>
                  <name>1</name>
                  <description>First edge on SPSCK occurs at the start of the first cycle of a data transfer.</description>
                  <value>#1</value>
                </enumeratedValue>
              </enumeratedValues>
            </field>
            <field>
              <name>CPOL</name>
              <description>Clock Polarity</description>
              <bitOffset>3</bitOffset>
              <bitWidth>1</bitWidth>
              <access>read-write</access>
              <enumeratedValues>
                <enumeratedValue>
                  <name>0</name>
                  <description>Active-high SPI clock (idles low)</description>
                  <value>#0</value>
                </enumeratedValue>
                <enumeratedValue>
                  <name>1</name>
                  <description>Active-low SPI clock (idles high)</description>
                  <value>#1</value>
                </enumeratedValue>
              </enumeratedValues>
            </field>
            <field>
              <name>MSTR</name>
              <description>Master/Slave Mode Select</description>
              <bitOffset>4</bitOffset>
              <bitWidth>1</bitWidth>
              <access>read-write</access>
              <enumeratedValues>
                <enumeratedValue>
                  <name>0</name>
                  <description>SPI module configured as a slave SPI device</description>
                  <value>#0</value>
                </enumeratedValue>
                <enumeratedValue>
                  <name>1</name>
                  <description>SPI module configured as a master SPI device</description>
                  <value>#1</value>
                </enumeratedValue>
              </enumeratedValues>
            </field>
            <field>
              <name>SPTIE</name>
              <description>SPI Transmit Interrupt Enable</description>
              <bitOffset>5</bitOffset>
              <bitWidth>1</bitWidth>
              <access>read-write</access>
              <enumeratedValues>
                <enumeratedValue>
                  <name>0</name>
                  <description>Interrupts from SPTEF inhibited (use polling)</description>
                  <value>#0</value>
                </enumeratedValue>
                <enumeratedValue>
                  <name>1</name>
                  <description>When SPTEF is 1, hardware interrupt requested</description>
                  <value>#1</value>
                </enumeratedValue>
              </enumeratedValues>
            </field>
            <field>
              <name>SPE</name>
              <description>SPI System Enable</description>
              <bitOffset>6</bitOffset>
              <bitWidth>1</bitWidth>
              <access>read-write</access>
              <enumeratedValues>
                <enumeratedValue>
                  <name>0</name>
                  <description>SPI system inactive</description>
                  <value>#0</value>
                </enumeratedValue>
                <enumeratedValue>
                  <name>1</name>
                  <description>SPI system enabled</description>
                  <value>#1</value>
                </enumeratedValue>
              </enumeratedValues>
            </field>
            <field>
              <name>SPIE</name>
              <description>SPI Interrupt Enable: for SPRF and MODF (when FIFO is not supported or not enabled) or for read FIFO (when FIFO is supported and enabled)</description>
              <bitOffset>7</bitOffset>
              <bitWidth>1</bitWidth>
              <access>read-write</access>
              <enumeratedValues>
                <enumeratedValue>
                  <name>0</name>
                  <description>Interrupts from SPRF and MODF are inhibited-use polling (when FIFOMODE is not present or is 0) or Read FIFO Full Interrupts are disabled (when FIFOMODE is 1)</description>
                  <value>#0</value>
                </enumeratedValue>
                <enumeratedValue>
                  <name>1</name>
                  <description>Request a hardware interrupt when SPRF or MODF is 1 (when FIFOMODE is not present or is 0) or Read FIFO Full Interrupts are enabled (when FIFOMODE is 1)</description>
                  <value>#1</value>
                </enumeratedValue>
              </enumeratedValues>
            </field>
          </fields>
        </register>
        <register>
          <name>ML</name>
          <description>SPI Match Register low</description>
          <addressOffset>0x4</addressOffset>
          <size>8</size>
          <access>read-write</access>
          <resetValue>0</resetValue>
          <resetMask>0xFF</resetMask>
          <fields>
            <field>
              <name>Bits</name>
              <description>Hardware compare value (low byte)</description>
              <bitOffset>0</bitOffset>
              <bitWidth>8</bitWidth>
              <access>read-write</access>
            </field>
          </fields>
        </register>
        <register>
          <name>MH</name>
          <description>SPI match register high</description>
          <addressOffset>0x5</addressOffset>
          <size>8</size>
          <access>read-write</access>
          <resetValue>0</resetValue>
          <resetMask>0xFF</resetMask>
          <fields>
            <field>
              <name>Bits</name>
              <description>Hardware compare value (high byte)</description>
              <bitOffset>0</bitOffset>
              <bitWidth>8</bitWidth>
              <access>read-write</access>
            </field>
          </fields>
        </register>
        <register>
          <name>DL</name>
          <description>SPI Data Register low</description>
          <addressOffset>0x6</addressOffset>
          <size>8</size>
          <access>read-write</access>
          <resetValue>0</resetValue>
          <resetMask>0xFF</resetMask>
          <fields>
            <field>
              <name>Bits</name>
              <description>Data (low byte)</description>
              <bitOffset>0</bitOffset>
              <bitWidth>8</bitWidth>
              <access>read-write</access>
            </field>
          </fields>
        </register>
        <register>
          <name>DH</name>
          <description>SPI data register high</description>
          <addressOffset>0x7</addressOffset>
          <size>8</size>
          <access>read-write</access>
          <resetValue>0</resetValue>
          <resetMask>0xFF</resetMask>
          <fields>
            <field>
              <name>Bits</name>
              <description>Data (high byte)</description>
              <bitOffset>0</bitOffset>
              <bitWidth>8</bitWidth>
              <access>read-write</access>
            </field>
          </fields>
        </register>
      </registers>
    </peripheral>
    <peripheral>
      <name>SPI1</name>
      <description>Serial Peripheral Interface</description>
      <groupName>SPI</groupName>
      <prependToName>SPI1_</prependToName>
      <baseAddress>0x40077000</baseAddress>
      <addressBlock>
        <offset>0</offset>
        <size>0xC</size>
        <usage>registers</usage>
      </addressBlock>
      <interrupt>
        <name>SPI1</name>
        <value>11</value>
      </interrupt>
      <registers>
        <register>
          <name>S</name>
          <description>SPI Status Register</description>
          <addressOffset>0</addressOffset>
          <size>8</size>
          <access>read-write</access>
          <resetValue>0x20</resetValue>
          <resetMask>0xFF</resetMask>
          <fields>
            <field>
              <name>RFIFOEF</name>
              <description>SPI read FIFO empty flag</description>
              <bitOffset>0</bitOffset>
              <bitWidth>1</bitWidth>
              <access>read-only</access>
              <enumeratedValues>
                <enumeratedValue>
                  <name>0</name>
                  <description>Read FIFO has data. Reads of the DH:DL registers in 16-bit mode or the DL register in 8-bit mode will empty the read FIFO.</description>
                  <value>#0</value>
                </enumeratedValue>
                <enumeratedValue>
                  <name>1</name>
                  <description>Read FIFO is empty.</description>
                  <value>#1</value>
                </enumeratedValue>
              </enumeratedValues>
            </field>
            <field>
              <name>TXFULLF</name>
              <description>Transmit FIFO full flag</description>
              <bitOffset>1</bitOffset>
              <bitWidth>1</bitWidth>
              <access>read-only</access>
              <enumeratedValues>
                <enumeratedValue>
                  <name>0</name>
                  <description>Transmit FIFO has less than 8 bytes</description>
                  <value>#0</value>
                </enumeratedValue>
                <enumeratedValue>
                  <name>1</name>
                  <description>Transmit FIFO has 8 bytes of data</description>
                  <value>#1</value>
                </enumeratedValue>
              </enumeratedValues>
            </field>
            <field>
              <name>TNEAREF</name>
              <description>Transmit FIFO nearly empty flag</description>
              <bitOffset>2</bitOffset>
              <bitWidth>1</bitWidth>
              <access>read-only</access>
              <enumeratedValues>
                <enumeratedValue>
                  <name>0</name>
                  <description>Transmit FIFO has more than 16 bits (when C3[TNEAREF_MARK] is 0) or more than 32 bits (when C3[TNEAREF_MARK] is 1) remaining to transmit</description>
                  <value>#0</value>
                </enumeratedValue>
                <enumeratedValue>
                  <name>1</name>
                  <description>Transmit FIFO has an amount of data equal to or less than 16 bits (when C3[TNEAREF_MARK] is 0) or 32 bits (when C3[TNEAREF_MARK] is 1) remaining to transmit</description>
                  <value>#1</value>
                </enumeratedValue>
              </enumeratedValues>
            </field>
            <field>
              <name>RNFULLF</name>
              <description>Receive FIFO nearly full flag</description>
              <bitOffset>3</bitOffset>
              <bitWidth>1</bitWidth>
              <access>read-only</access>
              <enumeratedValues>
                <enumeratedValue>
                  <name>0</name>
                  <description>Receive FIFO has received less than 48 bits (when C3[RNFULLF_MARK] is 0) or less than 32 bits (when C3[RNFULLF_MARK] is 1)</description>
                  <value>#0</value>
                </enumeratedValue>
                <enumeratedValue>
                  <name>1</name>
                  <description>Receive FIFO has received data of an amount equal to or greater than 48 bits (when C3[RNFULLF_MARK] is 0) or 32 bits (when C3[RNFULLF_MARK] is 1)</description>
                  <value>#1</value>
                </enumeratedValue>
              </enumeratedValues>
            </field>
            <field>
              <name>MODF</name>
              <description>Master Mode Fault Flag</description>
              <bitOffset>4</bitOffset>
              <bitWidth>1</bitWidth>
              <access>read-only</access>
              <enumeratedValues>
                <enumeratedValue>
                  <name>0</name>
                  <description>No mode fault error</description>
                  <value>#0</value>
                </enumeratedValue>
                <enumeratedValue>
                  <name>1</name>
                  <description>Mode fault error detected</description>
                  <value>#1</value>
                </enumeratedValue>
              </enumeratedValues>
            </field>
            <field>
              <name>SPTEF</name>
              <description>SPI Transmit Buffer Empty Flag (when FIFO is not supported or not enabled) or SPI transmit FIFO empty flag (when FIFO is supported and enabled)</description>
              <bitOffset>5</bitOffset>
              <bitWidth>1</bitWidth>
              <access>read-only</access>
              <enumeratedValues>
                <enumeratedValue>
                  <name>0</name>
                  <description>SPI transmit buffer not empty (when FIFOMODE is not present or is 0) or SPI FIFO not empty (when FIFOMODE is 1)</description>
                  <value>#0</value>
                </enumeratedValue>
                <enumeratedValue>
                  <name>1</name>
                  <description>SPI transmit buffer empty (when FIFOMODE is not present or is 0) or SPI FIFO empty (when FIFOMODE is 1)</description>
                  <value>#1</value>
                </enumeratedValue>
              </enumeratedValues>
            </field>
            <field>
              <name>SPMF</name>
              <description>SPI Match Flag</description>
              <bitOffset>6</bitOffset>
              <bitWidth>1</bitWidth>
              <access>read-write</access>
              <enumeratedValues>
                <enumeratedValue>
                  <name>0</name>
                  <description>Value in the receive data buffer does not match the value in the MH:ML registers</description>
                  <value>#0</value>
                </enumeratedValue>
                <enumeratedValue>
                  <name>1</name>
                  <description>Value in the receive data buffer matches the value in the MH:ML registers</description>
                  <value>#1</value>
                </enumeratedValue>
              </enumeratedValues>
            </field>
            <field>
              <name>SPRF</name>
              <description>SPI Read Buffer Full Flag (when FIFO is not supported or not enabled) or SPI read FIFO FULL flag (when FIFO is supported and enabled)</description>
              <bitOffset>7</bitOffset>
              <bitWidth>1</bitWidth>
              <access>read-only</access>
              <enumeratedValues>
                <enumeratedValue>
                  <name>0</name>
                  <description>No data available in the receive data buffer (when FIFOMODE is not present or is 0) or Read FIFO is not full (when FIFOMODE is 1)</description>
                  <value>#0</value>
                </enumeratedValue>
                <enumeratedValue>
                  <name>1</name>
                  <description>Data available in the receive data buffer (when FIFOMODE is not present or is 0) or Read FIFO is full (when FIFOMODE is 1)</description>
                  <value>#1</value>
                </enumeratedValue>
              </enumeratedValues>
            </field>
          </fields>
        </register>
        <register>
          <name>BR</name>
          <description>SPI Baud Rate Register</description>
          <addressOffset>0x1</addressOffset>
          <size>8</size>
          <access>read-write</access>
          <resetValue>0</resetValue>
          <resetMask>0xFF</resetMask>
          <fields>
            <field>
              <name>SPR</name>
              <description>SPI Baud Rate Divisor</description>
              <bitOffset>0</bitOffset>
              <bitWidth>4</bitWidth>
              <access>read-write</access>
              <enumeratedValues>
                <enumeratedValue>
                  <name>0000</name>
                  <description>Baud rate divisor is 2.</description>
                  <value>#0000</value>
                </enumeratedValue>
                <enumeratedValue>
                  <name>0001</name>
                  <description>Baud rate divisor is 4.</description>
                  <value>#0001</value>
                </enumeratedValue>
                <enumeratedValue>
                  <name>0010</name>
                  <description>Baud rate divisor is 8.</description>
                  <value>#0010</value>
                </enumeratedValue>
                <enumeratedValue>
                  <name>0011</name>
                  <description>Baud rate divisor is 16.</description>
                  <value>#0011</value>
                </enumeratedValue>
                <enumeratedValue>
                  <name>0100</name>
                  <description>Baud rate divisor is 32.</description>
                  <value>#0100</value>
                </enumeratedValue>
                <enumeratedValue>
                  <name>0101</name>
                  <description>Baud rate divisor is 64.</description>
                  <value>#0101</value>
                </enumeratedValue>
                <enumeratedValue>
                  <name>0110</name>
                  <description>Baud rate divisor is 128.</description>
                  <value>#0110</value>
                </enumeratedValue>
                <enumeratedValue>
                  <name>0111</name>
                  <description>Baud rate divisor is 256.</description>
                  <value>#0111</value>
                </enumeratedValue>
                <enumeratedValue>
                  <name>1000</name>
                  <description>Baud rate divisor is 512.</description>
                  <value>#1000</value>
                </enumeratedValue>
              </enumeratedValues>
            </field>
            <field>
              <name>SPPR</name>
              <description>SPI Baud Rate Prescale Divisor</description>
              <bitOffset>4</bitOffset>
              <bitWidth>3</bitWidth>
              <access>read-write</access>
              <enumeratedValues>
                <enumeratedValue>
                  <name>000</name>
                  <description>Baud rate prescaler divisor is 1.</description>
                  <value>#000</value>
                </enumeratedValue>
                <enumeratedValue>
                  <name>001</name>
                  <description>Baud rate prescaler divisor is 2.</description>
                  <value>#001</value>
                </enumeratedValue>
                <enumeratedValue>
                  <name>010</name>
                  <description>Baud rate prescaler divisor is 3.</description>
                  <value>#010</value>
                </enumeratedValue>
                <enumeratedValue>
                  <name>011</name>
                  <description>Baud rate prescaler divisor is 4.</description>
                  <value>#011</value>
                </enumeratedValue>
                <enumeratedValue>
                  <name>100</name>
                  <description>Baud rate prescaler divisor is 5.</description>
                  <value>#100</value>
                </enumeratedValue>
                <enumeratedValue>
                  <name>101</name>
                  <description>Baud rate prescaler divisor is 6.</description>
                  <value>#101</value>
                </enumeratedValue>
                <enumeratedValue>
                  <name>110</name>
                  <description>Baud rate prescaler divisor is 7.</description>
                  <value>#110</value>
                </enumeratedValue>
                <enumeratedValue>
                  <name>111</name>
                  <description>Baud rate prescaler divisor is 8.</description>
                  <value>#111</value>
                </enumeratedValue>
              </enumeratedValues>
            </field>
          </fields>
        </register>
        <register>
          <name>C2</name>
          <description>SPI Control Register 2</description>
          <addressOffset>0x2</addressOffset>
          <size>8</size>
          <access>read-write</access>
          <resetValue>0</resetValue>
          <resetMask>0xFF</resetMask>
          <fields>
            <field>
              <name>SPC0</name>
              <description>SPI Pin Control 0</description>
              <bitOffset>0</bitOffset>
              <bitWidth>1</bitWidth>
              <access>read-write</access>
              <enumeratedValues>
                <enumeratedValue>
                  <name>0</name>
                  <description>SPI uses separate pins for data input and data output (pin mode is normal). In master mode of operation: MISO is master in and MOSI is master out. In slave mode of operation: MISO is slave out and MOSI is slave in.</description>
                  <value>#0</value>
                </enumeratedValue>
                <enumeratedValue>
                  <name>1</name>
                  <description>SPI configured for single-wire bidirectional operation (pin mode is bidirectional). In master mode of operation: MISO is not used by SPI; MOSI is master in when BIDIROE is 0 or master I/O when BIDIROE is 1. In slave mode of operation: MISO is slave in when BIDIROE is 0 or slave I/O when BIDIROE is 1; MOSI is not used by SPI.</description>
                  <value>#1</value>
                </enumeratedValue>
              </enumeratedValues>
            </field>
            <field>
              <name>SPISWAI</name>
              <description>SPI Stop in Wait Mode</description>
              <bitOffset>1</bitOffset>
              <bitWidth>1</bitWidth>
              <access>read-write</access>
              <enumeratedValues>
                <enumeratedValue>
                  <name>0</name>
                  <description>SPI clocks continue to operate in Wait mode.</description>
                  <value>#0</value>
                </enumeratedValue>
                <enumeratedValue>
                  <name>1</name>
                  <description>SPI clocks stop when the MCU enters Wait mode.</description>
                  <value>#1</value>
                </enumeratedValue>
              </enumeratedValues>
            </field>
            <field>
              <name>RXDMAE</name>
              <description>Receive DMA enable</description>
              <bitOffset>2</bitOffset>
              <bitWidth>1</bitWidth>
              <access>read-write</access>
              <enumeratedValues>
                <enumeratedValue>
                  <name>0</name>
                  <description>DMA request for receive is disabled and interrupt from SPRF is allowed</description>
                  <value>#0</value>
                </enumeratedValue>
                <enumeratedValue>
                  <name>1</name>
                  <description>DMA request for receive is enabled and interrupt from SPRF is disabled</description>
                  <value>#1</value>
                </enumeratedValue>
              </enumeratedValues>
            </field>
            <field>
              <name>BIDIROE</name>
              <description>Bidirectional Mode Output Enable</description>
              <bitOffset>3</bitOffset>
              <bitWidth>1</bitWidth>
              <access>read-write</access>
              <enumeratedValues>
                <enumeratedValue>
                  <name>0</name>
                  <description>Output driver disabled so SPI data I/O pin acts as an input</description>
                  <value>#0</value>
                </enumeratedValue>
                <enumeratedValue>
                  <name>1</name>
                  <description>SPI I/O pin enabled as an output</description>
                  <value>#1</value>
                </enumeratedValue>
              </enumeratedValues>
            </field>
            <field>
              <name>MODFEN</name>
              <description>Master Mode-Fault Function Enable</description>
              <bitOffset>4</bitOffset>
              <bitWidth>1</bitWidth>
              <access>read-write</access>
              <enumeratedValues>
                <enumeratedValue>
                  <name>0</name>
                  <description>Mode fault function disabled, master SS pin reverts to general-purpose I/O not controlled by SPI</description>
                  <value>#0</value>
                </enumeratedValue>
                <enumeratedValue>
                  <name>1</name>
                  <description>Mode fault function enabled, master SS pin acts as the mode fault input or the slave select output</description>
                  <value>#1</value>
                </enumeratedValue>
              </enumeratedValues>
            </field>
            <field>
              <name>TXDMAE</name>
              <description>Transmit DMA enable</description>
              <bitOffset>5</bitOffset>
              <bitWidth>1</bitWidth>
              <access>read-write</access>
              <enumeratedValues>
                <enumeratedValue>
                  <name>0</name>
                  <description>DMA request for transmit is disabled and interrupt from SPTEF is allowed</description>
                  <value>#0</value>
                </enumeratedValue>
                <enumeratedValue>
                  <name>1</name>
                  <description>DMA request for transmit is enabled and interrupt from SPTEF is disabled</description>
                  <value>#1</value>
                </enumeratedValue>
              </enumeratedValues>
            </field>
            <field>
              <name>SPIMODE</name>
              <description>SPI 8-bit or 16-bit mode</description>
              <bitOffset>6</bitOffset>
              <bitWidth>1</bitWidth>
              <access>read-write</access>
              <enumeratedValues>
                <enumeratedValue>
                  <name>0</name>
                  <description>8-bit SPI shift register, match register, and buffers</description>
                  <value>#0</value>
                </enumeratedValue>
                <enumeratedValue>
                  <name>1</name>
                  <description>16-bit SPI shift register, match register, and buffers</description>
                  <value>#1</value>
                </enumeratedValue>
              </enumeratedValues>
            </field>
            <field>
              <name>SPMIE</name>
              <description>SPI Match Interrupt Enable</description>
              <bitOffset>7</bitOffset>
              <bitWidth>1</bitWidth>
              <access>read-write</access>
              <enumeratedValues>
                <enumeratedValue>
                  <name>0</name>
                  <description>Interrupts from SPMF inhibited (use polling)</description>
                  <value>#0</value>
                </enumeratedValue>
                <enumeratedValue>
                  <name>1</name>
                  <description>When SPMF is 1, requests a hardware interrupt</description>
                  <value>#1</value>
                </enumeratedValue>
              </enumeratedValues>
            </field>
          </fields>
        </register>
        <register>
          <name>C1</name>
          <description>SPI Control Register 1</description>
          <addressOffset>0x3</addressOffset>
          <size>8</size>
          <access>read-write</access>
          <resetValue>0x4</resetValue>
          <resetMask>0xFF</resetMask>
          <fields>
            <field>
              <name>LSBFE</name>
              <description>LSB First (shifter direction)</description>
              <bitOffset>0</bitOffset>
              <bitWidth>1</bitWidth>
              <access>read-write</access>
              <enumeratedValues>
                <enumeratedValue>
                  <name>0</name>
                  <description>SPI serial data transfers start with the most significant bit.</description>
                  <value>#0</value>
                </enumeratedValue>
                <enumeratedValue>
                  <name>1</name>
                  <description>SPI serial data transfers start with the least significant bit.</description>
                  <value>#1</value>
                </enumeratedValue>
              </enumeratedValues>
            </field>
            <field>
              <name>SSOE</name>
              <description>Slave Select Output Enable</description>
              <bitOffset>1</bitOffset>
              <bitWidth>1</bitWidth>
              <access>read-write</access>
              <enumeratedValues>
                <enumeratedValue>
                  <name>0</name>
                  <description>When C2[MODFEN] is 0: In master mode, SS pin function is general-purpose I/O (not SPI). In slave mode, SS pin function is slave select input. When C2[MODFEN] is 1: In master mode, SS pin function is SS input for mode fault. In slave mode, SS pin function is slave select input.</description>
                  <value>#0</value>
                </enumeratedValue>
                <enumeratedValue>
                  <name>1</name>
                  <description>When C2[MODFEN] is 0: In master mode, SS pin function is general-purpose I/O (not SPI). In slave mode, SS pin function is slave select input. When C2[MODFEN] is 1: In master mode, SS pin function is automatic SS output. In slave mode: SS pin function is slave select input.</description>
                  <value>#1</value>
                </enumeratedValue>
              </enumeratedValues>
            </field>
            <field>
              <name>CPHA</name>
              <description>Clock Phase</description>
              <bitOffset>2</bitOffset>
              <bitWidth>1</bitWidth>
              <access>read-write</access>
              <enumeratedValues>
                <enumeratedValue>
                  <name>0</name>
                  <description>First edge on SPSCK occurs at the middle of the first cycle of a data transfer.</description>
                  <value>#0</value>
                </enumeratedValue>
                <enumeratedValue>
                  <name>1</name>
                  <description>First edge on SPSCK occurs at the start of the first cycle of a data transfer.</description>
                  <value>#1</value>
                </enumeratedValue>
              </enumeratedValues>
            </field>
            <field>
              <name>CPOL</name>
              <description>Clock Polarity</description>
              <bitOffset>3</bitOffset>
              <bitWidth>1</bitWidth>
              <access>read-write</access>
              <enumeratedValues>
                <enumeratedValue>
                  <name>0</name>
                  <description>Active-high SPI clock (idles low)</description>
                  <value>#0</value>
                </enumeratedValue>
                <enumeratedValue>
                  <name>1</name>
                  <description>Active-low SPI clock (idles high)</description>
                  <value>#1</value>
                </enumeratedValue>
              </enumeratedValues>
            </field>
            <field>
              <name>MSTR</name>
              <description>Master/Slave Mode Select</description>
              <bitOffset>4</bitOffset>
              <bitWidth>1</bitWidth>
              <access>read-write</access>
              <enumeratedValues>
                <enumeratedValue>
                  <name>0</name>
                  <description>SPI module configured as a slave SPI device</description>
                  <value>#0</value>
                </enumeratedValue>
                <enumeratedValue>
                  <name>1</name>
                  <description>SPI module configured as a master SPI device</description>
                  <value>#1</value>
                </enumeratedValue>
              </enumeratedValues>
            </field>
            <field>
              <name>SPTIE</name>
              <description>SPI Transmit Interrupt Enable</description>
              <bitOffset>5</bitOffset>
              <bitWidth>1</bitWidth>
              <access>read-write</access>
              <enumeratedValues>
                <enumeratedValue>
                  <name>0</name>
                  <description>Interrupts from SPTEF inhibited (use polling)</description>
                  <value>#0</value>
                </enumeratedValue>
                <enumeratedValue>
                  <name>1</name>
                  <description>When SPTEF is 1, hardware interrupt requested</description>
                  <value>#1</value>
                </enumeratedValue>
              </enumeratedValues>
            </field>
            <field>
              <name>SPE</name>
              <description>SPI System Enable</description>
              <bitOffset>6</bitOffset>
              <bitWidth>1</bitWidth>
              <access>read-write</access>
              <enumeratedValues>
                <enumeratedValue>
                  <name>0</name>
                  <description>SPI system inactive</description>
                  <value>#0</value>
                </enumeratedValue>
                <enumeratedValue>
                  <name>1</name>
                  <description>SPI system enabled</description>
                  <value>#1</value>
                </enumeratedValue>
              </enumeratedValues>
            </field>
            <field>
              <name>SPIE</name>
              <description>SPI Interrupt Enable: for SPRF and MODF (when FIFO is not supported or not enabled) or for read FIFO (when FIFO is supported and enabled)</description>
              <bitOffset>7</bitOffset>
              <bitWidth>1</bitWidth>
              <access>read-write</access>
              <enumeratedValues>
                <enumeratedValue>
                  <name>0</name>
                  <description>Interrupts from SPRF and MODF are inhibited-use polling (when FIFOMODE is not present or is 0) or Read FIFO Full Interrupts are disabled (when FIFOMODE is 1)</description>
                  <value>#0</value>
                </enumeratedValue>
                <enumeratedValue>
                  <name>1</name>
                  <description>Request a hardware interrupt when SPRF or MODF is 1 (when FIFOMODE is not present or is 0) or Read FIFO Full Interrupts are enabled (when FIFOMODE is 1)</description>
                  <value>#1</value>
                </enumeratedValue>
              </enumeratedValues>
            </field>
          </fields>
        </register>
        <register>
          <name>ML</name>
          <description>SPI Match Register low</description>
          <addressOffset>0x4</addressOffset>
          <size>8</size>
          <access>read-write</access>
          <resetValue>0</resetValue>
          <resetMask>0xFF</resetMask>
          <fields>
            <field>
              <name>Bits</name>
              <description>Hardware compare value (low byte)</description>
              <bitOffset>0</bitOffset>
              <bitWidth>8</bitWidth>
              <access>read-write</access>
            </field>
          </fields>
        </register>
        <register>
          <name>MH</name>
          <description>SPI match register high</description>
          <addressOffset>0x5</addressOffset>
          <size>8</size>
          <access>read-write</access>
          <resetValue>0</resetValue>
          <resetMask>0xFF</resetMask>
          <fields>
            <field>
              <name>Bits</name>
              <description>Hardware compare value (high byte)</description>
              <bitOffset>0</bitOffset>
              <bitWidth>8</bitWidth>
              <access>read-write</access>
            </field>
          </fields>
        </register>
        <register>
          <name>DL</name>
          <description>SPI Data Register low</description>
          <addressOffset>0x6</addressOffset>
          <size>8</size>
          <access>read-write</access>
          <resetValue>0</resetValue>
          <resetMask>0xFF</resetMask>
          <fields>
            <field>
              <name>Bits</name>
              <description>Data (low byte)</description>
              <bitOffset>0</bitOffset>
              <bitWidth>8</bitWidth>
              <access>read-write</access>
            </field>
          </fields>
        </register>
        <register>
          <name>DH</name>
          <description>SPI data register high</description>
          <addressOffset>0x7</addressOffset>
          <size>8</size>
          <access>read-write</access>
          <resetValue>0</resetValue>
          <resetMask>0xFF</resetMask>
          <fields>
            <field>
              <name>Bits</name>
              <description>Data (high byte)</description>
              <bitOffset>0</bitOffset>
              <bitWidth>8</bitWidth>
              <access>read-write</access>
            </field>
          </fields>
        </register>
        <register>
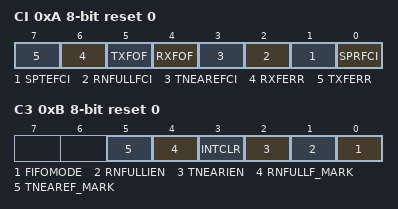
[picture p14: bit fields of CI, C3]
          <name>CI</name>
          <description>SPI clear interrupt register</description>
          <addressOffset>0xA</addressOffset>
          <size>8</size>
          <access>read-write</access>
          <resetValue>0</resetValue>
          <resetMask>0xFF</resetMask>
          <fields>
            <field>
              <name>SPRFCI</name>
              <description>Receive FIFO full flag clear interrupt</description>
              <bitOffset>0</bitOffset>
              <bitWidth>1</bitWidth>
              <access>write-only</access>
            </field>
            <field>
              <name>SPTEFCI</name>
              <description>Transmit FIFO empty flag clear interrupt</description>
              <bitOffset>1</bitOffset>
              <bitWidth>1</bitWidth>
              <access>write-only</access>
            </field>
            <field>
              <name>RNFULLFCI</name>
              <description>Receive FIFO nearly full flag clear interrupt</description>
              <bitOffset>2</bitOffset>
              <bitWidth>1</bitWidth>
              <access>write-only</access>
            </field>
            <field>
              <name>TNEAREFCI</name>
              <description>Transmit FIFO nearly empty flag clear interrupt</description>
              <bitOffset>3</bitOffset>
              <bitWidth>1</bitWidth>
              <access>write-only</access>
            </field>
            <field>
              <name>RXFOF</name>
              <description>Receive FIFO overflow flag</description>
              <bitOffset>4</bitOffset>
              <bitWidth>1</bitWidth>
              <access>read-only</access>
              <enumeratedValues>
                <enumeratedValue>
                  <name>0</name>
                  <description>Receive FIFO overflow condition has not occurred</description>
                  <value>#0</value>
                </enumeratedValue>
                <enumeratedValue>
                  <name>1</name>
                  <description>Receive FIFO overflow condition occurred</description>
                  <value>#1</value>
                </enumeratedValue>
              </enumeratedValues>
            </field>
            <field>
              <name>TXFOF</name>
              <description>Transmit FIFO overflow flag</description>
              <bitOffset>5</bitOffset>
              <bitWidth>1</bitWidth>
              <access>read-only</access>
              <enumeratedValues>
                <enumeratedValue>
                  <name>0</name>
                  <description>Transmit FIFO overflow condition has not occurred</description>
                  <value>#0</value>
                </enumeratedValue>
                <enumeratedValue>
                  <name>1</name>
                  <description>Transmit FIFO overflow condition occurred</description>
                  <value>#1</value>
                </enumeratedValue>
              </enumeratedValues>
            </field>
            <field>
              <name>RXFERR</name>
              <description>Receive FIFO error flag</description>
              <bitOffset>6</bitOffset>
              <bitWidth>1</bitWidth>
              <access>read-only</access>
              <enumeratedValues>
                <enumeratedValue>
                  <name>0</name>
                  <description>No receive FIFO error occurred</description>
                  <value>#0</value>
                </enumeratedValue>
                <enumeratedValue>
                  <name>1</name>
                  <description>A receive FIFO error occurred</description>
                  <value>#1</value>
                </enumeratedValue>
              </enumeratedValues>
            </field>
            <field>
              <name>TXFERR</name>
              <description>Transmit FIFO error flag</description>
              <bitOffset>7</bitOffset>
              <bitWidth>1</bitWidth>
              <access>read-only</access>
              <enumeratedValues>
                <enumeratedValue>
                  <name>0</name>
                  <description>No transmit FIFO error occurred</description>
                  <value>#0</value>
                </enumeratedValue>
                <enumeratedValue>
                  <name>1</name>
                  <description>A transmit FIFO error occurred</description>
                  <value>#1</value>
                </enumeratedValue>
              </enumeratedValues>
            </field>
          </fields>
        </register>
        <register>
          <name>C3</name>
          <description>SPI control register 3</description>
          <addressOffset>0xB</addressOffset>
          <size>8</size>
          <access>read-write</access>
          <resetValue>0</resetValue>
          <resetMask>0xFF</resetMask>
          <fields>
            <field>
              <name>FIFOMODE</name>
              <description>FIFO mode enable</description>
              <bitOffset>0</bitOffset>
              <bitWidth>1</bitWidth>
              <access>read-write</access>
              <enumeratedValues>
                <enumeratedValue>
                  <name>0</name>
                  <description>Buffer mode disabled</description>
                  <value>#0</value>
                </enumeratedValue>
                <enumeratedValue>
                  <name>1</name>
                  <description>Data available in the receive data buffer</description>
                  <value>#1</value>
                </enumeratedValue>
              </enumeratedValues>
            </field>
            <field>
              <name>RNFULLIEN</name>
              <description>Receive FIFO nearly full interrupt enable</description>
              <bitOffset>1</bitOffset>
              <bitWidth>1</bitWidth>
              <access>read-write</access>
              <enumeratedValues>
                <enumeratedValue>
                  <name>0</name>
                  <description>No interrupt upon RNFULLF being set</description>
                  <value>#0</value>
                </enumeratedValue>
                <enumeratedValue>
                  <name>1</name>
                  <description>Enable interrupts upon RNFULLF being set</description>
                  <value>#1</value>
                </enumeratedValue>
              </enumeratedValues>
            </field>
            <field>
              <name>TNEARIEN</name>
              <description>Transmit FIFO nearly empty interrupt enable</description>
              <bitOffset>2</bitOffset>
              <bitWidth>1</bitWidth>
              <access>read-write</access>
              <enumeratedValues>
                <enumeratedValue>
                  <name>0</name>
                  <description>No interrupt upon TNEAREF being set</description>
                  <value>#0</value>
                </enumeratedValue>
                <enumeratedValue>
                  <name>1</name>
                  <description>Enable interrupts upon TNEAREF being set</description>
                  <value>#1</value>
                </enumeratedValue>
              </enumeratedValues>
            </field>
            <field>
              <name>INTCLR</name>
              <description>Interrupt clearing mechanism select</description>
              <bitOffset>3</bitOffset>
              <bitWidth>1</bitWidth>
              <access>read-write</access>
              <enumeratedValues>
                <enumeratedValue>
                  <name>0</name>
                  <description>These interrupts are cleared when the corresponding flags are cleared depending on the state of the FIFOs</description>
                  <value>#0</value>
                </enumeratedValue>
                <enumeratedValue>
                  <name>1</name>
                  <description>These interrupts are cleared by writing the corresponding bits in the CI register</description>
                  <value>#1</value>
                </enumeratedValue>
              </enumeratedValues>
            </field>
            <field>
              <name>RNFULLF_MARK</name>
              <description>Receive FIFO nearly full watermark</description>
              <bitOffset>4</bitOffset>
              <bitWidth>1</bitWidth>
              <access>read-write</access>
              <enumeratedValues>
                <enumeratedValue>
                  <name>0</name>
                  <description>RNFULLF is set when the receive FIFO has 48 bits or more</description>
                  <value>#0</value>
                </enumeratedValue>
                <enumeratedValue>
                  <name>1</name>
                  <description>RNFULLF is set when the receive FIFO has 32 bits or more</description>
                  <value>#1</value>
                </enumeratedValue>
              </enumeratedValues>
            </field>
            <field>
              <name>TNEAREF_MARK</name>
              <description>Transmit FIFO nearly empty watermark</description>
              <bitOffset>5</bitOffset>
              <bitWidth>1</bitWidth>
              <access>read-write</access>
              <enumeratedValues>
                <enumeratedValue>
                  <name>0</name>
                  <description>TNEAREF is set when the transmit FIFO has 16 bits or less</description>
                  <value>#0</value>
                </enumeratedValue>
                <enumeratedValue>
                  <name>1</name>
                  <description>TNEAREF is set when the transmit FIFO has 32 bits or less</description>
                  <value>#1</value>
                </enumeratedValue>
              </enumeratedValues>
            </field>
          </fields>
        </register>
      </registers>
    </peripheral>
    <peripheral>
      <name>LLWU</name>
      <description>Low leakage wakeup unit</description>
      <prependToName>LLWU_</prependToName>
      <baseAddress>0x4007C000</baseAddress>
      <addressBlock>
        <offset>0</offset>
        <size>0xA</size>
        <usage>registers</usage>
      </addressBlock>
      <interrupt>
        <name>LLWU</name>
        <value>7</value>
      </interrupt>
      <registers>
        <register>
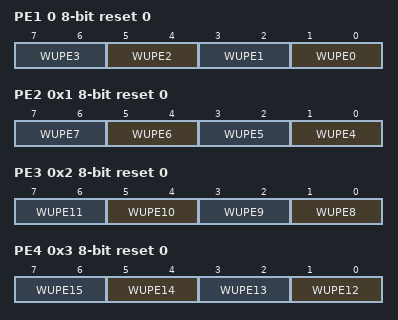
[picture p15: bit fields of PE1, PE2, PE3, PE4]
          <name>PE1</name>
          <description>LLWU Pin Enable 1 register</description>
          <addressOffset>0</addressOffset>
          <size>8</size>
          <access>read-write</access>
          <resetValue>0</resetValue>
          <resetMask>0xFF</resetMask>
          <fields>
            <field>
              <name>WUPE0</name>
              <description>Wakeup Pin Enable For LLWU_P0</description>
              <bitOffset>0</bitOffset>
              <bitWidth>2</bitWidth>
              <access>read-write</access>
              <enumeratedValues>
                <enumeratedValue>
                  <name>00</name>
                  <description>External input pin disabled as wakeup input</description>
                  <value>#00</value>
                </enumeratedValue>
                <enumeratedValue>
                  <name>01</name>
                  <description>External input pin enabled with rising edge detection</description>
                  <value>#01</value>
                </enumeratedValue>
                <enumeratedValue>
                  <name>10</name>
                  <description>External input pin enabled with falling edge detection</description>
                  <value>#10</value>
                </enumeratedValue>
                <enumeratedValue>
                  <name>11</name>
                  <description>External input pin enabled with any change detection</description>
                  <value>#11</value>
                </enumeratedValue>
              </enumeratedValues>
            </field>
            <field>
              <name>WUPE1</name>
              <description>Wakeup Pin Enable For LLWU_P1</description>
              <bitOffset>2</bitOffset>
              <bitWidth>2</bitWidth>
              <access>read-write</access>
              <enumeratedValues>
                <enumeratedValue>
                  <name>00</name>
                  <description>External input pin disabled as wakeup input</description>
                  <value>#00</value>
                </enumeratedValue>
                <enumeratedValue>
                  <name>01</name>
                  <description>External input pin enabled with rising edge detection</description>
                  <value>#01</value>
                </enumeratedValue>
                <enumeratedValue>
                  <name>10</name>
                  <description>External input pin enabled with falling edge detection</description>
                  <value>#10</value>
                </enumeratedValue>
                <enumeratedValue>
                  <name>11</name>
                  <description>External input pin enabled with any change detection</description>
                  <value>#11</value>
                </enumeratedValue>
              </enumeratedValues>
            </field>
            <field>
              <name>WUPE2</name>
              <description>Wakeup Pin Enable For LLWU_P2</description>
              <bitOffset>4</bitOffset>
              <bitWidth>2</bitWidth>
              <access>read-write</access>
              <enumeratedValues>
                <enumeratedValue>
                  <name>00</name>
                  <description>External input pin disabled as wakeup input</description>
                  <value>#00</value>
                </enumeratedValue>
                <enumeratedValue>
                  <name>01</name>
                  <description>External input pin enabled with rising edge detection</description>
                  <value>#01</value>
                </enumeratedValue>
                <enumeratedValue>
                  <name>10</name>
                  <description>External input pin enabled with falling edge detection</description>
                  <value>#10</value>
                </enumeratedValue>
                <enumeratedValue>
                  <name>11</name>
                  <description>External input pin enabled with any change detection</description>
                  <value>#11</value>
                </enumeratedValue>
              </enumeratedValues>
            </field>
            <field>
              <name>WUPE3</name>
              <description>Wakeup Pin Enable For LLWU_P3</description>
              <bitOffset>6</bitOffset>
              <bitWidth>2</bitWidth>
              <access>read-write</access>
              <enumeratedValues>
                <enumeratedValue>
                  <name>00</name>
                  <description>External input pin disabled as wakeup input</description>
                  <value>#00</value>
                </enumeratedValue>
                <enumeratedValue>
                  <name>01</name>
                  <description>External input pin enabled with rising edge detection</description>
                  <value>#01</value>
                </enumeratedValue>
                <enumeratedValue>
                  <name>10</name>
                  <description>External input pin enabled with falling edge detection</description>
                  <value>#10</value>
                </enumeratedValue>
                <enumeratedValue>
                  <name>11</name>
                  <description>External input pin enabled with any change detection</description>
                  <value>#11</value>
                </enumeratedValue>
              </enumeratedValues>
            </field>
          </fields>
        </register>
        <register>
          <name>PE2</name>
          <description>LLWU Pin Enable 2 register</description>
          <addressOffset>0x1</addressOffset>
          <size>8</size>
          <access>read-write</access>
          <resetValue>0</resetValue>
          <resetMask>0xFF</resetMask>
          <fields>
            <field>
              <name>WUPE4</name>
              <description>Wakeup Pin Enable For LLWU_P4</description>
              <bitOffset>0</bitOffset>
              <bitWidth>2</bitWidth>
              <access>read-write</access>
              <enumeratedValues>
                <enumeratedValue>
                  <name>00</name>
                  <description>External input pin disabled as wakeup input</description>
                  <value>#00</value>
                </enumeratedValue>
                <enumeratedValue>
                  <name>01</name>
                  <description>External input pin enabled with rising edge detection</description>
                  <value>#01</value>
                </enumeratedValue>
                <enumeratedValue>
                  <name>10</name>
                  <description>External input pin enabled with falling edge detection</description>
                  <value>#10</value>
                </enumeratedValue>
                <enumeratedValue>
                  <name>11</name>
                  <description>External input pin enabled with any change detection</description>
                  <value>#11</value>
                </enumeratedValue>
              </enumeratedValues>
            </field>
            <field>
              <name>WUPE5</name>
              <description>Wakeup Pin Enable For LLWU_P5</description>
              <bitOffset>2</bitOffset>
              <bitWidth>2</bitWidth>
              <access>read-write</access>
              <enumeratedValues>
                <enumeratedValue>
                  <name>00</name>
                  <description>External input pin disabled as wakeup input</description>
                  <value>#00</value>
                </enumeratedValue>
                <enumeratedValue>
                  <name>01</name>
                  <description>External input pin enabled with rising edge detection</description>
                  <value>#01</value>
                </enumeratedValue>
                <enumeratedValue>
                  <name>10</name>
                  <description>External input pin enabled with falling edge detection</description>
                  <value>#10</value>
                </enumeratedValue>
                <enumeratedValue>
                  <name>11</name>
                  <description>External input pin enabled with any change detection</description>
                  <value>#11</value>
                </enumeratedValue>
              </enumeratedValues>
            </field>
            <field>
              <name>WUPE6</name>
              <description>Wakeup Pin Enable For LLWU_P6</description>
              <bitOffset>4</bitOffset>
              <bitWidth>2</bitWidth>
              <access>read-write</access>
              <enumeratedValues>
                <enumeratedValue>
                  <name>00</name>
                  <description>External input pin disabled as wakeup input</description>
                  <value>#00</value>
                </enumeratedValue>
                <enumeratedValue>
                  <name>01</name>
                  <description>External input pin enabled with rising edge detection</description>
                  <value>#01</value>
                </enumeratedValue>
                <enumeratedValue>
                  <name>10</name>
                  <description>External input pin enabled with falling edge detection</description>
                  <value>#10</value>
                </enumeratedValue>
                <enumeratedValue>
                  <name>11</name>
                  <description>External input pin enabled with any change detection</description>
                  <value>#11</value>
                </enumeratedValue>
              </enumeratedValues>
            </field>
            <field>
              <name>WUPE7</name>
              <description>Wakeup Pin Enable For LLWU_P7</description>
              <bitOffset>6</bitOffset>
              <bitWidth>2</bitWidth>
              <access>read-write</access>
              <enumeratedValues>
                <enumeratedValue>
                  <name>00</name>
                  <description>External input pin disabled as wakeup input</description>
                  <value>#00</value>
                </enumeratedValue>
                <enumeratedValue>
                  <name>01</name>
                  <description>External input pin enabled with rising edge detection</description>
                  <value>#01</value>
                </enumeratedValue>
                <enumeratedValue>
                  <name>10</name>
                  <description>External input pin enabled with falling edge detection</description>
                  <value>#10</value>
                </enumeratedValue>
                <enumeratedValue>
                  <name>11</name>
                  <description>External input pin enabled with any change detection</description>
                  <value>#11</value>
                </enumeratedValue>
              </enumeratedValues>
            </field>
          </fields>
        </register>
        <register>
          <name>PE3</name>
          <description>LLWU Pin Enable 3 register</description>
          <addressOffset>0x2</addressOffset>
          <size>8</size>
          <access>read-write</access>
          <resetValue>0</resetValue>
          <resetMask>0xFF</resetMask>
          <fields>
            <field>
              <name>WUPE8</name>
              <description>Wakeup Pin Enable For LLWU_P8</description>
              <bitOffset>0</bitOffset>
              <bitWidth>2</bitWidth>
              <access>read-write</access>
              <enumeratedValues>
                <enumeratedValue>
                  <name>00</name>
                  <description>External input pin disabled as wakeup input</description>
                  <value>#00</value>
                </enumeratedValue>
                <enumeratedValue>
                  <name>01</name>
                  <description>External input pin enabled with rising edge detection</description>
                  <value>#01</value>
                </enumeratedValue>
                <enumeratedValue>
                  <name>10</name>
                  <description>External input pin enabled with falling edge detection</description>
                  <value>#10</value>
                </enumeratedValue>
                <enumeratedValue>
                  <name>11</name>
                  <description>External input pin enabled with any change detection</description>
                  <value>#11</value>
                </enumeratedValue>
              </enumeratedValues>
            </field>
            <field>
              <name>WUPE9</name>
              <description>Wakeup Pin Enable For LLWU_P9</description>
              <bitOffset>2</bitOffset>
              <bitWidth>2</bitWidth>
              <access>read-write</access>
              <enumeratedValues>
                <enumeratedValue>
                  <name>00</name>
                  <description>External input pin disabled as wakeup input</description>
                  <value>#00</value>
                </enumeratedValue>
                <enumeratedValue>
                  <name>01</name>
                  <description>External input pin enabled with rising edge detection</description>
                  <value>#01</value>
                </enumeratedValue>
                <enumeratedValue>
                  <name>10</name>
                  <description>External input pin enabled with falling edge detection</description>
                  <value>#10</value>
                </enumeratedValue>
                <enumeratedValue>
                  <name>11</name>
                  <description>External input pin enabled with any change detection</description>
                  <value>#11</value>
                </enumeratedValue>
              </enumeratedValues>
            </field>
            <field>
              <name>WUPE10</name>
              <description>Wakeup Pin Enable For LLWU_P10</description>
              <bitOffset>4</bitOffset>
              <bitWidth>2</bitWidth>
              <access>read-write</access>
              <enumeratedValues>
                <enumeratedValue>
                  <name>00</name>
                  <description>External input pin disabled as wakeup input</description>
                  <value>#00</value>
                </enumeratedValue>
                <enumeratedValue>
                  <name>01</name>
                  <description>External input pin enabled with rising edge detection</description>
                  <value>#01</value>
                </enumeratedValue>
                <enumeratedValue>
                  <name>10</name>
                  <description>External input pin enabled with falling edge detection</description>
                  <value>#10</value>
                </enumeratedValue>
                <enumeratedValue>
                  <name>11</name>
                  <description>External input pin enabled with any change detection</description>
                  <value>#11</value>
                </enumeratedValue>
              </enumeratedValues>
            </field>
            <field>
              <name>WUPE11</name>
              <description>Wakeup Pin Enable For LLWU_P11</description>
              <bitOffset>6</bitOffset>
              <bitWidth>2</bitWidth>
              <access>read-write</access>
              <enumeratedValues>
                <enumeratedValue>
                  <name>00</name>
                  <description>External input pin disabled as wakeup input</description>
                  <value>#00</value>
                </enumeratedValue>
                <enumeratedValue>
                  <name>01</name>
                  <description>External input pin enabled with rising edge detection</description>
                  <value>#01</value>
                </enumeratedValue>
                <enumeratedValue>
                  <name>10</name>
                  <description>External input pin enabled with falling edge detection</description>
                  <value>#10</value>
                </enumeratedValue>
                <enumeratedValue>
                  <name>11</name>
                  <description>External input pin enabled with any change detection</description>
                  <value>#11</value>
                </enumeratedValue>
              </enumeratedValues>
            </field>
          </fields>
        </register>
        <register>
          <name>PE4</name>
          <description>LLWU Pin Enable 4 register</description>
          <addressOffset>0x3</addressOffset>
          <size>8</size>
          <access>read-write</access>
          <resetValue>0</resetValue>
          <resetMask>0xFF</resetMask>
          <fields>
            <field>
              <name>WUPE12</name>
              <description>Wakeup Pin Enable For LLWU_P12</description>
              <bitOffset>0</bitOffset>
              <bitWidth>2</bitWidth>
              <access>read-write</access>
              <enumeratedValues>
                <enumeratedValue>
                  <name>00</name>
                  <description>External input pin disabled as wakeup input</description>
                  <value>#00</value>
                </enumeratedValue>
                <enumeratedValue>
                  <name>01</name>
                  <description>External input pin enabled with rising edge detection</description>
                  <value>#01</value>
                </enumeratedValue>
                <enumeratedValue>
                  <name>10</name>
                  <description>External input pin enabled with falling edge detection</description>
                  <value>#10</value>
                </enumeratedValue>
                <enumeratedValue>
                  <name>11</name>
                  <description>External input pin enabled with any change detection</description>
                  <value>#11</value>
                </enumeratedValue>
              </enumeratedValues>
            </field>
            <field>
              <name>WUPE13</name>
              <description>Wakeup Pin Enable For LLWU_P13</description>
              <bitOffset>2</bitOffset>
              <bitWidth>2</bitWidth>
              <access>read-write</access>
              <enumeratedValues>
                <enumeratedValue>
                  <name>00</name>
                  <description>External input pin disabled as wakeup input</description>
                  <value>#00</value>
                </enumeratedValue>
                <enumeratedValue>
                  <name>01</name>
                  <description>External input pin enabled with rising edge detection</description>
                  <value>#01</value>
                </enumeratedValue>
                <enumeratedValue>
                  <name>10</name>
                  <description>External input pin enabled with falling edge detection</description>
                  <value>#10</value>
                </enumeratedValue>
                <enumeratedValue>
                  <name>11</name>
                  <description>External input pin enabled with any change detection</description>
                  <value>#11</value>
                </enumeratedValue>
              </enumeratedValues>
            </field>
            <field>
              <name>WUPE14</name>
              <description>Wakeup Pin Enable For LLWU_P14</description>
              <bitOffset>4</bitOffset>
              <bitWidth>2</bitWidth>
              <access>read-write</access>
              <enumeratedValues>
                <enumeratedValue>
                  <name>00</name>
                  <description>External input pin disabled as wakeup input</description>
                  <value>#00</value>
                </enumeratedValue>
                <enumeratedValue>
                  <name>01</name>
                  <description>External input pin enabled with rising edge detection</description>
                  <value>#01</value>
                </enumeratedValue>
                <enumeratedValue>
                  <name>10</name>
                  <description>External input pin enabled with falling edge detection</description>
                  <value>#10</value>
                </enumeratedValue>
                <enumeratedValue>
                  <name>11</name>
                  <description>External input pin enabled with any change detection</description>
                  <value>#11</value>
                </enumeratedValue>
              </enumeratedValues>
            </field>
            <field>
              <name>WUPE15</name>
              <description>Wakeup Pin Enable For LLWU_P15</description>
              <bitOffset>6</bitOffset>
              <bitWidth>2</bitWidth>
              <access>read-write</access>
              <enumeratedValues>
                <enumeratedValue>
                  <name>00</name>
                  <description>External input pin disabled as wakeup input</description>
                  <value>#00</value>
                </enumeratedValue>
                <enumeratedValue>
                  <name>01</name>
                  <description>External input pin enabled with rising edge detection</description>
                  <value>#01</value>
                </enumeratedValue>
                <enumeratedValue>
                  <name>10</name>
                  <description>External input pin enabled with falling edge detection</description>
                  <value>#10</value>
                </enumeratedValue>
                <enumeratedValue>
                  <name>11</name>
                  <description>External input pin enabled with any change detection</description>
                  <value>#11</value>
                </enumeratedValue>
              </enumeratedValues>
            </field>
          </fields>
        </register>
        <register>
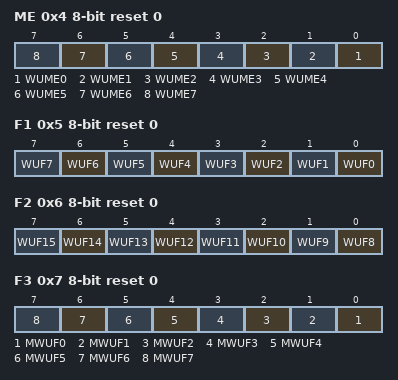
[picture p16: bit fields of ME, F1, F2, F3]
          <name>ME</name>
          <description>LLWU Module Enable register</description>
          <addressOffset>0x4</addressOffset>
          <size>8</size>
          <access>read-write</access>
          <resetValue>0</resetValue>
          <resetMask>0xFF</resetMask>
          <fields>
            <field>
              <name>WUME0</name>
              <description>Wakeup Module Enable For Module 0</description>
              <bitOffset>0</bitOffset>
              <bitWidth>1</bitWidth>
              <access>read-write</access>
              <enumeratedValues>
                <enumeratedValue>
                  <name>0</name>
                  <description>Internal module flag not used as wakeup source</description>
                  <value>#0</value>
                </enumeratedValue>
                <enumeratedValue>
                  <name>1</name>
                  <description>Internal module flag used as wakeup source</description>
                  <value>#1</value>
                </enumeratedValue>
              </enumeratedValues>
            </field>
            <field>
              <name>WUME1</name>
              <description>Wakeup Module Enable for Module 1</description>
              <bitOffset>1</bitOffset>
              <bitWidth>1</bitWidth>
              <access>read-write</access>
              <enumeratedValues>
                <enumeratedValue>
                  <name>0</name>
                  <description>Internal module flag not used as wakeup source</description>
                  <value>#0</value>
                </enumeratedValue>
                <enumeratedValue>
                  <name>1</name>
                  <description>Internal module flag used as wakeup source</description>
                  <value>#1</value>
                </enumeratedValue>
              </enumeratedValues>
            </field>
            <field>
              <name>WUME2</name>
              <description>Wakeup Module Enable For Module 2</description>
              <bitOffset>2</bitOffset>
              <bitWidth>1</bitWidth>
              <access>read-write</access>
              <enumeratedValues>
                <enumeratedValue>
                  <name>0</name>
                  <description>Internal module flag not used as wakeup source</description>
                  <value>#0</value>
                </enumeratedValue>
                <enumeratedValue>
                  <name>1</name>
                  <description>Internal module flag used as wakeup source</description>
                  <value>#1</value>
                </enumeratedValue>
              </enumeratedValues>
            </field>
            <field>
              <name>WUME3</name>
              <description>Wakeup Module Enable For Module 3</description>
              <bitOffset>3</bitOffset>
              <bitWidth>1</bitWidth>
              <access>read-write</access>
              <enumeratedValues>
                <enumeratedValue>
                  <name>0</name>
                  <description>Internal module flag not used as wakeup source</description>
                  <value>#0</value>
                </enumeratedValue>
                <enumeratedValue>
                  <name>1</name>
                  <description>Internal module flag used as wakeup source</description>
                  <value>#1</value>
                </enumeratedValue>
              </enumeratedValues>
            </field>
            <field>
              <name>WUME4</name>
              <description>Wakeup Module Enable For Module 4</description>
              <bitOffset>4</bitOffset>
              <bitWidth>1</bitWidth>
              <access>read-write</access>
              <enumeratedValues>
                <enumeratedValue>
                  <name>0</name>
                  <description>Internal module flag not used as wakeup source</description>
                  <value>#0</value>
                </enumeratedValue>
                <enumeratedValue>
                  <name>1</name>
                  <description>Internal module flag used as wakeup source</description>
                  <value>#1</value>
                </enumeratedValue>
              </enumeratedValues>
            </field>
            <field>
              <name>WUME5</name>
              <description>Wakeup Module Enable For Module 5</description>
              <bitOffset>5</bitOffset>
              <bitWidth>1</bitWidth>
              <access>read-write</access>
              <enumeratedValues>
                <enumeratedValue>
                  <name>0</name>
                  <description>Internal module flag not used as wakeup source</description>
                  <value>#0</value>
                </enumeratedValue>
                <enumeratedValue>
                  <name>1</name>
                  <description>Internal module flag used as wakeup source</description>
                  <value>#1</value>
                </enumeratedValue>
              </enumeratedValues>
            </field>
            <field>
              <name>WUME6</name>
              <description>Wakeup Module Enable For Module 6</description>
              <bitOffset>6</bitOffset>
              <bitWidth>1</bitWidth>
              <access>read-write</access>
              <enumeratedValues>
                <enumeratedValue>
                  <name>0</name>
                  <description>Internal module flag not used as wakeup source</description>
                  <value>#0</value>
                </enumeratedValue>
                <enumeratedValue>
                  <name>1</name>
                  <description>Internal module flag used as wakeup source</description>
                  <value>#1</value>
                </enumeratedValue>
              </enumeratedValues>
            </field>
            <field>
              <name>WUME7</name>
              <description>Wakeup Module Enable For Module 7</description>
              <bitOffset>7</bitOffset>
              <bitWidth>1</bitWidth>
              <access>read-write</access>
              <enumeratedValues>
                <enumeratedValue>
                  <name>0</name>
                  <description>Internal module flag not used as wakeup source</description>
                  <value>#0</value>
                </enumeratedValue>
                <enumeratedValue>
                  <name>1</name>
                  <description>Internal module flag used as wakeup source</description>
                  <value>#1</value>
                </enumeratedValue>
              </enumeratedValues>
            </field>
          </fields>
        </register>
        <register>
          <name>F1</name>
          <description>LLWU Flag 1 register</description>
          <addressOffset>0x5</addressOffset>
          <size>8</size>
          <access>read-write</access>
          <resetValue>0</resetValue>
          <resetMask>0xFF</resetMask>
          <fields>
            <field>
              <name>WUF0</name>
              <description>Wakeup Flag For LLWU_P0</description>
              <bitOffset>0</bitOffset>
              <bitWidth>1</bitWidth>
              <access>read-write</access>
              <enumeratedValues>
                <enumeratedValue>
                  <name>0</name>
                  <description>LLWU_P0 input was not a wakeup source</description>
                  <value>#0</value>
                </enumeratedValue>
                <enumeratedValue>
                  <name>1</name>
                  <description>LLWU_P0 input was a wakeup source</description>
                  <value>#1</value>
                </enumeratedValue>
              </enumeratedValues>
            </field>
            <field>
              <name>WUF1</name>
              <description>Wakeup Flag For LLWU_P1</description>
              <bitOffset>1</bitOffset>
              <bitWidth>1</bitWidth>
              <access>read-write</access>
              <enumeratedValues>
                <enumeratedValue>
                  <name>0</name>
                  <description>LLWU_P1 input was not a wakeup source</description>
                  <value>#0</value>
                </enumeratedValue>
                <enumeratedValue>
                  <name>1</name>
                  <description>LLWU_P1 input was a wakeup source</description>
                  <value>#1</value>
                </enumeratedValue>
              </enumeratedValues>
            </field>
            <field>
              <name>WUF2</name>
              <description>Wakeup Flag For LLWU_P2</description>
              <bitOffset>2</bitOffset>
              <bitWidth>1</bitWidth>
              <access>read-write</access>
              <enumeratedValues>
                <enumeratedValue>
                  <name>0</name>
                  <description>LLWU_P2 input was not a wakeup source</description>
                  <value>#0</value>
                </enumeratedValue>
                <enumeratedValue>
                  <name>1</name>
                  <description>LLWU_P2 input was a wakeup source</description>
                  <value>#1</value>
                </enumeratedValue>
              </enumeratedValues>
            </field>
            <field>
              <name>WUF3</name>
              <description>Wakeup Flag For LLWU_P3</description>
              <bitOffset>3</bitOffset>
              <bitWidth>1</bitWidth>
              <access>read-write</access>
              <enumeratedValues>
                <enumeratedValue>
                  <name>0</name>
                  <description>LLWU_P3 input was not a wake-up source</description>
                  <value>#0</value>
                </enumeratedValue>
                <enumeratedValue>
                  <name>1</name>
                  <description>LLWU_P3 input was a wake-up source</description>
                  <value>#1</value>
                </enumeratedValue>
              </enumeratedValues>
            </field>
            <field>
              <name>WUF4</name>
              <description>Wakeup Flag For LLWU_P4</description>
              <bitOffset>4</bitOffset>
              <bitWidth>1</bitWidth>
              <access>read-write</access>
              <enumeratedValues>
                <enumeratedValue>
                  <name>0</name>
                  <description>LLWU_P4 input was not a wakeup source</description>
                  <value>#0</value>
                </enumeratedValue>
                <enumeratedValue>
                  <name>1</name>
                  <description>LLWU_P4 input was a wakeup source</description>
                  <value>#1</value>
                </enumeratedValue>
              </enumeratedValues>
            </field>
            <field>
              <name>WUF5</name>
              <description>Wakeup Flag For LLWU_P5</description>
              <bitOffset>5</bitOffset>
              <bitWidth>1</bitWidth>
              <access>read-write</access>
              <enumeratedValues>
                <enumeratedValue>
                  <name>0</name>
                  <description>LLWU_P5 input was not a wakeup source</description>
                  <value>#0</value>
                </enumeratedValue>
                <enumeratedValue>
                  <name>1</name>
                  <description>LLWU_P5 input was a wakeup source</description>
                  <value>#1</value>
                </enumeratedValue>
              </enumeratedValues>
            </field>
            <field>
              <name>WUF6</name>
              <description>Wakeup Flag For LLWU_P6</description>
              <bitOffset>6</bitOffset>
              <bitWidth>1</bitWidth>
              <access>read-write</access>
              <enumeratedValues>
                <enumeratedValue>
                  <name>0</name>
                  <description>LLWU_P6 input was not a wakeup source</description>
                  <value>#0</value>
                </enumeratedValue>
                <enumeratedValue>
                  <name>1</name>
                  <description>LLWU_P6 input was a wakeup source</description>
                  <value>#1</value>
                </enumeratedValue>
              </enumeratedValues>
            </field>
            <field>
              <name>WUF7</name>
              <description>Wakeup Flag For LLWU_P7</description>
              <bitOffset>7</bitOffset>
              <bitWidth>1</bitWidth>
              <access>read-write</access>
              <enumeratedValues>
                <enumeratedValue>
                  <name>0</name>
                  <description>LLWU_P7 input was not a wakeup source</description>
                  <value>#0</value>
                </enumeratedValue>
                <enumeratedValue>
                  <name>1</name>
                  <description>LLWU_P7 input was a wakeup source</description>
                  <value>#1</value>
                </enumeratedValue>
              </enumeratedValues>
            </field>
          </fields>
        </register>
        <register>
          <name>F2</name>
          <description>LLWU Flag 2 register</description>
          <addressOffset>0x6</addressOffset>
          <size>8</size>
          <access>read-write</access>
          <resetValue>0</resetValue>
          <resetMask>0xFF</resetMask>
          <fields>
            <field>
              <name>WUF8</name>
              <description>Wakeup Flag For LLWU_P8</description>
              <bitOffset>0</bitOffset>
              <bitWidth>1</bitWidth>
              <access>read-write</access>
              <enumeratedValues>
                <enumeratedValue>
                  <name>0</name>
                  <description>LLWU_P8 input was not a wakeup source</description>
                  <value>#0</value>
                </enumeratedValue>
                <enumeratedValue>
                  <name>1</name>
                  <description>LLWU_P8 input was a wakeup source</description>
                  <value>#1</value>
                </enumeratedValue>
              </enumeratedValues>
            </field>
            <field>
              <name>WUF9</name>
              <description>Wakeup Flag For LLWU_P9</description>
              <bitOffset>1</bitOffset>
              <bitWidth>1</bitWidth>
              <access>read-write</access>
              <enumeratedValues>
                <enumeratedValue>
                  <name>0</name>
                  <description>LLWU_P9 input was not a wakeup source</description>
                  <value>#0</value>
                </enumeratedValue>
                <enumeratedValue>
                  <name>1</name>
                  <description>LLWU_P9 input was a wakeup source</description>
                  <value>#1</value>
                </enumeratedValue>
              </enumeratedValues>
            </field>
            <field>
              <name>WUF10</name>
              <description>Wakeup Flag For LLWU_P10</description>
              <bitOffset>2</bitOffset>
              <bitWidth>1</bitWidth>
              <access>read-write</access>
              <enumeratedValues>
                <enumeratedValue>
                  <name>0</name>
                  <description>LLWU_P10 input was not a wakeup source</description>
                  <value>#0</value>
                </enumeratedValue>
                <enumeratedValue>
                  <name>1</name>
                  <description>LLWU_P10 input was a wakeup source</description>
                  <value>#1</value>
                </enumeratedValue>
              </enumeratedValues>
            </field>
            <field>
              <name>WUF11</name>
              <description>Wakeup Flag For LLWU_P11</description>
              <bitOffset>3</bitOffset>
              <bitWidth>1</bitWidth>
              <access>read-write</access>
              <enumeratedValues>
                <enumeratedValue>
                  <name>0</name>
                  <description>LLWU_P11 input was not a wakeup source</description>
                  <value>#0</value>
                </enumeratedValue>
                <enumeratedValue>
                  <name>1</name>
                  <description>LLWU_P11 input was a wakeup source</description>
                  <value>#1</value>
                </enumeratedValue>
              </enumeratedValues>
            </field>
            <field>
              <name>WUF12</name>
              <description>Wakeup Flag For LLWU_P12</description>
              <bitOffset>4</bitOffset>
              <bitWidth>1</bitWidth>
              <access>read-write</access>
              <enumeratedValues>
                <enumeratedValue>
                  <name>0</name>
                  <description>LLWU_P12 input was not a wakeup source</description>
                  <value>#0</value>
                </enumeratedValue>
                <enumeratedValue>
                  <name>1</name>
                  <description>LLWU_P12 input was a wakeup source</description>
                  <value>#1</value>
                </enumeratedValue>
              </enumeratedValues>
            </field>
            <field>
              <name>WUF13</name>
              <description>Wakeup Flag For LLWU_P13</description>
              <bitOffset>5</bitOffset>
              <bitWidth>1</bitWidth>
              <access>read-write</access>
              <enumeratedValues>
                <enumeratedValue>
                  <name>0</name>
                  <description>LLWU_P13 input was not a wakeup source</description>
                  <value>#0</value>
                </enumeratedValue>
                <enumeratedValue>
                  <name>1</name>
                  <description>LLWU_P13 input was a wakeup source</description>
                  <value>#1</value>
                </enumeratedValue>
              </enumeratedValues>
            </field>
            <field>
              <name>WUF14</name>
              <description>Wakeup Flag For LLWU_P14</description>
              <bitOffset>6</bitOffset>
              <bitWidth>1</bitWidth>
              <access>read-write</access>
              <enumeratedValues>
                <enumeratedValue>
                  <name>0</name>
                  <description>LLWU_P14 input was not a wakeup source</description>
                  <value>#0</value>
                </enumeratedValue>
                <enumeratedValue>
                  <name>1</name>
                  <description>LLWU_P14 input was a wakeup source</description>
                  <value>#1</value>
                </enumeratedValue>
              </enumeratedValues>
            </field>
            <field>
              <name>WUF15</name>
              <description>Wakeup Flag For LLWU_P15</description>
              <bitOffset>7</bitOffset>
              <bitWidth>1</bitWidth>
              <access>read-write</access>
              <enumeratedValues>
                <enumeratedValue>
                  <name>0</name>
                  <description>LLWU_P15 input was not a wakeup source</description>
                  <value>#0</value>
                </enumeratedValue>
                <enumeratedValue>
                  <name>1</name>
                  <description>LLWU_P15 input was a wakeup source</description>
                  <value>#1</value>
                </enumeratedValue>
              </enumeratedValues>
            </field>
          </fields>
        </register>
        <register>
          <name>F3</name>
          <description>LLWU Flag 3 register</description>
          <addressOffset>0x7</addressOffset>
          <size>8</size>
          <access>read-only</access>
          <resetValue>0</resetValue>
          <resetMask>0xFF</resetMask>
          <fields>
            <field>
              <name>MWUF0</name>
              <description>Wakeup flag For module 0</description>
              <bitOffset>0</bitOffset>
              <bitWidth>1</bitWidth>
              <access>read-only</access>
              <enumeratedValues>
                <enumeratedValue>
                  <name>0</name>
                  <description>Module 0 input was not a wakeup source</description>
                  <value>#0</value>
                </enumeratedValue>
                <enumeratedValue>
                  <name>1</name>
                  <description>Module 0 input was a wakeup source</description>
                  <value>#1</value>
                </enumeratedValue>
              </enumeratedValues>
            </field>
            <field>
              <name>MWUF1</name>
              <description>Wakeup flag For module 1</description>
              <bitOffset>1</bitOffset>
              <bitWidth>1</bitWidth>
              <access>read-only</access>
              <enumeratedValues>
                <enumeratedValue>
                  <name>0</name>
                  <description>Module 1 input was not a wakeup source</description>
                  <value>#0</value>
                </enumeratedValue>
                <enumeratedValue>
                  <name>1</name>
                  <description>Module 1 input was a wakeup source</description>
                  <value>#1</value>
                </enumeratedValue>
              </enumeratedValues>
            </field>
            <field>
              <name>MWUF2</name>
              <description>Wakeup flag For module 2</description>
              <bitOffset>2</bitOffset>
              <bitWidth>1</bitWidth>
              <access>read-only</access>
              <enumeratedValues>
                <enumeratedValue>
                  <name>0</name>
                  <description>Module 2 input was not a wakeup source</description>
                  <value>#0</value>
                </enumeratedValue>
                <enumeratedValue>
                  <name>1</name>
                  <description>Module 2 input was a wakeup source</description>
                  <value>#1</value>
                </enumeratedValue>
              </enumeratedValues>
            </field>
            <field>
              <name>MWUF3</name>
              <description>Wakeup flag For module 3</description>
              <bitOffset>3</bitOffset>
              <bitWidth>1</bitWidth>
              <access>read-only</access>
              <enumeratedValues>
                <enumeratedValue>
                  <name>0</name>
                  <description>Module 3 input was not a wakeup source</description>
                  <value>#0</value>
                </enumeratedValue>
                <enumeratedValue>
                  <name>1</name>
                  <description>Module 3 input was a wakeup source</description>
                  <value>#1</value>
                </enumeratedValue>
              </enumeratedValues>
            </field>
            <field>
              <name>MWUF4</name>
              <description>Wakeup flag For module 4</description>
              <bitOffset>4</bitOffset>
              <bitWidth>1</bitWidth>
              <access>read-only</access>
              <enumeratedValues>
                <enumeratedValue>
                  <name>0</name>
                  <description>Module 4 input was not a wakeup source</description>
                  <value>#0</value>
                </enumeratedValue>
                <enumeratedValue>
                  <name>1</name>
                  <description>Module 4 input was a wakeup source</description>
                  <value>#1</value>
                </enumeratedValue>
              </enumeratedValues>
            </field>
            <field>
              <name>MWUF5</name>
              <description>Wakeup flag For module 5</description>
              <bitOffset>5</bitOffset>
              <bitWidth>1</bitWidth>
              <access>read-only</access>
              <enumeratedValues>
                <enumeratedValue>
                  <name>0</name>
                  <description>Module 5 input was not a wakeup source</description>
                  <value>#0</value>
                </enumeratedValue>
                <enumeratedValue>
                  <name>1</name>
                  <description>Module 5 input was a wakeup source</description>
                  <value>#1</value>
                </enumeratedValue>
              </enumeratedValues>
            </field>
            <field>
              <name>MWUF6</name>
              <description>Wakeup flag For module 6</description>
              <bitOffset>6</bitOffset>
              <bitWidth>1</bitWidth>
              <access>read-only</access>
              <enumeratedValues>
                <enumeratedValue>
                  <name>0</name>
                  <description>Module 6 input was not a wakeup source</description>
                  <value>#0</value>
                </enumeratedValue>
                <enumeratedValue>
                  <name>1</name>
                  <description>Module 6 input was a wakeup source</description>
                  <value>#1</value>
                </enumeratedValue>
              </enumeratedValues>
            </field>
            <field>
              <name>MWUF7</name>
              <description>Wakeup flag For module 7</description>
              <bitOffset>7</bitOffset>
              <bitWidth>1</bitWidth>
              <access>read-only</access>
              <enumeratedValues>
                <enumeratedValue>
                  <name>0</name>
                  <description>Module 7 input was not a wakeup source</description>
                  <value>#0</value>
                </enumeratedValue>
                <enumeratedValue>
                  <name>1</name>
                  <description>Module 7 input was a wakeup source</description>
                  <value>#1</value>
                </enumeratedValue>
              </enumeratedValues>
            </field>
          </fields>
        </register>
        <register>
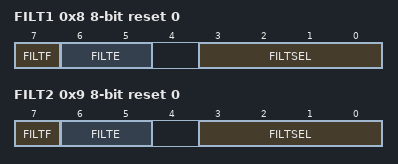
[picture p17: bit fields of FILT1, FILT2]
          <name>FILT1</name>
          <description>LLWU Pin Filter 1 register</description>
          <addressOffset>0x8</addressOffset>
          <size>8</size>
          <access>read-write</access>
          <resetValue>0</resetValue>
          <resetMask>0xFF</resetMask>
          <fields>
            <field>
              <name>FILTSEL</name>
              <description>Filter Pin Select</description>
              <bitOffset>0</bitOffset>
              <bitWidth>4</bitWidth>
              <access>read-write</access>
              <enumeratedValues>
                <enumeratedValue>
                  <name>0000</name>
                  <description>Select LLWU_P0 for filter</description>
                  <value>#0000</value>
                </enumeratedValue>
                <enumeratedValue>
                  <name>1111</name>
                  <description>Select LLWU_P15 for filter</description>
                  <value>#1111</value>
                </enumeratedValue>
              </enumeratedValues>
            </field>
            <field>
              <name>FILTE</name>
              <description>Digital Filter On External Pin</description>
              <bitOffset>5</bitOffset>
              <bitWidth>2</bitWidth>
              <access>read-write</access>
              <enumeratedValues>
                <enumeratedValue>
                  <name>00</name>
                  <description>Filter disabled</description>
                  <value>#00</value>
                </enumeratedValue>
                <enumeratedValue>
                  <name>01</name>
                  <description>Filter posedge detect enabled</description>
                  <value>#01</value>
                </enumeratedValue>
                <enumeratedValue>
                  <name>10</name>
                  <description>Filter negedge detect enabled</description>
                  <value>#10</value>
                </enumeratedValue>
                <enumeratedValue>
                  <name>11</name>
                  <description>Filter any edge detect enabled</description>
                  <value>#11</value>
                </enumeratedValue>
              </enumeratedValues>
            </field>
            <field>
              <name>FILTF</name>
              <description>Filter Detect Flag</description>
              <bitOffset>7</bitOffset>
              <bitWidth>1</bitWidth>
              <access>read-write</access>
              <enumeratedValues>
                <enumeratedValue>
                  <name>0</name>
                  <description>Pin Filter 1 was not a wakeup source</description>
                  <value>#0</value>
                </enumeratedValue>
                <enumeratedValue>
                  <name>1</name>
                  <description>Pin Filter 1 was a wakeup source</description>
                  <value>#1</value>
                </enumeratedValue>
              </enumeratedValues>
            </field>
          </fields>
        </register>
        <register>
          <name>FILT2</name>
          <description>LLWU Pin Filter 2 register</description>
          <addressOffset>0x9</addressOffset>
          <size>8</size>
          <access>read-write</access>
          <resetValue>0</resetValue>
          <resetMask>0xFF</resetMask>
          <fields>
            <field>
              <name>FILTSEL</name>
              <description>Filter Pin Select</description>
              <bitOffset>0</bitOffset>
              <bitWidth>4</bitWidth>
              <access>read-write</access>
              <enumeratedValues>
                <enumeratedValue>
                  <name>0000</name>
                  <description>Select LLWU_P0 for filter</description>
                  <value>#0000</value>
                </enumeratedValue>
                <enumeratedValue>
                  <name>1111</name>
                  <description>Select LLWU_P15 for filter</description>
                  <value>#1111</value>
                </enumeratedValue>
              </enumeratedValues>
            </field>
            <field>
              <name>FILTE</name>
              <description>Digital Filter On External Pin</description>
              <bitOffset>5</bitOffset>
              <bitWidth>2</bitWidth>
              <access>read-write</access>
              <enumeratedValues>
                <enumeratedValue>
                  <name>00</name>
                  <description>Filter disabled</description>
                  <value>#00</value>
                </enumeratedValue>
                <enumeratedValue>
                  <name>01</name>
                  <description>Filter posedge detect enabled</description>
                  <value>#01</value>
                </enumeratedValue>
                <enumeratedValue>
                  <name>10</name>
                  <description>Filter negedge detect enabled</description>
                  <value>#10</value>
                </enumeratedValue>
                <enumeratedValue>
                  <name>11</name>
                  <description>Filter any edge detect enabled</description>
                  <value>#11</value>
                </enumeratedValue>
              </enumeratedValues>
            </field>
            <field>
              <name>FILTF</name>
              <description>Filter Detect Flag</description>
              <bitOffset>7</bitOffset>
              <bitWidth>1</bitWidth>
              <access>read-write</access>
              <enumeratedValues>
                <enumeratedValue>
                  <name>0</name>
                  <description>Pin Filter 2 was not a wakeup source</description>
                  <value>#0</value>
                </enumeratedValue>
                <enumeratedValue>
                  <name>1</name>
                  <description>Pin Filter 2 was a wakeup source</description>
                  <value>#1</value>
                </enumeratedValue>
              </enumeratedValues>
            </field>
          </fields>
        </register>
      </registers>
    </peripheral>
    <peripheral>
      <name>PMC</name>
      <description>Power Management Controller</description>
      <prependToName>PMC_</prependToName>
      <baseAddress>0x4007D000</baseAddress>
      <addressBlock>
        <offset>0</offset>
        <size>0x3</size>
        <usage>registers</usage>
      </addressBlock>
      <interrupt>
        <name>LVD_LVW</name>
        <value>6</value>
      </interrupt>
      <registers>
        <register>
          <name>LVDSC1</name>
          <description>Low Voltage Detect Status And Control 1 register</description>
          <addressOffset>0</addressOffset>
          <size>8</size>
          <access>read-write</access>
          <resetValue>0x10</resetValue>
          <resetMask>0xFF</resetMask>
          <fields>
            <field>
              <name>LVDV</name>
              <description>Low-Voltage Detect Voltage Select</description>
              <bitOffset>0</bitOffset>
              <bitWidth>2</bitWidth>
              <access>read-write</access>
              <enumeratedValues>
                <enumeratedValue>
                  <name>00</name>
                  <description>Low trip point selected (V LVD = V LVDL )</description>
                  <value>#00</value>
                </enumeratedValue>
                <enumeratedValue>
                  <name>01</name>
                  <description>High trip point selected (V LVD = V LVDH )</description>
                  <value>#01</value>
                </enumeratedValue>
              </enumeratedValues>
            </field>
            <field>
              <name>LVDRE</name>
              <description>Low-Voltage Detect Reset Enable</description>
              <bitOffset>4</bitOffset>
              <bitWidth>1</bitWidth>
              <access>read-write</access>
              <enumeratedValues>
                <enumeratedValue>
                  <name>0</name>
                  <description>LVDF does not generate hardware resets</description>
                  <value>#0</value>
                </enumeratedValue>
                <enumeratedValue>
                  <name>1</name>
                  <description>Force an MCU reset when LVDF = 1</description>
                  <value>#1</value>
                </enumeratedValue>
              </enumeratedValues>
            </field>
            <field>
              <name>LVDIE</name>
              <description>Low-Voltage Detect Interrupt Enable</description>
              <bitOffset>5</bitOffset>
              <bitWidth>1</bitWidth>
              <access>read-write</access>
              <enumeratedValues>
                <enumeratedValue>
                  <name>0</name>
                  <description>Hardware interrupt disabled (use polling)</description>
                  <value>#0</value>
                </enumeratedValue>
                <enumeratedValue>
                  <name>1</name>
                  <description>Request a hardware interrupt when LVDF = 1</description>
                  <value>#1</value>
                </enumeratedValue>
              </enumeratedValues>
            </field>
            <field>
              <name>LVDACK</name>
              <description>Low-Voltage Detect Acknowledge</description>
              <bitOffset>6</bitOffset>
              <bitWidth>1</bitWidth>
              <access>write-only</access>
            </field>
            <field>
              <name>LVDF</name>
              <description>Low-Voltage Detect Flag</description>
              <bitOffset>7</bitOffset>
              <bitWidth>1</bitWidth>
              <access>read-only</access>
              <enumeratedValues>
                <enumeratedValue>
                  <name>0</name>
                  <description>Low-voltage event not detected</description>
                  <value>#0</value>
                </enumeratedValue>
                <enumeratedValue>
                  <name>1</name>
                  <description>Low-voltage event detected</description>
                  <value>#1</value>
                </enumeratedValue>
              </enumeratedValues>
            </field>
          </fields>
        </register>
        <register>
          <name>LVDSC2</name>
          <description>Low Voltage Detect Status And Control 2 register</description>
          <addressOffset>0x1</addressOffset>
          <size>8</size>
          <access>read-write</access>
          <resetValue>0</resetValue>
          <resetMask>0xFF</resetMask>
          <fields>
            <field>
              <name>LVWV</name>
              <description>Low-Voltage Warning Voltage Select</description>
              <bitOffset>0</bitOffset>
              <bitWidth>2</bitWidth>
              <access>read-write</access>
              <enumeratedValues>
                <enumeratedValue>
                  <name>00</name>
                  <description>Low trip point selected (VLVW = VLVW1)</description>
                  <value>#00</value>
                </enumeratedValue>
                <enumeratedValue>
                  <name>01</name>
                  <description>Mid 1 trip point selected (VLVW = VLVW2)</description>
                  <value>#01</value>
                </enumeratedValue>
                <enumeratedValue>
                  <name>10</name>
                  <description>Mid 2 trip point selected (VLVW = VLVW3)</description>
                  <value>#10</value>
                </enumeratedValue>
                <enumeratedValue>
                  <name>11</name>
                  <description>High trip point selected (VLVW = VLVW4)</description>
                  <value>#11</value>
                </enumeratedValue>
              </enumeratedValues>
            </field>
            <field>
              <name>LVWIE</name>
              <description>Low-Voltage Warning Interrupt Enable</description>
              <bitOffset>5</bitOffset>
              <bitWidth>1</bitWidth>
              <access>read-write</access>
              <enumeratedValues>
                <enumeratedValue>
                  <name>0</name>
                  <description>Hardware interrupt disabled (use polling)</description>
                  <value>#0</value>
                </enumeratedValue>
                <enumeratedValue>
                  <name>1</name>
                  <description>Request a hardware interrupt when LVWF = 1</description>
                  <value>#1</value>
                </enumeratedValue>
              </enumeratedValues>
            </field>
            <field>
              <name>LVWACK</name>
              <description>Low-Voltage Warning Acknowledge</description>
              <bitOffset>6</bitOffset>
              <bitWidth>1</bitWidth>
              <access>write-only</access>
            </field>
            <field>
              <name>LVWF</name>
              <description>Low-Voltage Warning Flag</description>
              <bitOffset>7</bitOffset>
              <bitWidth>1</bitWidth>
              <access>read-only</access>
              <enumeratedValues>
                <enumeratedValue>
                  <name>0</name>
                  <description>Low-voltage warning event not detected</description>
                  <value>#0</value>
                </enumeratedValue>
                <enumeratedValue>
                  <name>1</name>
                  <description>Low-voltage warning event detected</description>
                  <value>#1</value>
                </enumeratedValue>
              </enumeratedValues>
            </field>
          </fields>
        </register>
        <register>
          <name>REGSC</name>
          <description>Regulator Status And Control register</description>
          <addressOffset>0x2</addressOffset>
          <size>8</size>
          <access>read-write</access>
          <resetValue>0x4</resetValue>
          <resetMask>0xFF</resetMask>
          <fields>
            <field>
              <name>BGBE</name>
              <description>Bandgap Buffer Enable</description>
              <bitOffset>0</bitOffset>
              <bitWidth>1</bitWidth>
              <access>read-write</access>
              <enumeratedValues>
                <enumeratedValue>
                  <name>0</name>
                  <description>Bandgap buffer not enabled</description>
                  <value>#0</value>
                </enumeratedValue>
                <enumeratedValue>
                  <name>1</name>
                  <description>Bandgap buffer enabled</description>
                  <value>#1</value>
                </enumeratedValue>
              </enumeratedValues>
            </field>
            <field>
              <name>REGONS</name>
              <description>Regulator In Run Regulation Status</description>
              <bitOffset>2</bitOffset>
              <bitWidth>1</bitWidth>
              <access>read-only</access>
              <enumeratedValues>
                <enumeratedValue>
                  <name>0</name>
                  <description>Regulator is in stop regulation or in transition to/from it</description>
                  <value>#0</value>
                </enumeratedValue>
                <enumeratedValue>
                  <name>1</name>
                  <description>Regulator is in run regulation</description>
                  <value>#1</value>
                </enumeratedValue>
              </enumeratedValues>
            </field>
            <field>
              <name>ACKISO</name>
              <description>Acknowledge Isolation</description>
              <bitOffset>3</bitOffset>
              <bitWidth>1</bitWidth>
              <access>read-write</access>
              <enumeratedValues>
                <enumeratedValue>
                  <name>0</name>
                  <description>Peripherals and I/O pads are in normal run state.</description>
                  <value>#0</value>
                </enumeratedValue>
                <enumeratedValue>
                  <name>1</name>
                  <description>Certain peripherals and I/O pads are in an isolated and latched state.</description>
                  <value>#1</value>
                </enumeratedValue>
              </enumeratedValues>
            </field>
            <field>
              <name>BGEN</name>
              <description>Bandgap Enable In VLPx Operation</description>
              <bitOffset>4</bitOffset>
              <bitWidth>1</bitWidth>
              <access>read-write</access>
              <enumeratedValues>
                <enumeratedValue>
                  <name>0</name>
                  <description>Bandgap voltage reference is disabled in VLPx , LLS , and VLLSx modes.</description>
                  <value>#0</value>
                </enumeratedValue>
                <enumeratedValue>
                  <name>1</name>
                  <description>Bandgap voltage reference is enabled in VLPx , LLS , and VLLSx modes.</description>
                  <value>#1</value>
                </enumeratedValue>
              </enumeratedValues>
            </field>
          </fields>
        </register>
      </registers>
    </peripheral>
    <peripheral>
      <name>SMC</name>
      <description>System Mode Controller</description>
      <prependToName>SMC_</prependToName>
      <baseAddress>0x4007E000</baseAddress>
      <addressBlock>
        <offset>0</offset>
        <size>0x4</size>
        <usage>registers</usage>
      </addressBlock>
      <registers>
        <register>
          <name>PMPROT</name>
          <description>Power Mode Protection register</description>
          <addressOffset>0</addressOffset>
          <size>8</size>
          <access>read-write</access>
          <resetValue>0</resetValue>
          <resetMask>0xFF</resetMask>
          <fields>
            <field>
              <name>AVLLS</name>
              <description>Allow Very-Low-Leakage Stop Mode</description>
              <bitOffset>1</bitOffset>
              <bitWidth>1</bitWidth>
              <access>read-write</access>
              <enumeratedValues>
                <enumeratedValue>
                  <name>0</name>
                  <description>Any VLLSx mode is not allowed</description>
                  <value>#0</value>
                </enumeratedValue>
                <enumeratedValue>
                  <name>1</name>
                  <description>Any VLLSx mode is allowed</description>
                  <value>#1</value>
                </enumeratedValue>
              </enumeratedValues>
            </field>
            <field>
              <name>ALLS</name>
              <description>Allow Low-Leakage Stop Mode</description>
              <bitOffset>3</bitOffset>
              <bitWidth>1</bitWidth>
              <access>read-write</access>
              <enumeratedValues>
                <enumeratedValue>
                  <name>0</name>
                  <description>LLS is not allowed</description>
                  <value>#0</value>
                </enumeratedValue>
                <enumeratedValue>
                  <name>1</name>
                  <description>LLS is allowed</description>
                  <value>#1</value>
                </enumeratedValue>
              </enumeratedValues>
            </field>
            <field>
              <name>AVLP</name>
              <description>Allow Very-Low-Power Modes</description>
              <bitOffset>5</bitOffset>
              <bitWidth>1</bitWidth>
              <access>read-write</access>
              <enumeratedValues>
                <enumeratedValue>
                  <name>0</name>
                  <description>VLPR, VLPW, and VLPS are not allowed.</description>
                  <value>#0</value>
                </enumeratedValue>
                <enumeratedValue>
                  <name>1</name>
                  <description>VLPR, VLPW, and VLPS are allowed.</description>
                  <value>#1</value>
                </enumeratedValue>
              </enumeratedValues>
            </field>
          </fields>
        </register>
        <register>
          <name>PMCTRL</name>
          <description>Power Mode Control register</description>
          <addressOffset>0x1</addressOffset>
          <size>8</size>
          <access>read-write</access>
          <resetValue>0</resetValue>
          <resetMask>0xFF</resetMask>
          <fields>
            <field>
              <name>STOPM</name>
              <description>Stop Mode Control</description>
              <bitOffset>0</bitOffset>
              <bitWidth>3</bitWidth>
              <access>read-write</access>
              <enumeratedValues>
                <enumeratedValue>
                  <name>000</name>
                  <description>Normal Stop (STOP)</description>
                  <value>#000</value>
                </enumeratedValue>
                <enumeratedValue>
                  <name>010</name>
                  <description>Very-Low-Power Stop (VLPS)</description>
                  <value>#010</value>
                </enumeratedValue>
                <enumeratedValue>
                  <name>011</name>
                  <description>Low-Leakage Stop (LLS)</description>
                  <value>#011</value>
                </enumeratedValue>
                <enumeratedValue>
                  <name>100</name>
                  <description>Very-Low-Leakage Stop (VLLSx)</description>
                  <value>#100</value>
                </enumeratedValue>
                <enumeratedValue>
                  <name>110</name>
                  <description>Reseved</description>
                  <value>#110</value>
                </enumeratedValue>
              </enumeratedValues>
            </field>
            <field>
              <name>STOPA</name>
              <description>Stop Aborted</description>
              <bitOffset>3</bitOffset>
              <bitWidth>1</bitWidth>
              <access>read-only</access>
              <enumeratedValues>
                <enumeratedValue>
                  <name>0</name>
                  <description>The previous stop mode entry was successsful.</description>
                  <value>#0</value>
                </enumeratedValue>
                <enumeratedValue>
                  <name>1</name>
                  <description>The previous stop mode entry was aborted.</description>
                  <value>#1</value>
                </enumeratedValue>
              </enumeratedValues>
            </field>
            <field>
              <name>RUNM</name>
              <description>Run Mode Control</description>
              <bitOffset>5</bitOffset>
              <bitWidth>2</bitWidth>
              <access>read-write</access>
              <enumeratedValues>
                <enumeratedValue>
                  <name>00</name>
                  <description>Normal Run mode (RUN)</description>
                  <value>#00</value>
                </enumeratedValue>
                <enumeratedValue>
                  <name>10</name>
                  <description>Very-Low-Power Run mode (VLPR)</description>
                  <value>#10</value>
                </enumeratedValue>
              </enumeratedValues>
            </field>
          </fields>
        </register>
        <register>
          <name>STOPCTRL</name>
          <description>Stop Control Register</description>
          <addressOffset>0x2</addressOffset>
          <size>8</size>
          <access>read-write</access>
          <resetValue>0x3</resetValue>
          <resetMask>0xFF</resetMask>
          <fields>
            <field>
              <name>VLLSM</name>
              <description>VLLS Mode Control</description>
              <bitOffset>0</bitOffset>
              <bitWidth>3</bitWidth>
              <access>read-write</access>
              <enumeratedValues>
                <enumeratedValue>
                  <name>000</name>
                  <description>VLLS0</description>
                  <value>#000</value>
                </enumeratedValue>
                <enumeratedValue>
                  <name>001</name>
                  <description>VLLS1</description>
                  <value>#001</value>
                </enumeratedValue>
                <enumeratedValue>
                  <name>011</name>
                  <description>VLLS3</description>
                  <value>#011</value>
                </enumeratedValue>
              </enumeratedValues>
            </field>
            <field>
              <name>PORPO</name>
              <description>POR Power Option</description>
              <bitOffset>5</bitOffset>
              <bitWidth>1</bitWidth>
              <access>read-write</access>
              <enumeratedValues>
                <enumeratedValue>
                  <name>0</name>
                  <description>POR detect circuit is enabled in VLLS0</description>
                  <value>#0</value>
                </enumeratedValue>
                <enumeratedValue>
                  <name>1</name>
                  <description>POR detect circuit is disabled in VLLS0</description>
                  <value>#1</value>
                </enumeratedValue>
              </enumeratedValues>
            </field>
            <field>
              <name>PSTOPO</name>
              <description>Partial Stop Option</description>
              <bitOffset>6</bitOffset>
              <bitWidth>2</bitWidth>
              <access>read-write</access>
              <enumeratedValues>
                <enumeratedValue>
                  <name>00</name>
                  <description>STOP - Normal Stop mode</description>
                  <value>#00</value>
                </enumeratedValue>
                <enumeratedValue>
                  <name>01</name>
                  <description>PSTOP1 - Partial Stop with both system and bus clocks disabled</description>
                  <value>#01</value>
                </enumeratedValue>
                <enumeratedValue>
                  <name>10</name>
                  <description>PSTOP2 - Partial Stop with system clock disabled and bus clock enabled</description>
                  <value>#10</value>
                </enumeratedValue>
              </enumeratedValues>
            </field>
          </fields>
        </register>
        <register>
          <name>PMSTAT</name>
          <description>Power Mode Status register</description>
          <addressOffset>0x3</addressOffset>
          <size>8</size>
          <access>read-only</access>
          <resetValue>0x1</resetValue>
          <resetMask>0xFF</resetMask>
          <fields>
            <field>
              <name>PMSTAT</name>
              <description>When debug is enabled, the PMSTAT will not update to STOP or VLPS When a PSTOP mode is enabled, the PMSTAT will not update to STOP or VLPS</description>
              <bitOffset>0</bitOffset>
              <bitWidth>7</bitWidth>
              <access>read-only</access>
            </field>
          </fields>
        </register>
      </registers>
    </peripheral>
    <peripheral>
      <name>RCM</name>
      <description>Reset Control Module</description>
      <prependToName>RCM_</prependToName>
      <baseAddress>0x4007F000</baseAddress>
      <addressBlock>
        <offset>0</offset>
        <size>0x6</size>
        <usage>registers</usage>
      </addressBlock>
      <registers>
        <register>
          <name>SRS0</name>
          <description>System Reset Status Register 0</description>
          <addressOffset>0</addressOffset>
          <size>8</size>
          <access>read-only</access>
          <resetValue>0x82</resetValue>
          <resetMask>0xFF</resetMask>
          <fields>
            <field>
              <name>WAKEUP</name>
              <description>Low Leakage Wakeup Reset</description>
              <bitOffset>0</bitOffset>
              <bitWidth>1</bitWidth>
              <access>read-only</access>
              <enumeratedValues>
                <enumeratedValue>
                  <name>0</name>
                  <description>Reset not caused by LLWU module wakeup source</description>
                  <value>#0</value>
                </enumeratedValue>
                <enumeratedValue>
                  <name>1</name>
                  <description>Reset caused by LLWU module wakeup source</description>
                  <value>#1</value>
                </enumeratedValue>
              </enumeratedValues>
            </field>
            <field>
              <name>LVD</name>
              <description>Low-Voltage Detect Reset</description>
              <bitOffset>1</bitOffset>
              <bitWidth>1</bitWidth>
              <access>read-only</access>
              <enumeratedValues>
                <enumeratedValue>
                  <name>0</name>
                  <description>Reset not caused by LVD trip or POR</description>
                  <value>#0</value>
                </enumeratedValue>
                <enumeratedValue>
                  <name>1</name>
                  <description>Reset caused by LVD trip or POR</description>
                  <value>#1</value>
                </enumeratedValue>
              </enumeratedValues>
            </field>
            <field>
              <name>LOC</name>
              <description>Loss-of-Clock Reset</description>
              <bitOffset>2</bitOffset>
              <bitWidth>1</bitWidth>
              <access>read-only</access>
              <enumeratedValues>
                <enumeratedValue>
                  <name>0</name>
                  <description>Reset not caused by a loss of external clock.</description>
                  <value>#0</value>
                </enumeratedValue>
                <enumeratedValue>
                  <name>1</name>
                  <description>Reset caused by a loss of external clock.</description>
                  <value>#1</value>
                </enumeratedValue>
              </enumeratedValues>
            </field>
            <field>
              <name>LOL</name>
              <description>Loss-of-Lock Reset</description>
              <bitOffset>3</bitOffset>
              <bitWidth>1</bitWidth>
              <access>read-only</access>
              <enumeratedValues>
                <enumeratedValue>
                  <name>0</name>
                  <description>Reset not caused by a loss of lock in the PLL</description>
                  <value>#0</value>
                </enumeratedValue>
                <enumeratedValue>
                  <name>1</name>
                  <description>Reset caused by a loss of lock in the PLL</description>
                  <value>#1</value>
                </enumeratedValue>
              </enumeratedValues>
            </field>
            <field>
              <name>WDOG</name>
              <description>Watchdog</description>
              <bitOffset>5</bitOffset>
              <bitWidth>1</bitWidth>
              <access>read-only</access>
              <enumeratedValues>
                <enumeratedValue>
                  <name>0</name>
                  <description>Reset not caused by watchdog timeout</description>
                  <value>#0</value>
                </enumeratedValue>
                <enumeratedValue>
                  <name>1</name>
                  <description>Reset caused by watchdog timeout</description>
                  <value>#1</value>
                </enumeratedValue>
              </enumeratedValues>
            </field>
            <field>
              <name>PIN</name>
              <description>External Reset Pin</description>
              <bitOffset>6</bitOffset>
              <bitWidth>1</bitWidth>
              <access>read-only</access>
              <enumeratedValues>
                <enumeratedValue>
                  <name>0</name>
                  <description>Reset not caused by external reset pin</description>
                  <value>#0</value>
                </enumeratedValue>
                <enumeratedValue>
                  <name>1</name>
                  <description>Reset caused by external reset pin</description>
                  <value>#1</value>
                </enumeratedValue>
              </enumeratedValues>
            </field>
            <field>
              <name>POR</name>
              <description>Power-On Reset</description>
              <bitOffset>7</bitOffset>
              <bitWidth>1</bitWidth>
              <access>read-only</access>
              <enumeratedValues>
                <enumeratedValue>
                  <name>0</name>
                  <description>Reset not caused by POR</description>
                  <value>#0</value>
                </enumeratedValue>
                <enumeratedValue>
                  <name>1</name>
                  <description>Reset caused by POR</description>
                  <value>#1</value>
                </enumeratedValue>
              </enumeratedValues>
            </field>
          </fields>
        </register>
        <register>
          <name>SRS1</name>
          <description>System Reset Status Register 1</description>
          <addressOffset>0x1</addressOffset>
          <size>8</size>
          <access>read-only</access>
          <resetValue>0</resetValue>
          <resetMask>0xFF</resetMask>
          <fields>
            <field>
              <name>LOCKUP</name>
              <description>Core Lockup</description>
              <bitOffset>1</bitOffset>
              <bitWidth>1</bitWidth>
              <access>read-only</access>
              <enumeratedValues>
                <enumeratedValue>
                  <name>0</name>
                  <description>Reset not caused by core LOCKUP event</description>
                  <value>#0</value>
                </enumeratedValue>
                <enumeratedValue>
                  <name>1</name>
                  <description>Reset caused by core LOCKUP event</description>
                  <value>#1</value>
                </enumeratedValue>
              </enumeratedValues>
            </field>
            <field>
              <name>SW</name>
              <description>Software</description>
              <bitOffset>2</bitOffset>
              <bitWidth>1</bitWidth>
              <access>read-only</access>
              <enumeratedValues>
                <enumeratedValue>
                  <name>0</name>
                  <description>Reset not caused by software setting of SYSRESETREQ bit</description>
                  <value>#0</value>
                </enumeratedValue>
                <enumeratedValue>
                  <name>1</name>
                  <description>Reset caused by software setting of SYSRESETREQ bit</description>
                  <value>#1</value>
                </enumeratedValue>
              </enumeratedValues>
            </field>
            <field>
              <name>MDM_AP</name>
              <description>MDM-AP System Reset Request</description>
              <bitOffset>3</bitOffset>
              <bitWidth>1</bitWidth>
              <access>read-only</access>
              <enumeratedValues>
                <enumeratedValue>
                  <name>0</name>
                  <description>Reset not caused by host debugger system setting of the System Reset Request bit</description>
                  <value>#0</value>
                </enumeratedValue>
                <enumeratedValue>
                  <name>1</name>
                  <description>Reset caused by host debugger system setting of the System Reset Request bit</description>
                  <value>#1</value>
                </enumeratedValue>
              </enumeratedValues>
            </field>
            <field>
              <name>SACKERR</name>
              <description>Stop Mode Acknowledge Error Reset</description>
              <bitOffset>5</bitOffset>
              <bitWidth>1</bitWidth>
              <access>read-only</access>
              <enumeratedValues>
                <enumeratedValue>
                  <name>0</name>
                  <description>Reset not caused by peripheral failure to acknowledge attempt to enter stop mode</description>
                  <value>#0</value>
                </enumeratedValue>
                <enumeratedValue>
                  <name>1</name>
                  <description>Reset caused by peripheral failure to acknowledge attempt to enter stop mode</description>
                  <value>#1</value>
                </enumeratedValue>
              </enumeratedValues>
            </field>
          </fields>
        </register>
        <register>
          <name>RPFC</name>
          <description>Reset Pin Filter Control register</description>
          <addressOffset>0x4</addressOffset>
          <size>8</size>
          <access>read-write</access>
          <resetValue>0</resetValue>
          <resetMask>0xFF</resetMask>
          <fields>
            <field>
              <name>RSTFLTSRW</name>
              <description>Reset Pin Filter Select in Run and Wait Modes</description>
              <bitOffset>0</bitOffset>
              <bitWidth>2</bitWidth>
              <access>read-write</access>
              <enumeratedValues>
                <enumeratedValue>
                  <name>00</name>
                  <description>All filtering disabled</description>
                  <value>#00</value>
                </enumeratedValue>
                <enumeratedValue>
                  <name>01</name>
                  <description>Bus clock filter enabled for normal operation</description>
                  <value>#01</value>
                </enumeratedValue>
                <enumeratedValue>
                  <name>10</name>
                  <description>LPO clock filter enabled for normal operation</description>
                  <value>#10</value>
                </enumeratedValue>
              </enumeratedValues>
            </field>
            <field>
              <name>RSTFLTSS</name>
              <description>Reset Pin Filter Select in Stop Mode</description>
              <bitOffset>2</bitOffset>
              <bitWidth>1</bitWidth>
              <access>read-write</access>
              <enumeratedValues>
                <enumeratedValue>
                  <name>0</name>
                  <description>All filtering disabled</description>
                  <value>#0</value>
                </enumeratedValue>
                <enumeratedValue>
                  <name>1</name>
                  <description>LPO clock filter enabled</description>
                  <value>#1</value>
                </enumeratedValue>
              </enumeratedValues>
            </field>
          </fields>
        </register>
        <register>
          <name>RPFW</name>
          <description>Reset Pin Filter Width register</description>
          <addressOffset>0x5</addressOffset>
          <size>8</size>
          <access>read-write</access>
          <resetValue>0</resetValue>
          <resetMask>0xFF</resetMask>
          <fields>
            <field>
              <name>RSTFLTSEL</name>
              <description>Reset Pin Filter Bus Clock Select</description>
              <bitOffset>0</bitOffset>
              <bitWidth>5</bitWidth>
              <access>read-write</access>
              <enumeratedValues>
                <enumeratedValue>
                  <name>00000</name>
                  <description>Bus clock filter count is 1</description>
                  <value>#00000</value>
                </enumeratedValue>
                <enumeratedValue>
                  <name>00001</name>
                  <description>Bus clock filter count is 2</description>
                  <value>#00001</value>
                </enumeratedValue>
                <enumeratedValue>
                  <name>00010</name>
                  <description>Bus clock filter count is 3</description>
                  <value>#00010</value>
                </enumeratedValue>
                <enumeratedValue>
                  <name>00011</name>
                  <description>Bus clock filter count is 4</description>
                  <value>#00011</value>
                </enumeratedValue>
                <enumeratedValue>
                  <name>00100</name>
                  <description>Bus clock filter count is 5</description>
                  <value>#00100</value>
                </enumeratedValue>
                <enumeratedValue>
                  <name>00101</name>
                  <description>Bus clock filter count is 6</description>
                  <value>#00101</value>
                </enumeratedValue>
                <enumeratedValue>
                  <name>00110</name>
                  <description>Bus clock filter count is 7</description>
                  <value>#00110</value>
                </enumeratedValue>
                <enumeratedValue>
                  <name>00111</name>
                  <description>Bus clock filter count is 8</description>
                  <value>#00111</value>
                </enumeratedValue>
                <enumeratedValue>
                  <name>01000</name>
                  <description>Bus clock filter count is 9</description>
                  <value>#01000</value>
                </enumeratedValue>
                <enumeratedValue>
                  <name>01001</name>
                  <description>Bus clock filter count is 10</description>
                  <value>#01001</value>
                </enumeratedValue>
                <enumeratedValue>
                  <name>01010</name>
                  <description>Bus clock filter count is 11</description>
                  <value>#01010</value>
                </enumeratedValue>
                <enumeratedValue>
                  <name>01011</name>
                  <description>Bus clock filter count is 12</description>
                  <value>#01011</value>
                </enumeratedValue>
                <enumeratedValue>
                  <name>01100</name>
                  <description>Bus clock filter count is 13</description>
                  <value>#01100</value>
                </enumeratedValue>
                <enumeratedValue>
                  <name>01101</name>
                  <description>Bus clock filter count is 14</description>
                  <value>#01101</value>
                </enumeratedValue>
                <enumeratedValue>
                  <name>01110</name>
                  <description>Bus clock filter count is 15</description>
                  <value>#01110</value>
                </enumeratedValue>
                <enumeratedValue>
                  <name>01111</name>
                  <description>Bus clock filter count is 16</description>
                  <value>#01111</value>
                </enumeratedValue>
                <enumeratedValue>
                  <name>10000</name>
                  <description>Bus clock filter count is 17</description>
                  <value>#10000</value>
                </enumeratedValue>
                <enumeratedValue>
                  <name>10001</name>
                  <description>Bus clock filter count is 18</description>
                  <value>#10001</value>
                </enumeratedValue>
                <enumeratedValue>
                  <name>10010</name>
                  <description>Bus clock filter count is 19</description>
                  <value>#10010</value>
                </enumeratedValue>
                <enumeratedValue>
                  <name>10011</name>
                  <description>Bus clock filter count is 20</description>
                  <value>#10011</value>
                </enumeratedValue>
                <enumeratedValue>
                  <name>10100</name>
                  <description>Bus clock filter count is 21</description>
                  <value>#10100</value>
                </enumeratedValue>
                <enumeratedValue>
                  <name>10101</name>
                  <description>Bus clock filter count is 22</description>
                  <value>#10101</value>
                </enumeratedValue>
                <enumeratedValue>
                  <name>10110</name>
                  <description>Bus clock filter count is 23</description>
                  <value>#10110</value>
                </enumeratedValue>
                <enumeratedValue>
                  <name>10111</name>
                  <description>Bus clock filter count is 24</description>
                  <value>#10111</value>
                </enumeratedValue>
                <enumeratedValue>
                  <name>11000</name>
                  <description>Bus clock filter count is 25</description>
                  <value>#11000</value>
                </enumeratedValue>
                <enumeratedValue>
                  <name>11001</name>
                  <description>Bus clock filter count is 26</description>
                  <value>#11001</value>
                </enumeratedValue>
                <enumeratedValue>
                  <name>11010</name>
                  <description>Bus clock filter count is 27</description>
                  <value>#11010</value>
                </enumeratedValue>
                <enumeratedValue>
                  <name>11011</name>
                  <description>Bus clock filter count is 28</description>
                  <value>#11011</value>
                </enumeratedValue>
                <enumeratedValue>
                  <name>11100</name>
                  <description>Bus clock filter count is 29</description>
                  <value>#11100</value>
                </enumeratedValue>
                <enumeratedValue>
                  <name>11101</name>
                  <description>Bus clock filter count is 30</description>
                  <value>#11101</value>
                </enumeratedValue>
                <enumeratedValue>
                  <name>11110</name>
                  <description>Bus clock filter count is 31</description>
                  <value>#11110</value>
                </enumeratedValue>
                <enumeratedValue>
                  <name>11111</name>
                  <description>Bus clock filter count is 32</description>
                  <value>#11111</value>
                </enumeratedValue>
              </enumeratedValues>
            </field>
          </fields>
        </register>
      </registers>
    </peripheral>
    <peripheral>
      <name>GPIOA</name>
      <description>General Purpose Input/Output</description>
      <groupName>GPIO</groupName>
      <prependToName>GPIOA_</prependToName>
      <baseAddress>0x400FF000</baseAddress>
      <addressBlock>
        <offset>0</offset>
        <size>0x18</size>
        <usage>registers</usage>
      </addressBlock>
      <interrupt>
        <name>PORTA</name>
        <value>30</value>
      </interrupt>
      <registers>
        <register>
          <name>PDOR</name>
          <description>Port Data Output Register</description>
          <addressOffset>0</addressOffset>
          <size>32</size>
          <access>read-write</access>
          <resetValue>0</resetValue>
          <resetMask>0xFFFFFFFF</resetMask>
          <fields>
            <field>
              <name>PDO</name>
              <description>Port Data Output</description>
              <bitOffset>0</bitOffset>
              <bitWidth>32</bitWidth>
              <access>read-write</access>
              <enumeratedValues>
                <enumeratedValue>
                  <name>0</name>
                  <description>Logic level 0 is driven on pin, provided pin is configured for general-purpose output.</description>
                  <value>#0</value>
                </enumeratedValue>
                <enumeratedValue>
                  <name>1</name>
                  <description>Logic level 1 is driven on pin, provided pin is configured for general-purpose output.</description>
                  <value>#1</value>
                </enumeratedValue>
              </enumeratedValues>
            </field>
          </fields>
        </register>
        <register>
          <name>PSOR</name>
          <description>Port Set Output Register</description>
          <addressOffset>0x4</addressOffset>
          <size>32</size>
          <access>write-only</access>
          <resetValue>0</resetValue>
          <resetMask>0xFFFFFFFF</resetMask>
          <fields>
            <field>
              <name>PTSO</name>
              <description>Port Set Output</description>
              <bitOffset>0</bitOffset>
              <bitWidth>32</bitWidth>
              <access>write-only</access>
              <enumeratedValues>
                <enumeratedValue>
                  <name>0</name>
                  <description>Corresponding bit in PDORn does not change.</description>
                  <value>#0</value>
                </enumeratedValue>
                <enumeratedValue>
                  <name>1</name>
                  <description>Corresponding bit in PDORn is set to logic 1.</description>
                  <value>#1</value>
                </enumeratedValue>
              </enumeratedValues>
            </field>
          </fields>
        </register>
        <register>
          <name>PCOR</name>
          <description>Port Clear Output Register</description>
          <addressOffset>0x8</addressOffset>
          <size>32</size>
          <access>write-only</access>
          <resetValue>0</resetValue>
          <resetMask>0xFFFFFFFF</resetMask>
          <fields>
            <field>
              <name>PTCO</name>
              <description>Port Clear Output</description>
              <bitOffset>0</bitOffset>
              <bitWidth>32</bitWidth>
              <access>write-only</access>
              <enumeratedValues>
                <enumeratedValue>
                  <name>0</name>
                  <description>Corresponding bit in PDORn does not change.</description>
                  <value>#0</value>
                </enumeratedValue>
                <enumeratedValue>
                  <name>1</name>
                  <description>Corresponding bit in PDORn is cleared to logic 0.</description>
                  <value>#1</value>
                </enumeratedValue>
              </enumeratedValues>
            </field>
          </fields>
        </register>
        <register>
          <name>PTOR</name>
          <description>Port Toggle Output Register</description>
          <addressOffset>0xC</addressOffset>
          <size>32</size>
          <access>write-only</access>
          <resetValue>0</resetValue>
          <resetMask>0xFFFFFFFF</resetMask>
          <fields>
            <field>
              <name>PTTO</name>
              <description>Port Toggle Output</description>
              <bitOffset>0</bitOffset>
              <bitWidth>32</bitWidth>
              <access>write-only</access>
              <enumeratedValues>
                <enumeratedValue>
                  <name>0</name>
                  <description>Corresponding bit in PDORn does not change.</description>
                  <value>#0</value>
                </enumeratedValue>
                <enumeratedValue>
                  <name>1</name>
                  <description>Corresponding bit in PDORn is set to the inverse of its existing logic state.</description>
                  <value>#1</value>
                </enumeratedValue>
              </enumeratedValues>
            </field>
          </fields>
        </register>
        <register>
          <name>PDIR</name>
          <description>Port Data Input Register</description>
          <addressOffset>0x10</addressOffset>
          <size>32</size>
          <access>read-only</access>
          <resetValue>0</resetValue>
          <resetMask>0xFFFFFFFF</resetMask>
          <fields>
            <field>
              <name>PDI</name>
              <description>Port Data Input</description>
              <bitOffset>0</bitOffset>
              <bitWidth>32</bitWidth>
              <access>read-only</access>
              <enumeratedValues>
                <enumeratedValue>
                  <name>0</name>
                  <description>Pin logic level is logic 0, or is not configured for use by digital function.</description>
                  <value>#0</value>
                </enumeratedValue>
                <enumeratedValue>
                  <name>1</name>
                  <description>Pin logic level is logic 1.</description>
                  <value>#1</value>
                </enumeratedValue>
              </enumeratedValues>
            </field>
          </fields>
        </register>
        <register>
          <name>PDDR</name>
          <description>Port Data Direction Register</description>
          <addressOffset>0x14</addressOffset>
          <size>32</size>
          <access>read-write</access>
          <resetValue>0</resetValue>
          <resetMask>0xFFFFFFFF</resetMask>
          <fields>
            <field>
              <name>PDD</name>
              <description>Port Data Direction</description>
              <bitOffset>0</bitOffset>
              <bitWidth>32</bitWidth>
              <access>read-write</access>
              <enumeratedValues>
                <enumeratedValue>
                  <name>0</name>
                  <description>Pin is configured as general-purpose input, for the GPIO function.</description>
                  <value>#0</value>
                </enumeratedValue>
                <enumeratedValue>
                  <name>1</name>
                  <description>Pin is configured as general-purpose output, for the GPIO function.</description>
                  <value>#1</value>
                </enumeratedValue>
              </enumeratedValues>
            </field>
          </fields>
        </register>
      </registers>
    </peripheral>
    <peripheral>
      <name>GPIOB</name>
      <description>General Purpose Input/Output</description>
      <groupName>GPIO</groupName>
      <prependToName>GPIOB_</prependToName>
      <baseAddress>0x400FF040</baseAddress>
      <addressBlock>
        <offset>0</offset>
        <size>0x18</size>
        <usage>registers</usage>
      </addressBlock>
      <registers>
        <register>
          <name>PDOR</name>
          <description>Port Data Output Register</description>
          <addressOffset>0</addressOffset>
          <size>32</size>
          <access>read-write</access>
          <resetValue>0</resetValue>
          <resetMask>0xFFFFFFFF</resetMask>
          <fields>
            <field>
              <name>PDO</name>
              <description>Port Data Output</description>
              <bitOffset>0</bitOffset>
              <bitWidth>32</bitWidth>
              <access>read-write</access>
              <enumeratedValues>
                <enumeratedValue>
                  <name>0</name>
                  <description>Logic level 0 is driven on pin, provided pin is configured for general-purpose output.</description>
                  <value>#0</value>
                </enumeratedValue>
                <enumeratedValue>
                  <name>1</name>
                  <description>Logic level 1 is driven on pin, provided pin is configured for general-purpose output.</description>
                  <value>#1</value>
                </enumeratedValue>
              </enumeratedValues>
            </field>
          </fields>
        </register>
        <register>
          <name>PSOR</name>
          <description>Port Set Output Register</description>
          <addressOffset>0x4</addressOffset>
          <size>32</size>
          <access>write-only</access>
          <resetValue>0</resetValue>
          <resetMask>0xFFFFFFFF</resetMask>
          <fields>
            <field>
              <name>PTSO</name>
              <description>Port Set Output</description>
              <bitOffset>0</bitOffset>
              <bitWidth>32</bitWidth>
              <access>write-only</access>
              <enumeratedValues>
                <enumeratedValue>
                  <name>0</name>
                  <description>Corresponding bit in PDORn does not change.</description>
                  <value>#0</value>
                </enumeratedValue>
                <enumeratedValue>
                  <name>1</name>
                  <description>Corresponding bit in PDORn is set to logic 1.</description>
                  <value>#1</value>
                </enumeratedValue>
              </enumeratedValues>
            </field>
          </fields>
        </register>
        <register>
          <name>PCOR</name>
          <description>Port Clear Output Register</description>
          <addressOffset>0x8</addressOffset>
          <size>32</size>
          <access>write-only</access>
          <resetValue>0</resetValue>
          <resetMask>0xFFFFFFFF</resetMask>
          <fields>
            <field>
              <name>PTCO</name>
              <description>Port Clear Output</description>
              <bitOffset>0</bitOffset>
              <bitWidth>32</bitWidth>
              <access>write-only</access>
              <enumeratedValues>
                <enumeratedValue>
                  <name>0</name>
                  <description>Corresponding bit in PDORn does not change.</description>
                  <value>#0</value>
                </enumeratedValue>
                <enumeratedValue>
                  <name>1</name>
                  <description>Corresponding bit in PDORn is cleared to logic 0.</description>
                  <value>#1</value>
                </enumeratedValue>
              </enumeratedValues>
            </field>
          </fields>
        </register>
        <register>
          <name>PTOR</name>
          <description>Port Toggle Output Register</description>
          <addressOffset>0xC</addressOffset>
          <size>32</size>
          <access>write-only</access>
          <resetValue>0</resetValue>
          <resetMask>0xFFFFFFFF</resetMask>
          <fields>
            <field>
              <name>PTTO</name>
              <description>Port Toggle Output</description>
              <bitOffset>0</bitOffset>
              <bitWidth>32</bitWidth>
              <access>write-only</access>
              <enumeratedValues>
                <enumeratedValue>
                  <name>0</name>
                  <description>Corresponding bit in PDORn does not change.</description>
                  <value>#0</value>
                </enumeratedValue>
                <enumeratedValue>
                  <name>1</name>
                  <description>Corresponding bit in PDORn is set to the inverse of its existing logic state.</description>
                  <value>#1</value>
                </enumeratedValue>
              </enumeratedValues>
            </field>
          </fields>
        </register>
        <register>
          <name>PDIR</name>
          <description>Port Data Input Register</description>
          <addressOffset>0x10</addressOffset>
          <size>32</size>
          <access>read-only</access>
          <resetValue>0</resetValue>
          <resetMask>0xFFFFFFFF</resetMask>
          <fields>
            <field>
              <name>PDI</name>
              <description>Port Data Input</description>
              <bitOffset>0</bitOffset>
              <bitWidth>32</bitWidth>
              <access>read-only</access>
              <enumeratedValues>
                <enumeratedValue>
                  <name>0</name>
                  <description>Pin logic level is logic 0, or is not configured for use by digital function.</description>
                  <value>#0</value>
                </enumeratedValue>
                <enumeratedValue>
                  <name>1</name>
                  <description>Pin logic level is logic 1.</description>
                  <value>#1</value>
                </enumeratedValue>
              </enumeratedValues>
            </field>
          </fields>
        </register>
        <register>
          <name>PDDR</name>
          <description>Port Data Direction Register</description>
          <addressOffset>0x14</addressOffset>
          <size>32</size>
          <access>read-write</access>
          <resetValue>0</resetValue>
          <resetMask>0xFFFFFFFF</resetMask>
          <fields>
            <field>
              <name>PDD</name>
              <description>Port Data Direction</description>
              <bitOffset>0</bitOffset>
              <bitWidth>32</bitWidth>
              <access>read-write</access>
              <enumeratedValues>
                <enumeratedValue>
                  <name>0</name>
                  <description>Pin is configured as general-purpose input, for the GPIO function.</description>
                  <value>#0</value>
                </enumeratedValue>
                <enumeratedValue>
                  <name>1</name>
                  <description>Pin is configured as general-purpose output, for the GPIO function.</description>
                  <value>#1</value>
                </enumeratedValue>
              </enumeratedValues>
            </field>
          </fields>
        </register>
      </registers>
    </peripheral>
    <peripheral>
      <name>GPIOC</name>
      <description>General Purpose Input/Output</description>
      <groupName>GPIO</groupName>
      <prependToName>GPIOC_</prependToName>
      <baseAddress>0x400FF080</baseAddress>
      <addressBlock>
        <offset>0</offset>
        <size>0x18</size>
        <usage>registers</usage>
      </addressBlock>
      <interrupt>
        <name>PORTC_PORTD</name>
        <value>31</value>
      </interrupt>
      <registers>
        <register>
          <name>PDOR</name>
          <description>Port Data Output Register</description>
          <addressOffset>0</addressOffset>
          <size>32</size>
          <access>read-write</access>
          <resetValue>0</resetValue>
          <resetMask>0xFFFFFFFF</resetMask>
          <fields>
            <field>
              <name>PDO</name>
              <description>Port Data Output</description>
              <bitOffset>0</bitOffset>
              <bitWidth>32</bitWidth>
              <access>read-write</access>
              <enumeratedValues>
                <enumeratedValue>
                  <name>0</name>
                  <description>Logic level 0 is driven on pin, provided pin is configured for general-purpose output.</description>
                  <value>#0</value>
                </enumeratedValue>
                <enumeratedValue>
                  <name>1</name>
                  <description>Logic level 1 is driven on pin, provided pin is configured for general-purpose output.</description>
                  <value>#1</value>
                </enumeratedValue>
              </enumeratedValues>
            </field>
          </fields>
        </register>
        <register>
          <name>PSOR</name>
          <description>Port Set Output Register</description>
          <addressOffset>0x4</addressOffset>
          <size>32</size>
          <access>write-only</access>
          <resetValue>0</resetValue>
          <resetMask>0xFFFFFFFF</resetMask>
          <fields>
            <field>
              <name>PTSO</name>
              <description>Port Set Output</description>
              <bitOffset>0</bitOffset>
              <bitWidth>32</bitWidth>
              <access>write-only</access>
              <enumeratedValues>
                <enumeratedValue>
                  <name>0</name>
                  <description>Corresponding bit in PDORn does not change.</description>
                  <value>#0</value>
                </enumeratedValue>
                <enumeratedValue>
                  <name>1</name>
                  <description>Corresponding bit in PDORn is set to logic 1.</description>
                  <value>#1</value>
                </enumeratedValue>
              </enumeratedValues>
            </field>
          </fields>
        </register>
        <register>
          <name>PCOR</name>
          <description>Port Clear Output Register</description>
          <addressOffset>0x8</addressOffset>
          <size>32</size>
          <access>write-only</access>
          <resetValue>0</resetValue>
          <resetMask>0xFFFFFFFF</resetMask>
          <fields>
            <field>
              <name>PTCO</name>
              <description>Port Clear Output</description>
              <bitOffset>0</bitOffset>
              <bitWidth>32</bitWidth>
              <access>write-only</access>
              <enumeratedValues>
                <enumeratedValue>
                  <name>0</name>
                  <description>Corresponding bit in PDORn does not change.</description>
                  <value>#0</value>
                </enumeratedValue>
                <enumeratedValue>
                  <name>1</name>
                  <description>Corresponding bit in PDORn is cleared to logic 0.</description>
                  <value>#1</value>
                </enumeratedValue>
              </enumeratedValues>
            </field>
          </fields>
        </register>
        <register>
          <name>PTOR</name>
          <description>Port Toggle Output Register</description>
          <addressOffset>0xC</addressOffset>
          <size>32</size>
          <access>write-only</access>
          <resetValue>0</resetValue>
          <resetMask>0xFFFFFFFF</resetMask>
          <fields>
            <field>
              <name>PTTO</name>
              <description>Port Toggle Output</description>
              <bitOffset>0</bitOffset>
              <bitWidth>32</bitWidth>
              <access>write-only</access>
              <enumeratedValues>
                <enumeratedValue>
                  <name>0</name>
                  <description>Corresponding bit in PDORn does not change.</description>
                  <value>#0</value>
                </enumeratedValue>
                <enumeratedValue>
                  <name>1</name>
                  <description>Corresponding bit in PDORn is set to the inverse of its existing logic state.</description>
                  <value>#1</value>
                </enumeratedValue>
              </enumeratedValues>
            </field>
          </fields>
        </register>
        <register>
          <name>PDIR</name>
          <description>Port Data Input Register</description>
          <addressOffset>0x10</addressOffset>
          <size>32</size>
          <access>read-only</access>
          <resetValue>0</resetValue>
          <resetMask>0xFFFFFFFF</resetMask>
          <fields>
            <field>
              <name>PDI</name>
              <description>Port Data Input</description>
              <bitOffset>0</bitOffset>
              <bitWidth>32</bitWidth>
              <access>read-only</access>
              <enumeratedValues>
                <enumeratedValue>
                  <name>0</name>
                  <description>Pin logic level is logic 0, or is not configured for use by digital function.</description>
                  <value>#0</value>
                </enumeratedValue>
                <enumeratedValue>
                  <name>1</name>
                  <description>Pin logic level is logic 1.</description>
                  <value>#1</value>
                </enumeratedValue>
              </enumeratedValues>
            </field>
          </fields>
        </register>
        <register>
          <name>PDDR</name>
          <description>Port Data Direction Register</description>
          <addressOffset>0x14</addressOffset>
          <size>32</size>
          <access>read-write</access>
          <resetValue>0</resetValue>
          <resetMask>0xFFFFFFFF</resetMask>
          <fields>
            <field>
              <name>PDD</name>
              <description>Port Data Direction</description>
              <bitOffset>0</bitOffset>
              <bitWidth>32</bitWidth>
              <access>read-write</access>
              <enumeratedValues>
                <enumeratedValue>
                  <name>0</name>
                  <description>Pin is configured as general-purpose input, for the GPIO function.</description>
                  <value>#0</value>
                </enumeratedValue>
                <enumeratedValue>
                  <name>1</name>
                  <description>Pin is configured as general-purpose output, for the GPIO function.</description>
                  <value>#1</value>
                </enumeratedValue>
              </enumeratedValues>
            </field>
          </fields>
        </register>
      </registers>
    </peripheral>
    <peripheral>
      <name>GPIOD</name>
      <description>General Purpose Input/Output</description>
      <groupName>GPIO</groupName>
      <prependToName>GPIOD_</prependToName>
      <baseAddress>0x400FF0C0</baseAddress>
      <addressBlock>
        <offset>0</offset>
        <size>0x18</size>
        <usage>registers</usage>
      </addressBlock>
      <interrupt>
        <name>PORTC_PORTD</name>
        <value>31</value>
      </interrupt>
      <registers>
        <register>
          <name>PDOR</name>
          <description>Port Data Output Register</description>
          <addressOffset>0</addressOffset>
          <size>32</size>
          <access>read-write</access>
          <resetValue>0</resetValue>
          <resetMask>0xFFFFFFFF</resetMask>
          <fields>
            <field>
              <name>PDO</name>
              <description>Port Data Output</description>
              <bitOffset>0</bitOffset>
              <bitWidth>32</bitWidth>
              <access>read-write</access>
              <enumeratedValues>
                <enumeratedValue>
                  <name>0</name>
                  <description>Logic level 0 is driven on pin, provided pin is configured for general-purpose output.</description>
                  <value>#0</value>
                </enumeratedValue>
                <enumeratedValue>
                  <name>1</name>
                  <description>Logic level 1 is driven on pin, provided pin is configured for general-purpose output.</description>
                  <value>#1</value>
                </enumeratedValue>
              </enumeratedValues>
            </field>
          </fields>
        </register>
        <register>
          <name>PSOR</name>
          <description>Port Set Output Register</description>
          <addressOffset>0x4</addressOffset>
          <size>32</size>
          <access>write-only</access>
          <resetValue>0</resetValue>
          <resetMask>0xFFFFFFFF</resetMask>
          <fields>
            <field>
              <name>PTSO</name>
              <description>Port Set Output</description>
              <bitOffset>0</bitOffset>
              <bitWidth>32</bitWidth>
              <access>write-only</access>
              <enumeratedValues>
                <enumeratedValue>
                  <name>0</name>
                  <description>Corresponding bit in PDORn does not change.</description>
                  <value>#0</value>
                </enumeratedValue>
                <enumeratedValue>
                  <name>1</name>
                  <description>Corresponding bit in PDORn is set to logic 1.</description>
                  <value>#1</value>
                </enumeratedValue>
              </enumeratedValues>
            </field>
          </fields>
        </register>
        <register>
          <name>PCOR</name>
          <description>Port Clear Output Register</description>
          <addressOffset>0x8</addressOffset>
          <size>32</size>
          <access>write-only</access>
          <resetValue>0</resetValue>
          <resetMask>0xFFFFFFFF</resetMask>
          <fields>
            <field>
              <name>PTCO</name>
              <description>Port Clear Output</description>
              <bitOffset>0</bitOffset>
              <bitWidth>32</bitWidth>
              <access>write-only</access>
              <enumeratedValues>
                <enumeratedValue>
                  <name>0</name>
                  <description>Corresponding bit in PDORn does not change.</description>
                  <value>#0</value>
                </enumeratedValue>
                <enumeratedValue>
                  <name>1</name>
                  <description>Corresponding bit in PDORn is cleared to logic 0.</description>
                  <value>#1</value>
                </enumeratedValue>
              </enumeratedValues>
            </field>
          </fields>
        </register>
        <register>
          <name>PTOR</name>
          <description>Port Toggle Output Register</description>
          <addressOffset>0xC</addressOffset>
          <size>32</size>
          <access>write-only</access>
          <resetValue>0</resetValue>
          <resetMask>0xFFFFFFFF</resetMask>
          <fields>
            <field>
              <name>PTTO</name>
              <description>Port Toggle Output</description>
              <bitOffset>0</bitOffset>
              <bitWidth>32</bitWidth>
              <access>write-only</access>
              <enumeratedValues>
                <enumeratedValue>
                  <name>0</name>
                  <description>Corresponding bit in PDORn does not change.</description>
                  <value>#0</value>
                </enumeratedValue>
                <enumeratedValue>
                  <name>1</name>
                  <description>Corresponding bit in PDORn is set to the inverse of its existing logic state.</description>
                  <value>#1</value>
                </enumeratedValue>
              </enumeratedValues>
            </field>
          </fields>
        </register>
        <register>
          <name>PDIR</name>
          <description>Port Data Input Register</description>
          <addressOffset>0x10</addressOffset>
          <size>32</size>
          <access>read-only</access>
          <resetValue>0</resetValue>
          <resetMask>0xFFFFFFFF</resetMask>
          <fields>
            <field>
              <name>PDI</name>
              <description>Port Data Input</description>
              <bitOffset>0</bitOffset>
              <bitWidth>32</bitWidth>
              <access>read-only</access>
              <enumeratedValues>
                <enumeratedValue>
                  <name>0</name>
                  <description>Pin logic level is logic 0, or is not configured for use by digital function.</description>
                  <value>#0</value>
                </enumeratedValue>
                <enumeratedValue>
                  <name>1</name>
                  <description>Pin logic level is logic 1.</description>
                  <value>#1</value>
                </enumeratedValue>
              </enumeratedValues>
            </field>
          </fields>
        </register>
        <register>
          <name>PDDR</name>
          <description>Port Data Direction Register</description>
          <addressOffset>0x14</addressOffset>
          <size>32</size>
          <access>read-write</access>
          <resetValue>0</resetValue>
          <resetMask>0xFFFFFFFF</resetMask>
          <fields>
            <field>
              <name>PDD</name>
              <description>Port Data Direction</description>
              <bitOffset>0</bitOffset>
              <bitWidth>32</bitWidth>
              <access>read-write</access>
              <enumeratedValues>
                <enumeratedValue>
                  <name>0</name>
                  <description>Pin is configured as general-purpose input, for the GPIO function.</description>
                  <value>#0</value>
                </enumeratedValue>
                <enumeratedValue>
                  <name>1</name>
                  <description>Pin is configured as general-purpose output, for the GPIO function.</description>
                  <value>#1</value>
                </enumeratedValue>
              </enumeratedValues>
            </field>
          </fields>
        </register>
      </registers>
    </peripheral>
    <peripheral>
      <name>GPIOE</name>
      <description>General Purpose Input/Output</description>
      <groupName>GPIO</groupName>
      <prependToName>GPIOE_</prependToName>
      <baseAddress>0x400FF100</baseAddress>
      <addressBlock>
        <offset>0</offset>
        <size>0x18</size>
        <usage>registers</usage>
      </addressBlock>
      <registers>
        <register>
          <name>PDOR</name>
          <description>Port Data Output Register</description>
          <addressOffset>0</addressOffset>
          <size>32</size>
          <access>read-write</access>
          <resetValue>0</resetValue>
          <resetMask>0xFFFFFFFF</resetMask>
          <fields>
            <field>
              <name>PDO</name>
              <description>Port Data Output</description>
              <bitOffset>0</bitOffset>
              <bitWidth>32</bitWidth>
              <access>read-write</access>
              <enumeratedValues>
                <enumeratedValue>
                  <name>0</name>
                  <description>Logic level 0 is driven on pin, provided pin is configured for general-purpose output.</description>
                  <value>#0</value>
                </enumeratedValue>
                <enumeratedValue>
                  <name>1</name>
                  <description>Logic level 1 is driven on pin, provided pin is configured for general-purpose output.</description>
                  <value>#1</value>
                </enumeratedValue>
              </enumeratedValues>
            </field>
          </fields>
        </register>
        <register>
          <name>PSOR</name>
          <description>Port Set Output Register</description>
          <addressOffset>0x4</addressOffset>
          <size>32</size>
          <access>write-only</access>
          <resetValue>0</resetValue>
          <resetMask>0xFFFFFFFF</resetMask>
          <fields>
            <field>
              <name>PTSO</name>
              <description>Port Set Output</description>
              <bitOffset>0</bitOffset>
              <bitWidth>32</bitWidth>
              <access>write-only</access>
              <enumeratedValues>
                <enumeratedValue>
                  <name>0</name>
                  <description>Corresponding bit in PDORn does not change.</description>
                  <value>#0</value>
                </enumeratedValue>
                <enumeratedValue>
                  <name>1</name>
                  <description>Corresponding bit in PDORn is set to logic 1.</description>
                  <value>#1</value>
                </enumeratedValue>
              </enumeratedValues>
            </field>
          </fields>
        </register>
        <register>
          <name>PCOR</name>
          <description>Port Clear Output Register</description>
          <addressOffset>0x8</addressOffset>
          <size>32</size>
          <access>write-only</access>
          <resetValue>0</resetValue>
          <resetMask>0xFFFFFFFF</resetMask>
          <fields>
            <field>
              <name>PTCO</name>
              <description>Port Clear Output</description>
              <bitOffset>0</bitOffset>
              <bitWidth>32</bitWidth>
              <access>write-only</access>
              <enumeratedValues>
                <enumeratedValue>
                  <name>0</name>
                  <description>Corresponding bit in PDORn does not change.</description>
                  <value>#0</value>
                </enumeratedValue>
                <enumeratedValue>
                  <name>1</name>
                  <description>Corresponding bit in PDORn is cleared to logic 0.</description>
                  <value>#1</value>
                </enumeratedValue>
              </enumeratedValues>
            </field>
          </fields>
        </register>
        <register>
          <name>PTOR</name>
          <description>Port Toggle Output Register</description>
          <addressOffset>0xC</addressOffset>
          <size>32</size>
          <access>write-only</access>
          <resetValue>0</resetValue>
          <resetMask>0xFFFFFFFF</resetMask>
          <fields>
            <field>
              <name>PTTO</name>
              <description>Port Toggle Output</description>
              <bitOffset>0</bitOffset>
              <bitWidth>32</bitWidth>
              <access>write-only</access>
              <enumeratedValues>
                <enumeratedValue>
                  <name>0</name>
                  <description>Corresponding bit in PDORn does not change.</description>
                  <value>#0</value>
                </enumeratedValue>
                <enumeratedValue>
                  <name>1</name>
                  <description>Corresponding bit in PDORn is set to the inverse of its existing logic state.</description>
                  <value>#1</value>
                </enumeratedValue>
              </enumeratedValues>
            </field>
          </fields>
        </register>
        <register>
          <name>PDIR</name>
          <description>Port Data Input Register</description>
          <addressOffset>0x10</addressOffset>
          <size>32</size>
          <access>read-only</access>
          <resetValue>0</resetValue>
          <resetMask>0xFFFFFFFF</resetMask>
          <fields>
            <field>
              <name>PDI</name>
              <description>Port Data Input</description>
              <bitOffset>0</bitOffset>
              <bitWidth>32</bitWidth>
              <access>read-only</access>
              <enumeratedValues>
                <enumeratedValue>
                  <name>0</name>
                  <description>Pin logic level is logic 0, or is not configured for use by digital function.</description>
                  <value>#0</value>
                </enumeratedValue>
                <enumeratedValue>
                  <name>1</name>
                  <description>Pin logic level is logic 1.</description>
                  <value>#1</value>
                </enumeratedValue>
              </enumeratedValues>
            </field>
          </fields>
        </register>
        <register>
          <name>PDDR</name>
          <description>Port Data Direction Register</description>
          <addressOffset>0x14</addressOffset>
          <size>32</size>
          <access>read-write</access>
          <resetValue>0</resetValue>
          <resetMask>0xFFFFFFFF</resetMask>
          <fields>
            <field>
              <name>PDD</name>
              <description>Port Data Direction</description>
              <bitOffset>0</bitOffset>
              <bitWidth>32</bitWidth>
              <access>read-write</access>
              <enumeratedValues>
                <enumeratedValue>
                  <name>0</name>
                  <description>Pin is configured as general-purpose input, for the GPIO function.</description>
                  <value>#0</value>
                </enumeratedValue>
                <enumeratedValue>
                  <name>1</name>
                  <description>Pin is configured as general-purpose output, for the GPIO function.</description>
                  <value>#1</value>
                </enumeratedValue>
              </enumeratedValues>
            </field>
          </fields>
        </register>
      </registers>
    </peripheral>
    <peripheral>
      <name>MTB</name>
      <description>Micro Trace Buffer</description>
      <prependToName>MTB_</prependToName>
      <baseAddress>0xF0000000</baseAddress>
      <addressBlock>
        <offset>0</offset>
        <size>0x1000</size>
        <usage>registers</usage>
      </addressBlock>
      <registers>
        <register>
          <name>POSITION</name>
          <description>MTB Position Register</description>
          <addressOffset>0</addressOffset>
          <size>32</size>
          <access>read-write</access>
          <resetValue>0</resetValue>
          <resetMask>0x3</resetMask>
          <fields>
            <field>
              <name>WRAP</name>
              <description>This field is set to 1 automatically when the POINTER value wraps as determined by the MTB_MASTER[MASK] field in the MASTER Trace Control Register</description>
              <bitOffset>2</bitOffset>
              <bitWidth>1</bitWidth>
              <access>read-write</access>
            </field>
            <field>
              <name>POINTER</name>
              <description>Trace Packet Address Pointer[28:0]</description>
              <bitOffset>3</bitOffset>
              <bitWidth>29</bitWidth>
              <access>read-write</access>
            </field>
          </fields>
        </register>
        <register>
          <name>MASTER</name>
          <description>MTB Master Register</description>
          <addressOffset>0x4</addressOffset>
          <size>32</size>
          <access>read-write</access>
          <resetValue>0x80</resetValue>
          <resetMask>0xFFFFFFE0</resetMask>
          <fields>
            <field>
              <name>MASK</name>
              <description>Mask</description>
              <bitOffset>0</bitOffset>
              <bitWidth>5</bitWidth>
              <access>read-write</access>
            </field>
            <field>
              <name>TSTARTEN</name>
              <description>Trace Start Input Enable</description>
              <bitOffset>5</bitOffset>
              <bitWidth>1</bitWidth>
              <access>read-write</access>
            </field>
            <field>
              <name>TSTOPEN</name>
              <description>Trace Stop Input Enable</description>
              <bitOffset>6</bitOffset>
              <bitWidth>1</bitWidth>
              <access>read-write</access>
            </field>
            <field>
              <name>SFRWPRIV</name>
              <description>Special Function Register Write Privilege</description>
              <bitOffset>7</bitOffset>
              <bitWidth>1</bitWidth>
              <access>read-write</access>
            </field>
            <field>
              <name>RAMPRIV</name>
              <description>RAM Privilege</description>
              <bitOffset>8</bitOffset>
              <bitWidth>1</bitWidth>
              <access>read-write</access>
            </field>
            <field>
              <name>HALTREQ</name>
              <description>Halt Request</description>
              <bitOffset>9</bitOffset>
              <bitWidth>1</bitWidth>
              <access>read-write</access>
            </field>
            <field>
              <name>EN</name>
              <description>Main Trace Enable</description>
              <bitOffset>31</bitOffset>
              <bitWidth>1</bitWidth>
              <access>read-write</access>
            </field>
          </fields>
        </register>
        <register>
          <name>FLOW</name>
          <description>MTB Flow Register</description>
          <addressOffset>0x8</addressOffset>
          <size>32</size>
          <access>read-write</access>
          <resetValue>0</resetValue>
          <resetMask>0x4</resetMask>
          <fields>
            <field>
              <name>AUTOSTOP</name>
              <description>If this field is 1 and WATERMARK is equal to MTB_POSITION[POINTER], then MTB_MASTER[EN] is automatically set to 0</description>
              <bitOffset>0</bitOffset>
              <bitWidth>1</bitWidth>
              <access>read-write</access>
            </field>
            <field>
              <name>AUTOHALT</name>
              <description>If this field is 1 and WATERMARK is equal to MTB_POSITION[POINTER], then MTB_MASTER[HALTREQ] is automatically set to 1</description>
              <bitOffset>1</bitOffset>
              <bitWidth>1</bitWidth>
              <access>read-write</access>
            </field>
            <field>
              <name>WATERMARK</name>
              <description>WATERMARK[28:0]</description>
              <bitOffset>3</bitOffset>
              <bitWidth>29</bitWidth>
              <access>read-write</access>
            </field>
          </fields>
        </register>
        <register>
          <name>BASE</name>
          <description>MTB Base Register</description>
          <addressOffset>0xC</addressOffset>
          <size>32</size>
          <access>read-only</access>
          <resetValue>0</resetValue>
          <resetMask>0</resetMask>
          <fields>
            <field>
              <name>BASEADDR</name>
              <description>This value is defined with a hardwired signal and the expression: 0x2000_0000 - (RAM_Size/4)</description>
              <bitOffset>0</bitOffset>
              <bitWidth>32</bitWidth>
              <access>read-only</access>
            </field>
          </fields>
        </register>
        <register>
          <name>MODECTRL</name>
          <description>Integration Mode Control Register</description>
          <addressOffset>0xF00</addressOffset>
          <size>32</size>
          <access>read-only</access>
          <resetValue>0</resetValue>
          <resetMask>0xFFFFFFFF</resetMask>
          <fields>
            <field>
              <name>MODECTRL</name>
              <description>Hardwired to 0x0000_0000</description>
              <bitOffset>0</bitOffset>
              <bitWidth>32</bitWidth>
              <access>read-only</access>
            </field>
          </fields>
        </register>
        <register>
          <name>TAGSET</name>
          <description>Claim TAG Set Register</description>
          <addressOffset>0xFA0</addressOffset>
          <size>32</size>
          <access>read-only</access>
          <resetValue>0</resetValue>
          <resetMask>0xFFFFFFFF</resetMask>
          <fields>
            <field>
              <name>TAGSET</name>
              <description>Hardwired to 0x0000_0000</description>
              <bitOffset>0</bitOffset>
              <bitWidth>32</bitWidth>
              <access>read-only</access>
            </field>
          </fields>
        </register>
        <register>
          <name>TAGCLEAR</name>
          <description>Claim TAG Clear Register</description>
          <addressOffset>0xFA4</addressOffset>
          <size>32</size>
          <access>read-only</access>
          <resetValue>0</resetValue>
          <resetMask>0xFFFFFFFF</resetMask>
          <fields>
            <field>
              <name>TAGCLEAR</name>
              <description>Hardwired to 0x0000_0000</description>
              <bitOffset>0</bitOffset>
              <bitWidth>32</bitWidth>
              <access>read-only</access>
            </field>
          </fields>
        </register>
        <register>
          <name>LOCKACCESS</name>
          <description>Lock Access Register</description>
          <addressOffset>0xFB0</addressOffset>
          <size>32</size>
          <access>read-only</access>
          <resetValue>0</resetValue>
          <resetMask>0xFFFFFFFF</resetMask>
          <fields>
            <field>
              <name>LOCKACCESS</name>
              <description>Hardwired to 0x0000_0000</description>
              <bitOffset>0</bitOffset>
              <bitWidth>32</bitWidth>
              <access>read-only</access>
            </field>
          </fields>
        </register>
        <register>
          <name>LOCKSTAT</name>
          <description>Lock Status Register</description>
          <addressOffset>0xFB4</addressOffset>
          <size>32</size>
          <access>read-only</access>
          <resetValue>0</resetValue>
          <resetMask>0xFFFFFFFF</resetMask>
          <fields>
            <field>
              <name>LOCKSTAT</name>
              <description>Hardwired to 0x0000_0000</description>
              <bitOffset>0</bitOffset>
              <bitWidth>32</bitWidth>
              <access>read-only</access>
            </field>
          </fields>
        </register>
        <register>
          <name>AUTHSTAT</name>
          <description>Authentication Status Register</description>
          <addressOffset>0xFB8</addressOffset>
          <size>32</size>
          <access>read-only</access>
          <resetValue>0</resetValue>
          <resetMask>0xFFFFFFFF</resetMask>
          <fields>
            <field>
              <name>BIT0</name>
              <description>Connected to DBGEN.</description>
              <bitOffset>0</bitOffset>
              <bitWidth>1</bitWidth>
              <access>read-only</access>
            </field>
            <field>
              <name>BIT1</name>
              <description>Hardwired to 1.</description>
              <bitOffset>1</bitOffset>
              <bitWidth>1</bitWidth>
              <access>read-only</access>
            </field>
            <field>
              <name>BIT2</name>
              <description>Connected to NIDEN or DBGEN signal.</description>
              <bitOffset>2</bitOffset>
              <bitWidth>1</bitWidth>
              <access>read-only</access>
            </field>
            <field>
              <name>BIT3</name>
              <description>Hardwired to 1.</description>
              <bitOffset>3</bitOffset>
              <bitWidth>1</bitWidth>
              <access>read-only</access>
            </field>
          </fields>
        </register>
        <register>
          <name>DEVICEARCH</name>
          <description>Device Architecture Register</description>
          <addressOffset>0xFBC</addressOffset>
          <size>32</size>
          <access>read-only</access>
          <resetValue>0x47700A31</resetValue>
          <resetMask>0xFFFFFFFF</resetMask>
          <fields>
            <field>
              <name>DEVICEARCH</name>
              <description>Hardwired to 0x4770_0A31.</description>
              <bitOffset>0</bitOffset>
              <bitWidth>32</bitWidth>
              <access>read-only</access>
            </field>
          </fields>
        </register>
        <register>
          <name>DEVICECFG</name>
          <description>Device Configuration Register</description>
          <addressOffset>0xFC8</addressOffset>
          <size>32</size>
          <access>read-only</access>
          <resetValue>0</resetValue>
          <resetMask>0xFFFFFFFF</resetMask>
          <fields>
            <field>
              <name>DEVICECFG</name>
              <description>Hardwired to 0x0000_0000.</description>
              <bitOffset>0</bitOffset>
              <bitWidth>32</bitWidth>
              <access>read-only</access>
            </field>
          </fields>
        </register>
        <register>
          <name>DEVICETYPID</name>
          <description>Device Type Identifier Register</description>
          <addressOffset>0xFCC</addressOffset>
          <size>32</size>
          <access>read-only</access>
          <resetValue>0x31</resetValue>
          <resetMask>0xFFFFFFFF</resetMask>
          <fields>
            <field>
              <name>DEVICETYPID</name>
              <description>Hardwired to 0x0000_0031.</description>
              <bitOffset>0</bitOffset>
              <bitWidth>32</bitWidth>
              <access>read-only</access>
            </field>
          </fields>
        </register>
        <register>
          <dim>8</dim>
          <dimIncrement>0x4</dimIncrement>
          <dimIndex>4,5,6,7,0,1,2,3</dimIndex>
          <name>PERIPHID%s</name>
          <description>Peripheral ID Register</description>
          <addressOffset>0xFD0</addressOffset>
          <size>32</size>
          <access>read-only</access>
          <resetValue>0</resetValue>
          <resetMask>0</resetMask>
          <fields>
            <field>
              <name>PERIPHID</name>
              <description>Peripheral ID4 is hardwired to 0x0000_0004; ID0 to 0x0000_0032; ID1 to 0x0000_00B9; ID2 to 0x0000_000B; and all the others to 0x0000_0000</description>
              <bitOffset>0</bitOffset>
              <bitWidth>32</bitWidth>
              <access>read-only</access>
            </field>
          </fields>
        </register>
        <register>
          <dim>4</dim>
          <dimIncrement>0x4</dimIncrement>
          <dimIndex>0,1,2,3</dimIndex>
          <name>COMPID%s</name>
          <description>Component ID Register</description>
          <addressOffset>0xFF0</addressOffset>
          <size>32</size>
          <access>read-only</access>
          <resetValue>0</resetValue>
          <resetMask>0</resetMask>
          <fields>
            <field>
              <name>COMPID</name>
              <description>Component ID</description>
              <bitOffset>0</bitOffset>
              <bitWidth>32</bitWidth>
              <access>read-only</access>
            </field>
          </fields>
        </register>
      </registers>
    </peripheral>
    <peripheral>
      <name>MTBDWT</name>
      <description>MTB data watchpoint and trace</description>
      <prependToName>MTBDWT_</prependToName>
      <baseAddress>0xF0001000</baseAddress>
      <addressBlock>
        <offset>0</offset>
        <size>0x1000</size>
        <usage>registers</usage>
      </addressBlock>
      <registers>
        <register>
          <name>CTRL</name>
          <description>MTB DWT Control Register</description>
          <addressOffset>0</addressOffset>
          <size>32</size>
          <access>read-only</access>
          <resetValue>0x2F000000</resetValue>
          <resetMask>0xFFFFFFFF</resetMask>
          <fields>
            <field>
              <name>DWTCFGCTRL</name>
              <description>DWT configuration controls</description>
              <bitOffset>0</bitOffset>
              <bitWidth>28</bitWidth>
              <access>read-only</access>
            </field>
            <field>
              <name>NUMCMP</name>
              <description>Number of comparators</description>
              <bitOffset>28</bitOffset>
              <bitWidth>4</bitWidth>
              <access>read-only</access>
            </field>
          </fields>
        </register>
        <register>
          <dim>2</dim>
          <dimIncrement>0x10</dimIncrement>
          <dimIndex>0,1</dimIndex>
          <name>COMP%s</name>
          <description>MTB_DWT Comparator Register</description>
          <addressOffset>0x20</addressOffset>
          <size>32</size>
          <access>read-write</access>
          <resetValue>0</resetValue>
          <resetMask>0xFFFFFFFF</resetMask>
          <fields>
            <field>
              <name>COMP</name>
              <description>Reference value for comparison</description>
              <bitOffset>0</bitOffset>
              <bitWidth>32</bitWidth>
              <access>read-write</access>
            </field>
          </fields>
        </register>
        <register>
          <dim>2</dim>
          <dimIncrement>0x10</dimIncrement>
          <dimIndex>0,1</dimIndex>
          <name>MASK%s</name>
          <description>MTB_DWT Comparator Mask Register</description>
          <addressOffset>0x24</addressOffset>
          <size>32</size>
          <access>read-write</access>
          <resetValue>0</resetValue>
          <resetMask>0xFFFFFFFF</resetMask>
          <fields>
            <field>
              <name>MASK</name>
              <description>MASK</description>
              <bitOffset>0</bitOffset>
              <bitWidth>5</bitWidth>
              <access>read-write</access>
            </field>
          </fields>
        </register>
        <register>
          <name>FCT0</name>
          <description>MTB_DWT Comparator Function Register 0</description>
          <addressOffset>0x28</addressOffset>
          <size>32</size>
          <access>read-write</access>
          <resetValue>0</resetValue>
          <resetMask>0xFFFFFFFF</resetMask>
          <fields>
            <field>
              <name>FUNCTION</name>
              <description>Function</description>
              <bitOffset>0</bitOffset>
              <bitWidth>4</bitWidth>
              <access>read-write</access>
              <enumeratedValues>
                <enumeratedValue>
                  <name>0000</name>
                  <description>Disabled.</description>
                  <value>#0000</value>
                </enumeratedValue>
                <enumeratedValue>
                  <name>0100</name>
                  <description>Instruction fetch.</description>
                  <value>#0100</value>
                </enumeratedValue>
                <enumeratedValue>
                  <name>0101</name>
                  <description>Data operand read.</description>
                  <value>#0101</value>
                </enumeratedValue>
                <enumeratedValue>
                  <name>0110</name>
                  <description>Data operand write.</description>
                  <value>#0110</value>
                </enumeratedValue>
                <enumeratedValue>
                  <name>0111</name>
                  <description>Data operand (read + write).</description>
                  <value>#0111</value>
                </enumeratedValue>
              </enumeratedValues>
            </field>
            <field>
              <name>DATAVMATCH</name>
              <description>Data Value Match</description>
              <bitOffset>8</bitOffset>
              <bitWidth>1</bitWidth>
              <access>read-write</access>
              <enumeratedValues>
                <enumeratedValue>
                  <name>0</name>
                  <description>Perform address comparison.</description>
                  <value>#0</value>
                </enumeratedValue>
                <enumeratedValue>
                  <name>1</name>
                  <description>Perform data value comparison.</description>
                  <value>#1</value>
                </enumeratedValue>
              </enumeratedValues>
            </field>
            <field>
              <name>DATAVSIZE</name>
              <description>Data Value Size</description>
              <bitOffset>10</bitOffset>
              <bitWidth>2</bitWidth>
              <access>read-write</access>
              <enumeratedValues>
                <enumeratedValue>
                  <name>00</name>
                  <description>Byte.</description>
                  <value>#00</value>
                </enumeratedValue>
                <enumeratedValue>
                  <name>01</name>
                  <description>Halfword.</description>
                  <value>#01</value>
                </enumeratedValue>
                <enumeratedValue>
                  <name>10</name>
                  <description>Word.</description>
                  <value>#10</value>
                </enumeratedValue>
                <enumeratedValue>
                  <name>11</name>
                  <description>Reserved. Any attempts to use this value results in UNPREDICTABLE behavior.</description>
                  <value>#11</value>
                </enumeratedValue>
              </enumeratedValues>
            </field>
            <field>
              <name>DATAVADDR0</name>
              <description>Data Value Address 0</description>
              <bitOffset>12</bitOffset>
              <bitWidth>4</bitWidth>
              <access>read-write</access>
            </field>
            <field>
              <name>MATCHED</name>
              <description>Comparator match</description>
              <bitOffset>24</bitOffset>
              <bitWidth>1</bitWidth>
              <access>read-only</access>
              <enumeratedValues>
                <enumeratedValue>
                  <name>0</name>
                  <description>No match.</description>
                  <value>#0</value>
                </enumeratedValue>
                <enumeratedValue>
                  <name>1</name>
                  <description>Match occurred.</description>
                  <value>#1</value>
                </enumeratedValue>
              </enumeratedValues>
            </field>
          </fields>
        </register>
        <register>
          <name>FCT1</name>
          <description>MTB_DWT Comparator Function Register 1</description>
          <addressOffset>0x38</addressOffset>
          <size>32</size>
          <access>read-write</access>
          <resetValue>0</resetValue>
          <resetMask>0xFFFFFFFF</resetMask>
          <fields>
            <field>
              <name>FUNCTION</name>
              <description>Function</description>
              <bitOffset>0</bitOffset>
              <bitWidth>4</bitWidth>
              <access>read-write</access>
              <enumeratedValues>
                <enumeratedValue>
                  <name>0000</name>
                  <description>Disabled.</description>
                  <value>#0000</value>
                </enumeratedValue>
                <enumeratedValue>
                  <name>0100</name>
                  <description>Instruction fetch.</description>
                  <value>#0100</value>
                </enumeratedValue>
                <enumeratedValue>
                  <name>0101</name>
                  <description>Data operand read.</description>
                  <value>#0101</value>
                </enumeratedValue>
                <enumeratedValue>
                  <name>0110</name>
                  <description>Data operand write.</description>
                  <value>#0110</value>
                </enumeratedValue>
                <enumeratedValue>
                  <name>0111</name>
                  <description>Data operand (read + write).</description>
                  <value>#0111</value>
                </enumeratedValue>
              </enumeratedValues>
            </field>
            <field>
              <name>MATCHED</name>
              <description>Comparator match</description>
              <bitOffset>24</bitOffset>
              <bitWidth>1</bitWidth>
              <access>read-only</access>
              <enumeratedValues>
                <enumeratedValue>
                  <name>0</name>
                  <description>No match.</description>
                  <value>#0</value>
                </enumeratedValue>
                <enumeratedValue>
                  <name>1</name>
                  <description>Match occurred.</description>
                  <value>#1</value>
                </enumeratedValue>
              </enumeratedValues>
            </field>
          </fields>
        </register>
        <register>
          <name>TBCTRL</name>
          <description>MTB_DWT Trace Buffer Control Register</description>
          <addressOffset>0x200</addressOffset>
          <size>32</size>
          <access>read-write</access>
          <resetValue>0x20000000</resetValue>
          <resetMask>0xFFFFFFFF</resetMask>
          <fields>
            <field>
              <name>ACOMP0</name>
              <description>Action based on Comparator 0 match</description>
              <bitOffset>0</bitOffset>
              <bitWidth>1</bitWidth>
              <access>read-write</access>
              <enumeratedValues>
                <enumeratedValue>
                  <name>0</name>
                  <description>Trigger TSTOP based on the assertion of MTBDWT_FCT0[MATCHED].</description>
                  <value>#0</value>
                </enumeratedValue>
                <enumeratedValue>
                  <name>1</name>
                  <description>Trigger TSTART based on the assertion of MTBDWT_FCT0[MATCHED].</description>
                  <value>#1</value>
                </enumeratedValue>
              </enumeratedValues>
            </field>
            <field>
              <name>ACOMP1</name>
              <description>Action based on Comparator 1 match</description>
              <bitOffset>1</bitOffset>
              <bitWidth>1</bitWidth>
              <access>read-write</access>
              <enumeratedValues>
                <enumeratedValue>
                  <name>0</name>
                  <description>Trigger TSTOP based on the assertion of MTBDWT_FCT1[MATCHED].</description>
                  <value>#0</value>
                </enumeratedValue>
                <enumeratedValue>
                  <name>1</name>
                  <description>Trigger TSTART based on the assertion of MTBDWT_FCT1[MATCHED].</description>
                  <value>#1</value>
                </enumeratedValue>
              </enumeratedValues>
            </field>
            <field>
              <name>NUMCOMP</name>
              <description>Number of Comparators</description>
              <bitOffset>28</bitOffset>
              <bitWidth>4</bitWidth>
              <access>read-only</access>
            </field>
          </fields>
        </register>
        <register>
          <name>DEVICECFG</name>
          <description>Device Configuration Register</description>
          <addressOffset>0xFC8</addressOffset>
          <size>32</size>
          <access>read-only</access>
          <resetValue>0</resetValue>
          <resetMask>0xFFFFFFFF</resetMask>
          <fields>
            <field>
              <name>DEVICECFG</name>
              <description>Hardwired to 0x0000_0000.</description>
              <bitOffset>0</bitOffset>
              <bitWidth>32</bitWidth>
              <access>read-only</access>
            </field>
          </fields>
        </register>
        <register>
          <name>DEVICETYPID</name>
          <description>Device Type Identifier Register</description>
          <addressOffset>0xFCC</addressOffset>
          <size>32</size>
          <access>read-only</access>
          <resetValue>0x4</resetValue>
          <resetMask>0xFFFFFFFF</resetMask>
          <fields>
            <field>
              <name>DEVICETYPID</name>
              <description>Hardwired to 0x0000_0004.</description>
              <bitOffset>0</bitOffset>
              <bitWidth>32</bitWidth>
              <access>read-only</access>
            </field>
          </fields>
        </register>
        <register>
          <dim>8</dim>
          <dimIncrement>0x4</dimIncrement>
          <dimIndex>4,5,6,7,0,1,2,3</dimIndex>
          <name>PERIPHID%s</name>
          <description>Peripheral ID Register</description>
          <addressOffset>0xFD0</addressOffset>
          <size>32</size>
          <access>read-only</access>
          <resetValue>0</resetValue>
          <resetMask>0</resetMask>
          <fields>
            <field>
              <name>PERIPHID</name>
              <description>Peripheral ID1 is hardwired to 0x0000_00E0; ID2 to 0x0000_0008; and all the others to 0x0000_0000.</description>
              <bitOffset>0</bitOffset>
              <bitWidth>32</bitWidth>
              <access>read-only</access>
            </field>
          </fields>
        </register>
        <register>
          <dim>4</dim>
          <dimIncrement>0x4</dimIncrement>
          <dimIndex>0,1,2,3</dimIndex>
          <name>COMPID%s</name>
          <description>Component ID Register</description>
          <addressOffset>0xFF0</addressOffset>
          <size>32</size>
          <access>read-only</access>
          <resetValue>0</resetValue>
          <resetMask>0</resetMask>
          <fields>
            <field>
              <name>COMPID</name>
              <description>Component ID</description>
              <bitOffset>0</bitOffset>
              <bitWidth>32</bitWidth>
              <access>read-only</access>
            </field>
          </fields>
        </register>
      </registers>
    </peripheral>
    <peripheral>
      <name>ROM</name>
      <description>System ROM</description>
      <prependToName>ROM_</prependToName>
      <baseAddress>0xF0002000</baseAddress>
      <addressBlock>
        <offset>0</offset>
        <size>0x1000</size>
        <usage>registers</usage>
      </addressBlock>
      <registers>
        <register>
          <dim>3</dim>
          <dimIncrement>0x4</dimIncrement>
          <dimIndex>0,1,2</dimIndex>
          <name>ENTRY%s</name>
          <description>Entry</description>
          <addressOffset>0</addressOffset>
          <size>32</size>
          <access>read-only</access>
          <resetValue>0</resetValue>
          <resetMask>0</resetMask>
          <fields>
            <field>
              <name>ENTRY</name>
              <description>ENTRY</description>
              <bitOffset>0</bitOffset>
              <bitWidth>32</bitWidth>
              <access>read-only</access>
            </field>
          </fields>
        </register>
        <register>
          <name>TABLEMARK</name>
          <description>End of Table Marker Register</description>
          <addressOffset>0xC</addressOffset>
          <size>32</size>
          <access>read-only</access>
          <resetValue>0</resetValue>
          <resetMask>0xFFFFFFFF</resetMask>
          <fields>
            <field>
              <name>MARK</name>
              <description>Hardwired to 0x0000_0000</description>
              <bitOffset>0</bitOffset>
              <bitWidth>32</bitWidth>
              <access>read-only</access>
            </field>
          </fields>
        </register>
        <register>
          <name>SYSACCESS</name>
          <description>System Access Register</description>
          <addressOffset>0xFCC</addressOffset>
          <size>32</size>
          <access>read-only</access>
          <resetValue>0x1</resetValue>
          <resetMask>0xFFFFFFFF</resetMask>
          <fields>
            <field>
              <name>SYSACCESS</name>
              <description>Hardwired to 0x0000_0001</description>
              <bitOffset>0</bitOffset>
              <bitWidth>32</bitWidth>
              <access>read-only</access>
            </field>
          </fields>
        </register>
        <register>
          <dim>8</dim>
          <dimIncrement>0x4</dimIncrement>
          <dimIndex>4,5,6,7,0,1,2,3</dimIndex>
          <name>PERIPHID%s</name>
          <description>Peripheral ID Register</description>
          <addressOffset>0xFD0</addressOffset>
          <size>32</size>
          <access>read-only</access>
          <resetValue>0</resetValue>
          <resetMask>0</resetMask>
          <fields>
            <field>
              <name>PERIPHID</name>
              <description>Peripheral ID1 is hardwired to 0x0000_00E0; ID2 to 0x0000_0008; and all the others to 0x0000_0000.</description>
              <bitOffset>0</bitOffset>
              <bitWidth>32</bitWidth>
              <access>read-only</access>
            </field>
          </fields>
        </register>
        <register>
          <dim>4</dim>
          <dimIncrement>0x4</dimIncrement>
          <dimIndex>0,1,2,3</dimIndex>
          <name>COMPID%s</name>
          <description>Component ID Register</description>
          <addressOffset>0xFF0</addressOffset>
          <size>32</size>
          <access>read-only</access>
          <resetValue>0</resetValue>
          <resetMask>0</resetMask>
          <fields>
            <field>
              <name>COMPID</name>
              <description>Component ID</description>
              <bitOffset>0</bitOffset>
              <bitWidth>32</bitWidth>
              <access>read-only</access>
            </field>
          </fields>
        </register>
      </registers>
    </peripheral>
    <peripheral>
      <name>MCM</name>
      <description>Core Platform Miscellaneous Control Module</description>
      <prependToName>MCM_</prependToName>
      <baseAddress>0xF0003000</baseAddress>
      <addressBlock>
        <offset>0x8</offset>
        <size>0x3C</size>
        <usage>registers</usage>
      </addressBlock>
      <registers>
        <register>
          <name>PLASC</name>
          <description>Crossbar Switch (AXBS) Slave Configuration</description>
          <addressOffset>0x8</addressOffset>
          <size>16</size>
          <access>read-only</access>
          <resetValue>0x7</resetValue>
          <resetMask>0xFFFF</resetMask>
          <fields>
            <field>
              <name>ASC</name>
              <description>Each bit in the ASC field indicates whether there is a corresponding connection to the crossbar switch&apos;s slave input port.</description>
              <bitOffset>0</bitOffset>
              <bitWidth>8</bitWidth>
              <access>read-only</access>
              <enumeratedValues>
                <enumeratedValue>
                  <name>0</name>
                  <description>A bus slave connection to AXBS input port n is absent.</description>
                  <value>#0</value>
                </enumeratedValue>
                <enumeratedValue>
                  <name>1</name>
                  <description>A bus slave connection to AXBS input port n is present.</description>
                  <value>#1</value>
                </enumeratedValue>
              </enumeratedValues>
            </field>
          </fields>
        </register>
        <register>
          <name>PLAMC</name>
          <description>Crossbar Switch (AXBS) Master Configuration</description>
          <addressOffset>0xA</addressOffset>
          <size>16</size>
          <access>read-only</access>
          <resetValue>0xD</resetValue>
          <resetMask>0xFFFF</resetMask>
          <fields>
            <field>
              <name>AMC</name>
              <description>Each bit in the AMC field indicates whether there is a corresponding connection to the AXBS master input port.</description>
              <bitOffset>0</bitOffset>
              <bitWidth>8</bitWidth>
              <access>read-only</access>
              <enumeratedValues>
                <enumeratedValue>
                  <name>0</name>
                  <description>A bus master connection to AXBS input port n is absent</description>
                  <value>#0</value>
                </enumeratedValue>
                <enumeratedValue>
                  <name>1</name>
                  <description>A bus master connection to AXBS input port n is present</description>
                  <value>#1</value>
                </enumeratedValue>
              </enumeratedValues>
            </field>
          </fields>
        </register>
        <register>
          <name>PLACR</name>
          <description>Platform Control Register</description>
          <addressOffset>0xC</addressOffset>
          <size>32</size>
          <access>read-write</access>
          <resetValue>0</resetValue>
          <resetMask>0xFFFFFFFF</resetMask>
          <fields>
            <field>
              <name>ARB</name>
              <description>Arbitration select</description>
              <bitOffset>9</bitOffset>
              <bitWidth>1</bitWidth>
              <access>read-write</access>
              <enumeratedValues>
                <enumeratedValue>
                  <name>0</name>
                  <description>Fixed-priority arbitration for the crossbar masters</description>
                  <value>#0</value>
                </enumeratedValue>
                <enumeratedValue>
                  <name>1</name>
                  <description>Round-robin arbitration for the crossbar masters</description>
                  <value>#1</value>
                </enumeratedValue>
              </enumeratedValues>
            </field>
            <field>
              <name>CFCC</name>
              <description>Clear Flash Controller Cache</description>
              <bitOffset>10</bitOffset>
              <bitWidth>1</bitWidth>
              <access>write-only</access>
            </field>
            <field>
              <name>DFCDA</name>
              <description>Disable Flash Controller Data Caching</description>
              <bitOffset>11</bitOffset>
              <bitWidth>1</bitWidth>
              <access>read-write</access>
              <enumeratedValues>
                <enumeratedValue>
                  <name>0</name>
                  <description>Enable flash controller data caching</description>
                  <value>#0</value>
                </enumeratedValue>
                <enumeratedValue>
                  <name>1</name>
                  <description>Disable flash controller data caching.</description>
                  <value>#1</value>
                </enumeratedValue>
              </enumeratedValues>
            </field>
            <field>
              <name>DFCIC</name>
              <description>Disable Flash Controller Instruction Caching</description>
              <bitOffset>12</bitOffset>
              <bitWidth>1</bitWidth>
              <access>read-write</access>
              <enumeratedValues>
                <enumeratedValue>
                  <name>0</name>
                  <description>Enable flash controller instruction caching.</description>
                  <value>#0</value>
                </enumeratedValue>
                <enumeratedValue>
                  <name>1</name>
                  <description>Disable flash controller instruction caching.</description>
                  <value>#1</value>
                </enumeratedValue>
              </enumeratedValues>
            </field>
            <field>
              <name>DFCC</name>
              <description>Disable Flash Controller Cache</description>
              <bitOffset>13</bitOffset>
              <bitWidth>1</bitWidth>
              <access>read-write</access>
              <enumeratedValues>
                <enumeratedValue>
                  <name>0</name>
                  <description>Enable flash controller cache.</description>
                  <value>#0</value>
                </enumeratedValue>
                <enumeratedValue>
                  <name>1</name>
                  <description>Disable flash controller cache.</description>
                  <value>#1</value>
                </enumeratedValue>
              </enumeratedValues>
            </field>
            <field>
              <name>EFDS</name>
              <description>Enable Flash Data Speculation</description>
              <bitOffset>14</bitOffset>
              <bitWidth>1</bitWidth>
              <access>read-write</access>
              <enumeratedValues>
                <enumeratedValue>
                  <name>0</name>
                  <description>Disable flash data speculation.</description>
                  <value>#0</value>
                </enumeratedValue>
                <enumeratedValue>
                  <name>1</name>
                  <description>Enable flash data speculation.</description>
                  <value>#1</value>
                </enumeratedValue>
              </enumeratedValues>
            </field>
            <field>
              <name>DFCS</name>
              <description>Disable Flash Controller Speculation</description>
              <bitOffset>15</bitOffset>
              <bitWidth>1</bitWidth>
              <access>read-write</access>
              <enumeratedValues>
                <enumeratedValue>
                  <name>0</name>
                  <description>Enable flash controller speculation.</description>
                  <value>#0</value>
                </enumeratedValue>
                <enumeratedValue>
                  <name>1</name>
                  <description>Disable flash controller speculation.</description>
                  <value>#1</value>
                </enumeratedValue>
              </enumeratedValues>
            </field>
            <field>
              <name>ESFC</name>
              <description>Enable Stalling Flash Controller</description>
              <bitOffset>16</bitOffset>
              <bitWidth>1</bitWidth>
              <access>read-write</access>
              <enumeratedValues>
                <enumeratedValue>
                  <name>0</name>
                  <description>Disable stalling flash controller when flash is busy.</description>
                  <value>#0</value>
                </enumeratedValue>
                <enumeratedValue>
                  <name>1</name>
                  <description>Enable stalling flash controller when flash is busy.</description>
                  <value>#1</value>
                </enumeratedValue>
              </enumeratedValues>
            </field>
          </fields>
        </register>
        <register>
          <name>CPO</name>
          <description>Compute Operation Control Register</description>
          <addressOffset>0x40</addressOffset>
          <size>32</size>
          <access>read-write</access>
          <resetValue>0</resetValue>
          <resetMask>0xFFFFFFFF</resetMask>
          <fields>
            <field>
              <name>CPOREQ</name>
              <description>Compute Operation Request</description>
              <bitOffset>0</bitOffset>
              <bitWidth>1</bitWidth>
              <access>read-write</access>
              <enumeratedValues>
                <enumeratedValue>
                  <name>0</name>
                  <description>Request is cleared.</description>
                  <value>#0</value>
                </enumeratedValue>
                <enumeratedValue>
                  <name>1</name>
                  <description>Request Compute Operation.</description>
                  <value>#1</value>
                </enumeratedValue>
              </enumeratedValues>
            </field>
            <field>
              <name>CPOACK</name>
              <description>Compute Operation Acknowledge</description>
              <bitOffset>1</bitOffset>
              <bitWidth>1</bitWidth>
              <access>read-only</access>
              <enumeratedValues>
                <enumeratedValue>
                  <name>0</name>
                  <description>Compute operation entry has not completed or compute operation exit has completed.</description>
                  <value>#0</value>
                </enumeratedValue>
                <enumeratedValue>
                  <name>1</name>
                  <description>Compute operation entry has completed or compute operation exit has not completed.</description>
                  <value>#1</value>
                </enumeratedValue>
              </enumeratedValues>
            </field>
            <field>
              <name>CPOWOI</name>
              <description>Compute Operation Wake-up on Interrupt</description>
              <bitOffset>2</bitOffset>
              <bitWidth>1</bitWidth>
              <access>read-write</access>
              <enumeratedValues>
                <enumeratedValue>
                  <name>0</name>
                  <description>No effect.</description>
                  <value>#0</value>
                </enumeratedValue>
                <enumeratedValue>
                  <name>1</name>
                  <description>When set, the CPOREQ is cleared on any interrupt or exception vector fetch.</description>
                  <value>#1</value>
                </enumeratedValue>
              </enumeratedValues>
            </field>
          </fields>
        </register>
      </registers>
    </peripheral>
    <peripheral>
      <name>FGPIOA</name>
      <description>General Purpose Input/Output</description>
      <groupName>FGPIO</groupName>
      <prependToName>FGPIOA_</prependToName>
      <baseAddress>0xF8000000</baseAddress>
      <addressBlock>
        <offset>0</offset>
        <size>0x18</size>
        <usage>registers</usage>
      </addressBlock>
      <registers>
        <register>
          <name>PDOR</name>
          <description>Port Data Output Register</description>
          <addressOffset>0</addressOffset>
          <size>32</size>
          <access>read-write</access>
          <resetValue>0</resetValue>
          <resetMask>0xFFFFFFFF</resetMask>
          <fields>
            <field>
              <name>PDO</name>
              <description>Port Data Output</description>
              <bitOffset>0</bitOffset>
              <bitWidth>32</bitWidth>
              <access>read-write</access>
              <enumeratedValues>
                <enumeratedValue>
                  <name>0</name>
                  <description>Logic level 0 is driven on pin, provided pin is configured for general-purpose output.</description>
                  <value>#0</value>
                </enumeratedValue>
                <enumeratedValue>
                  <name>1</name>
                  <description>Logic level 1 is driven on pin, provided pin is configured for general-purpose output.</description>
                  <value>#1</value>
                </enumeratedValue>
              </enumeratedValues>
            </field>
          </fields>
        </register>
        <register>
          <name>PSOR</name>
          <description>Port Set Output Register</description>
          <addressOffset>0x4</addressOffset>
          <size>32</size>
          <access>write-only</access>
          <resetValue>0</resetValue>
          <resetMask>0xFFFFFFFF</resetMask>
          <fields>
            <field>
              <name>PTSO</name>
              <description>Port Set Output</description>
              <bitOffset>0</bitOffset>
              <bitWidth>32</bitWidth>
              <access>write-only</access>
              <enumeratedValues>
                <enumeratedValue>
                  <name>0</name>
                  <description>Corresponding bit in PDORn does not change.</description>
                  <value>#0</value>
                </enumeratedValue>
                <enumeratedValue>
                  <name>1</name>
                  <description>Corresponding bit in PDORn is set to logic 1.</description>
                  <value>#1</value>
                </enumeratedValue>
              </enumeratedValues>
            </field>
          </fields>
        </register>
        <register>
          <name>PCOR</name>
          <description>Port Clear Output Register</description>
          <addressOffset>0x8</addressOffset>
          <size>32</size>
          <access>write-only</access>
          <resetValue>0</resetValue>
          <resetMask>0xFFFFFFFF</resetMask>
          <fields>
            <field>
              <name>PTCO</name>
              <description>Port Clear Output</description>
              <bitOffset>0</bitOffset>
              <bitWidth>32</bitWidth>
              <access>write-only</access>
              <enumeratedValues>
                <enumeratedValue>
                  <name>0</name>
                  <description>Corresponding bit in PDORn does not change.</description>
                  <value>#0</value>
                </enumeratedValue>
                <enumeratedValue>
                  <name>1</name>
                  <description>Corresponding bit in PDORn is cleared to logic 0.</description>
                  <value>#1</value>
                </enumeratedValue>
              </enumeratedValues>
            </field>
          </fields>
        </register>
        <register>
          <name>PTOR</name>
          <description>Port Toggle Output Register</description>
          <addressOffset>0xC</addressOffset>
          <size>32</size>
          <access>write-only</access>
          <resetValue>0</resetValue>
          <resetMask>0xFFFFFFFF</resetMask>
          <fields>
            <field>
              <name>PTTO</name>
              <description>Port Toggle Output</description>
              <bitOffset>0</bitOffset>
              <bitWidth>32</bitWidth>
              <access>write-only</access>
              <enumeratedValues>
                <enumeratedValue>
                  <name>0</name>
                  <description>Corresponding bit in PDORn does not change.</description>
                  <value>#0</value>
                </enumeratedValue>
                <enumeratedValue>
                  <name>1</name>
                  <description>Corresponding bit in PDORn is set to the inverse of its existing logic state.</description>
                  <value>#1</value>
                </enumeratedValue>
              </enumeratedValues>
            </field>
          </fields>
        </register>
        <register>
          <name>PDIR</name>
          <description>Port Data Input Register</description>
          <addressOffset>0x10</addressOffset>
          <size>32</size>
          <access>read-only</access>
          <resetValue>0</resetValue>
          <resetMask>0xFFFFFFFF</resetMask>
          <fields>
            <field>
              <name>PDI</name>
              <description>Port Data Input</description>
              <bitOffset>0</bitOffset>
              <bitWidth>32</bitWidth>
              <access>read-only</access>
              <enumeratedValues>
                <enumeratedValue>
                  <name>0</name>
                  <description>Pin logic level is logic 0, or is not configured for use by digital function.</description>
                  <value>#0</value>
                </enumeratedValue>
                <enumeratedValue>
                  <name>1</name>
                  <description>Pin logic level is logic 1.</description>
                  <value>#1</value>
                </enumeratedValue>
              </enumeratedValues>
            </field>
          </fields>
        </register>
        <register>
          <name>PDDR</name>
          <description>Port Data Direction Register</description>
          <addressOffset>0x14</addressOffset>
          <size>32</size>
          <access>read-write</access>
          <resetValue>0</resetValue>
          <resetMask>0xFFFFFFFF</resetMask>
          <fields>
            <field>
              <name>PDD</name>
              <description>Port Data Direction</description>
              <bitOffset>0</bitOffset>
              <bitWidth>32</bitWidth>
              <access>read-write</access>
              <enumeratedValues>
                <enumeratedValue>
                  <name>0</name>
                  <description>Pin is configured as general-purpose input, for the GPIO function.</description>
                  <value>#0</value>
                </enumeratedValue>
                <enumeratedValue>
                  <name>1</name>
                  <description>Pin is configured as general-purpose output, for the GPIO function.</description>
                  <value>#1</value>
                </enumeratedValue>
              </enumeratedValues>
            </field>
          </fields>
        </register>
      </registers>
    </peripheral>
    <peripheral>
      <name>FGPIOB</name>
      <description>General Purpose Input/Output</description>
      <groupName>FGPIO</groupName>
      <prependToName>FGPIOB_</prependToName>
      <baseAddress>0xF8000040</baseAddress>
      <addressBlock>
        <offset>0</offset>
        <size>0x18</size>
        <usage>registers</usage>
      </addressBlock>
      <registers>
        <register>
          <name>PDOR</name>
          <description>Port Data Output Register</description>
          <addressOffset>0</addressOffset>
          <size>32</size>
          <access>read-write</access>
          <resetValue>0</resetValue>
          <resetMask>0xFFFFFFFF</resetMask>
          <fields>
            <field>
              <name>PDO</name>
              <description>Port Data Output</description>
              <bitOffset>0</bitOffset>
              <bitWidth>32</bitWidth>
              <access>read-write</access>
              <enumeratedValues>
                <enumeratedValue>
                  <name>0</name>
                  <description>Logic level 0 is driven on pin, provided pin is configured for general-purpose output.</description>
                  <value>#0</value>
                </enumeratedValue>
                <enumeratedValue>
                  <name>1</name>
                  <description>Logic level 1 is driven on pin, provided pin is configured for general-purpose output.</description>
                  <value>#1</value>
                </enumeratedValue>
              </enumeratedValues>
            </field>
          </fields>
        </register>
        <register>
          <name>PSOR</name>
          <description>Port Set Output Register</description>
          <addressOffset>0x4</addressOffset>
          <size>32</size>
          <access>write-only</access>
          <resetValue>0</resetValue>
          <resetMask>0xFFFFFFFF</resetMask>
          <fields>
            <field>
              <name>PTSO</name>
              <description>Port Set Output</description>
              <bitOffset>0</bitOffset>
              <bitWidth>32</bitWidth>
              <access>write-only</access>
              <enumeratedValues>
                <enumeratedValue>
                  <name>0</name>
                  <description>Corresponding bit in PDORn does not change.</description>
                  <value>#0</value>
                </enumeratedValue>
                <enumeratedValue>
                  <name>1</name>
                  <description>Corresponding bit in PDORn is set to logic 1.</description>
                  <value>#1</value>
                </enumeratedValue>
              </enumeratedValues>
            </field>
          </fields>
        </register>
        <register>
          <name>PCOR</name>
          <description>Port Clear Output Register</description>
          <addressOffset>0x8</addressOffset>
          <size>32</size>
          <access>write-only</access>
          <resetValue>0</resetValue>
          <resetMask>0xFFFFFFFF</resetMask>
          <fields>
            <field>
              <name>PTCO</name>
              <description>Port Clear Output</description>
              <bitOffset>0</bitOffset>
              <bitWidth>32</bitWidth>
              <access>write-only</access>
              <enumeratedValues>
                <enumeratedValue>
                  <name>0</name>
                  <description>Corresponding bit in PDORn does not change.</description>
                  <value>#0</value>
                </enumeratedValue>
                <enumeratedValue>
                  <name>1</name>
                  <description>Corresponding bit in PDORn is cleared to logic 0.</description>
                  <value>#1</value>
                </enumeratedValue>
              </enumeratedValues>
            </field>
          </fields>
        </register>
        <register>
          <name>PTOR</name>
          <description>Port Toggle Output Register</description>
          <addressOffset>0xC</addressOffset>
          <size>32</size>
          <access>write-only</access>
          <resetValue>0</resetValue>
          <resetMask>0xFFFFFFFF</resetMask>
          <fields>
            <field>
              <name>PTTO</name>
              <description>Port Toggle Output</description>
              <bitOffset>0</bitOffset>
              <bitWidth>32</bitWidth>
              <access>write-only</access>
              <enumeratedValues>
                <enumeratedValue>
                  <name>0</name>
                  <description>Corresponding bit in PDORn does not change.</description>
                  <value>#0</value>
                </enumeratedValue>
                <enumeratedValue>
                  <name>1</name>
                  <description>Corresponding bit in PDORn is set to the inverse of its existing logic state.</description>
                  <value>#1</value>
                </enumeratedValue>
              </enumeratedValues>
            </field>
          </fields>
        </register>
        <register>
          <name>PDIR</name>
          <description>Port Data Input Register</description>
          <addressOffset>0x10</addressOffset>
          <size>32</size>
          <access>read-only</access>
          <resetValue>0</resetValue>
          <resetMask>0xFFFFFFFF</resetMask>
          <fields>
            <field>
              <name>PDI</name>
              <description>Port Data Input</description>
              <bitOffset>0</bitOffset>
              <bitWidth>32</bitWidth>
              <access>read-only</access>
              <enumeratedValues>
                <enumeratedValue>
                  <name>0</name>
                  <description>Pin logic level is logic 0, or is not configured for use by digital function.</description>
                  <value>#0</value>
                </enumeratedValue>
                <enumeratedValue>
                  <name>1</name>
                  <description>Pin logic level is logic 1.</description>
                  <value>#1</value>
                </enumeratedValue>
              </enumeratedValues>
            </field>
          </fields>
        </register>
        <register>
          <name>PDDR</name>
          <description>Port Data Direction Register</description>
          <addressOffset>0x14</addressOffset>
          <size>32</size>
          <access>read-write</access>
          <resetValue>0</resetValue>
          <resetMask>0xFFFFFFFF</resetMask>
          <fields>
            <field>
              <name>PDD</name>
              <description>Port Data Direction</description>
              <bitOffset>0</bitOffset>
              <bitWidth>32</bitWidth>
              <access>read-write</access>
              <enumeratedValues>
                <enumeratedValue>
                  <name>0</name>
                  <description>Pin is configured as general-purpose input, for the GPIO function.</description>
                  <value>#0</value>
                </enumeratedValue>
                <enumeratedValue>
                  <name>1</name>
                  <description>Pin is configured as general-purpose output, for the GPIO function.</description>
                  <value>#1</value>
                </enumeratedValue>
              </enumeratedValues>
            </field>
          </fields>
        </register>
      </registers>
    </peripheral>
    <peripheral>
      <name>FGPIOC</name>
      <description>General Purpose Input/Output</description>
      <groupName>FGPIO</groupName>
      <prependToName>FGPIOC_</prependToName>
      <baseAddress>0xF8000080</baseAddress>
      <addressBlock>
        <offset>0</offset>
        <size>0x18</size>
        <usage>registers</usage>
      </addressBlock>
      <registers>
        <register>
          <name>PDOR</name>
          <description>Port Data Output Register</description>
          <addressOffset>0</addressOffset>
          <size>32</size>
          <access>read-write</access>
          <resetValue>0</resetValue>
          <resetMask>0xFFFFFFFF</resetMask>
          <fields>
            <field>
              <name>PDO</name>
              <description>Port Data Output</description>
              <bitOffset>0</bitOffset>
              <bitWidth>32</bitWidth>
              <access>read-write</access>
              <enumeratedValues>
                <enumeratedValue>
                  <name>0</name>
                  <description>Logic level 0 is driven on pin, provided pin is configured for general-purpose output.</description>
                  <value>#0</value>
                </enumeratedValue>
                <enumeratedValue>
                  <name>1</name>
                  <description>Logic level 1 is driven on pin, provided pin is configured for general-purpose output.</description>
                  <value>#1</value>
                </enumeratedValue>
              </enumeratedValues>
            </field>
          </fields>
        </register>
        <register>
          <name>PSOR</name>
          <description>Port Set Output Register</description>
          <addressOffset>0x4</addressOffset>
          <size>32</size>
          <access>write-only</access>
          <resetValue>0</resetValue>
          <resetMask>0xFFFFFFFF</resetMask>
          <fields>
            <field>
              <name>PTSO</name>
              <description>Port Set Output</description>
              <bitOffset>0</bitOffset>
              <bitWidth>32</bitWidth>
              <access>write-only</access>
              <enumeratedValues>
                <enumeratedValue>
                  <name>0</name>
                  <description>Corresponding bit in PDORn does not change.</description>
                  <value>#0</value>
                </enumeratedValue>
                <enumeratedValue>
                  <name>1</name>
                  <description>Corresponding bit in PDORn is set to logic 1.</description>
                  <value>#1</value>
                </enumeratedValue>
              </enumeratedValues>
            </field>
          </fields>
        </register>
        <register>
          <name>PCOR</name>
          <description>Port Clear Output Register</description>
          <addressOffset>0x8</addressOffset>
          <size>32</size>
          <access>write-only</access>
          <resetValue>0</resetValue>
          <resetMask>0xFFFFFFFF</resetMask>
          <fields>
            <field>
              <name>PTCO</name>
              <description>Port Clear Output</description>
              <bitOffset>0</bitOffset>
              <bitWidth>32</bitWidth>
              <access>write-only</access>
              <enumeratedValues>
                <enumeratedValue>
                  <name>0</name>
                  <description>Corresponding bit in PDORn does not change.</description>
                  <value>#0</value>
                </enumeratedValue>
                <enumeratedValue>
                  <name>1</name>
                  <description>Corresponding bit in PDORn is cleared to logic 0.</description>
                  <value>#1</value>
                </enumeratedValue>
              </enumeratedValues>
            </field>
          </fields>
        </register>
        <register>
          <name>PTOR</name>
          <description>Port Toggle Output Register</description>
          <addressOffset>0xC</addressOffset>
          <size>32</size>
          <access>write-only</access>
          <resetValue>0</resetValue>
          <resetMask>0xFFFFFFFF</resetMask>
          <fields>
            <field>
              <name>PTTO</name>
              <description>Port Toggle Output</description>
              <bitOffset>0</bitOffset>
              <bitWidth>32</bitWidth>
              <access>write-only</access>
              <enumeratedValues>
                <enumeratedValue>
                  <name>0</name>
                  <description>Corresponding bit in PDORn does not change.</description>
                  <value>#0</value>
                </enumeratedValue>
                <enumeratedValue>
                  <name>1</name>
                  <description>Corresponding bit in PDORn is set to the inverse of its existing logic state.</description>
                  <value>#1</value>
                </enumeratedValue>
              </enumeratedValues>
            </field>
          </fields>
        </register>
        <register>
          <name>PDIR</name>
          <description>Port Data Input Register</description>
          <addressOffset>0x10</addressOffset>
          <size>32</size>
          <access>read-only</access>
          <resetValue>0</resetValue>
          <resetMask>0xFFFFFFFF</resetMask>
          <fields>
            <field>
              <name>PDI</name>
              <description>Port Data Input</description>
              <bitOffset>0</bitOffset>
              <bitWidth>32</bitWidth>
              <access>read-only</access>
              <enumeratedValues>
                <enumeratedValue>
                  <name>0</name>
                  <description>Pin logic level is logic 0, or is not configured for use by digital function.</description>
                  <value>#0</value>
                </enumeratedValue>
                <enumeratedValue>
                  <name>1</name>
                  <description>Pin logic level is logic 1.</description>
                  <value>#1</value>
                </enumeratedValue>
              </enumeratedValues>
            </field>
          </fields>
        </register>
        <register>
          <name>PDDR</name>
          <description>Port Data Direction Register</description>
          <addressOffset>0x14</addressOffset>
          <size>32</size>
          <access>read-write</access>
          <resetValue>0</resetValue>
          <resetMask>0xFFFFFFFF</resetMask>
          <fields>
            <field>
              <name>PDD</name>
              <description>Port Data Direction</description>
              <bitOffset>0</bitOffset>
              <bitWidth>32</bitWidth>
              <access>read-write</access>
              <enumeratedValues>
                <enumeratedValue>
                  <name>0</name>
                  <description>Pin is configured as general-purpose input, for the GPIO function.</description>
                  <value>#0</value>
                </enumeratedValue>
                <enumeratedValue>
                  <name>1</name>
                  <description>Pin is configured as general-purpose output, for the GPIO function.</description>
                  <value>#1</value>
                </enumeratedValue>
              </enumeratedValues>
            </field>
          </fields>
        </register>
      </registers>
    </peripheral>
    <peripheral>
      <name>FGPIOD</name>
      <description>General Purpose Input/Output</description>
      <groupName>FGPIO</groupName>
      <prependToName>FGPIOD_</prependToName>
      <baseAddress>0xF80000C0</baseAddress>
      <addressBlock>
        <offset>0</offset>
        <size>0x18</size>
        <usage>registers</usage>
      </addressBlock>
      <registers>
        <register>
          <name>PDOR</name>
          <description>Port Data Output Register</description>
          <addressOffset>0</addressOffset>
          <size>32</size>
          <access>read-write</access>
          <resetValue>0</resetValue>
          <resetMask>0xFFFFFFFF</resetMask>
          <fields>
            <field>
              <name>PDO</name>
              <description>Port Data Output</description>
              <bitOffset>0</bitOffset>
              <bitWidth>32</bitWidth>
              <access>read-write</access>
              <enumeratedValues>
                <enumeratedValue>
                  <name>0</name>
                  <description>Logic level 0 is driven on pin, provided pin is configured for general-purpose output.</description>
                  <value>#0</value>
                </enumeratedValue>
                <enumeratedValue>
                  <name>1</name>
                  <description>Logic level 1 is driven on pin, provided pin is configured for general-purpose output.</description>
                  <value>#1</value>
                </enumeratedValue>
              </enumeratedValues>
            </field>
          </fields>
        </register>
        <register>
          <name>PSOR</name>
          <description>Port Set Output Register</description>
          <addressOffset>0x4</addressOffset>
          <size>32</size>
          <access>write-only</access>
          <resetValue>0</resetValue>
          <resetMask>0xFFFFFFFF</resetMask>
          <fields>
            <field>
              <name>PTSO</name>
              <description>Port Set Output</description>
              <bitOffset>0</bitOffset>
              <bitWidth>32</bitWidth>
              <access>write-only</access>
              <enumeratedValues>
                <enumeratedValue>
                  <name>0</name>
                  <description>Corresponding bit in PDORn does not change.</description>
                  <value>#0</value>
                </enumeratedValue>
                <enumeratedValue>
                  <name>1</name>
                  <description>Corresponding bit in PDORn is set to logic 1.</description>
                  <value>#1</value>
                </enumeratedValue>
              </enumeratedValues>
            </field>
          </fields>
        </register>
        <register>
          <name>PCOR</name>
          <description>Port Clear Output Register</description>
          <addressOffset>0x8</addressOffset>
          <size>32</size>
          <access>write-only</access>
          <resetValue>0</resetValue>
          <resetMask>0xFFFFFFFF</resetMask>
          <fields>
            <field>
              <name>PTCO</name>
              <description>Port Clear Output</description>
              <bitOffset>0</bitOffset>
              <bitWidth>32</bitWidth>
              <access>write-only</access>
              <enumeratedValues>
                <enumeratedValue>
                  <name>0</name>
                  <description>Corresponding bit in PDORn does not change.</description>
                  <value>#0</value>
                </enumeratedValue>
                <enumeratedValue>
                  <name>1</name>
                  <description>Corresponding bit in PDORn is cleared to logic 0.</description>
                  <value>#1</value>
                </enumeratedValue>
              </enumeratedValues>
            </field>
          </fields>
        </register>
        <register>
          <name>PTOR</name>
          <description>Port Toggle Output Register</description>
          <addressOffset>0xC</addressOffset>
          <size>32</size>
          <access>write-only</access>
          <resetValue>0</resetValue>
          <resetMask>0xFFFFFFFF</resetMask>
          <fields>
            <field>
              <name>PTTO</name>
              <description>Port Toggle Output</description>
              <bitOffset>0</bitOffset>
              <bitWidth>32</bitWidth>
              <access>write-only</access>
              <enumeratedValues>
                <enumeratedValue>
                  <name>0</name>
                  <description>Corresponding bit in PDORn does not change.</description>
                  <value>#0</value>
                </enumeratedValue>
                <enumeratedValue>
                  <name>1</name>
                  <description>Corresponding bit in PDORn is set to the inverse of its existing logic state.</description>
                  <value>#1</value>
                </enumeratedValue>
              </enumeratedValues>
            </field>
          </fields>
        </register>
        <register>
          <name>PDIR</name>
          <description>Port Data Input Register</description>
          <addressOffset>0x10</addressOffset>
          <size>32</size>
          <access>read-only</access>
          <resetValue>0</resetValue>
          <resetMask>0xFFFFFFFF</resetMask>
          <fields>
            <field>
              <name>PDI</name>
              <description>Port Data Input</description>
              <bitOffset>0</bitOffset>
              <bitWidth>32</bitWidth>
              <access>read-only</access>
              <enumeratedValues>
                <enumeratedValue>
                  <name>0</name>
                  <description>Pin logic level is logic 0, or is not configured for use by digital function.</description>
                  <value>#0</value>
                </enumeratedValue>
                <enumeratedValue>
                  <name>1</name>
                  <description>Pin logic level is logic 1.</description>
                  <value>#1</value>
                </enumeratedValue>
              </enumeratedValues>
            </field>
          </fields>
        </register>
        <register>
          <name>PDDR</name>
          <description>Port Data Direction Register</description>
          <addressOffset>0x14</addressOffset>
          <size>32</size>
          <access>read-write</access>
          <resetValue>0</resetValue>
          <resetMask>0xFFFFFFFF</resetMask>
          <fields>
            <field>
              <name>PDD</name>
              <description>Port Data Direction</description>
              <bitOffset>0</bitOffset>
              <bitWidth>32</bitWidth>
              <access>read-write</access>
              <enumeratedValues>
                <enumeratedValue>
                  <name>0</name>
                  <description>Pin is configured as general-purpose input, for the GPIO function.</description>
                  <value>#0</value>
                </enumeratedValue>
                <enumeratedValue>
                  <name>1</name>
                  <description>Pin is configured as general-purpose output, for the GPIO function.</description>
                  <value>#1</value>
                </enumeratedValue>
              </enumeratedValues>
            </field>
          </fields>
        </register>
      </registers>
    </peripheral>
    <peripheral>
      <name>FGPIOE</name>
      <description>General Purpose Input/Output</description>
      <groupName>FGPIO</groupName>
      <prependToName>FGPIOE_</prependToName>
      <baseAddress>0xF8000100</baseAddress>
      <addressBlock>
        <offset>0</offset>
        <size>0x18</size>
        <usage>registers</usage>
      </addressBlock>
      <registers>
        <register>
          <name>PDOR</name>
          <description>Port Data Output Register</description>
          <addressOffset>0</addressOffset>
          <size>32</size>
          <access>read-write</access>
          <resetValue>0</resetValue>
          <resetMask>0xFFFFFFFF</resetMask>
          <fields>
            <field>
              <name>PDO</name>
              <description>Port Data Output</description>
              <bitOffset>0</bitOffset>
              <bitWidth>32</bitWidth>
              <access>read-write</access>
              <enumeratedValues>
                <enumeratedValue>
                  <name>0</name>
                  <description>Logic level 0 is driven on pin, provided pin is configured for general-purpose output.</description>
                  <value>#0</value>
                </enumeratedValue>
                <enumeratedValue>
                  <name>1</name>
                  <description>Logic level 1 is driven on pin, provided pin is configured for general-purpose output.</description>
                  <value>#1</value>
                </enumeratedValue>
              </enumeratedValues>
            </field>
          </fields>
        </register>
        <register>
          <name>PSOR</name>
          <description>Port Set Output Register</description>
          <addressOffset>0x4</addressOffset>
          <size>32</size>
          <access>write-only</access>
          <resetValue>0</resetValue>
          <resetMask>0xFFFFFFFF</resetMask>
          <fields>
            <field>
              <name>PTSO</name>
              <description>Port Set Output</description>
              <bitOffset>0</bitOffset>
              <bitWidth>32</bitWidth>
              <access>write-only</access>
              <enumeratedValues>
                <enumeratedValue>
                  <name>0</name>
                  <description>Corresponding bit in PDORn does not change.</description>
                  <value>#0</value>
                </enumeratedValue>
                <enumeratedValue>
                  <name>1</name>
                  <description>Corresponding bit in PDORn is set to logic 1.</description>
                  <value>#1</value>
                </enumeratedValue>
              </enumeratedValues>
            </field>
          </fields>
        </register>
        <register>
          <name>PCOR</name>
          <description>Port Clear Output Register</description>
          <addressOffset>0x8</addressOffset>
          <size>32</size>
          <access>write-only</access>
          <resetValue>0</resetValue>
          <resetMask>0xFFFFFFFF</resetMask>
          <fields>
            <field>
              <name>PTCO</name>
              <description>Port Clear Output</description>
              <bitOffset>0</bitOffset>
              <bitWidth>32</bitWidth>
              <access>write-only</access>
              <enumeratedValues>
                <enumeratedValue>
                  <name>0</name>
                  <description>Corresponding bit in PDORn does not change.</description>
                  <value>#0</value>
                </enumeratedValue>
                <enumeratedValue>
                  <name>1</name>
                  <description>Corresponding bit in PDORn is cleared to logic 0.</description>
                  <value>#1</value>
                </enumeratedValue>
              </enumeratedValues>
            </field>
          </fields>
        </register>
        <register>
          <name>PTOR</name>
          <description>Port Toggle Output Register</description>
          <addressOffset>0xC</addressOffset>
          <size>32</size>
          <access>write-only</access>
          <resetValue>0</resetValue>
          <resetMask>0xFFFFFFFF</resetMask>
          <fields>
            <field>
              <name>PTTO</name>
              <description>Port Toggle Output</description>
              <bitOffset>0</bitOffset>
              <bitWidth>32</bitWidth>
              <access>write-only</access>
              <enumeratedValues>
                <enumeratedValue>
                  <name>0</name>
                  <description>Corresponding bit in PDORn does not change.</description>
                  <value>#0</value>
                </enumeratedValue>
                <enumeratedValue>
                  <name>1</name>
                  <description>Corresponding bit in PDORn is set to the inverse of its existing logic state.</description>
                  <value>#1</value>
                </enumeratedValue>
              </enumeratedValues>
            </field>
          </fields>
        </register>
        <register>
          <name>PDIR</name>
          <description>Port Data Input Register</description>
          <addressOffset>0x10</addressOffset>
          <size>32</size>
          <access>read-only</access>
          <resetValue>0</resetValue>
          <resetMask>0xFFFFFFFF</resetMask>
          <fields>
            <field>
              <name>PDI</name>
              <description>Port Data Input</description>
              <bitOffset>0</bitOffset>
              <bitWidth>32</bitWidth>
              <access>read-only</access>
              <enumeratedValues>
                <enumeratedValue>
                  <name>0</name>
                  <description>Pin logic level is logic 0, or is not configured for use by digital function.</description>
                  <value>#0</value>
                </enumeratedValue>
                <enumeratedValue>
                  <name>1</name>
                  <description>Pin logic level is logic 1.</description>
                  <value>#1</value>
                </enumeratedValue>
              </enumeratedValues>
            </field>
          </fields>
        </register>
        <register>
          <name>PDDR</name>
          <description>Port Data Direction Register</description>
          <addressOffset>0x14</addressOffset>
          <size>32</size>
          <access>read-write</access>
          <resetValue>0</resetValue>
          <resetMask>0xFFFFFFFF</resetMask>
          <fields>
            <field>
              <name>PDD</name>
              <description>Port Data Direction</description>
              <bitOffset>0</bitOffset>
              <bitWidth>32</bitWidth>
              <access>read-write</access>
              <enumeratedValues>
                <enumeratedValue>
                  <name>0</name>
                  <description>Pin is configured as general-purpose input, for the GPIO function.</description>
                  <value>#0</value>
                </enumeratedValue>
                <enumeratedValue>
                  <name>1</name>
                  <description>Pin is configured as general-purpose output, for the GPIO function.</description>
                  <value>#1</value>
                </enumeratedValue>
              </enumeratedValues>
            </field>
          </fields>
        </register>
      </registers>
    </peripheral>
  </peripherals>
</device>
